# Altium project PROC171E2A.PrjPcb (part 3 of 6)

## Sheet PROC171_AM263P_6_ePWM_eQEP_FSI.SchDoc
size 431 x 279 mm; Date: Not shown in title block; ApprovedBy: Not shown in title block; CheckedBy: Not shown in title block; Author: Not shown in title block; CompanyName: Not shown in title block; Engineer: Not shown in title block; Organization: Not shown in title block; Address1: Not shown in title block; Address2: Not shown in title block; Address3: Not shown in title block; Address4: Not shown in title block; DocumentNumber: 10; Revision: Use project parameter SCH_Rev; SheetNumber: 10; SheetTotal: 26; PageSetup: Record=PageOptions¦CenterHorizontal=True¦CenterVertical=True¦PrintScale=1.00¦XCorrection=1.00¦YCorrection=1.00¦PrintKind=0¦BorderSize=5000000¦LeftOffset=0¦BottomOffset=0¦Orientation=2¦PaperLength=1000¦PaperWidth=1000¦Scale=100¦PaperSource=15¦PrintQuality=600¦MediaType=1¦DitherType=10¦PaperKind=Letter¦PrintScaleMode=1

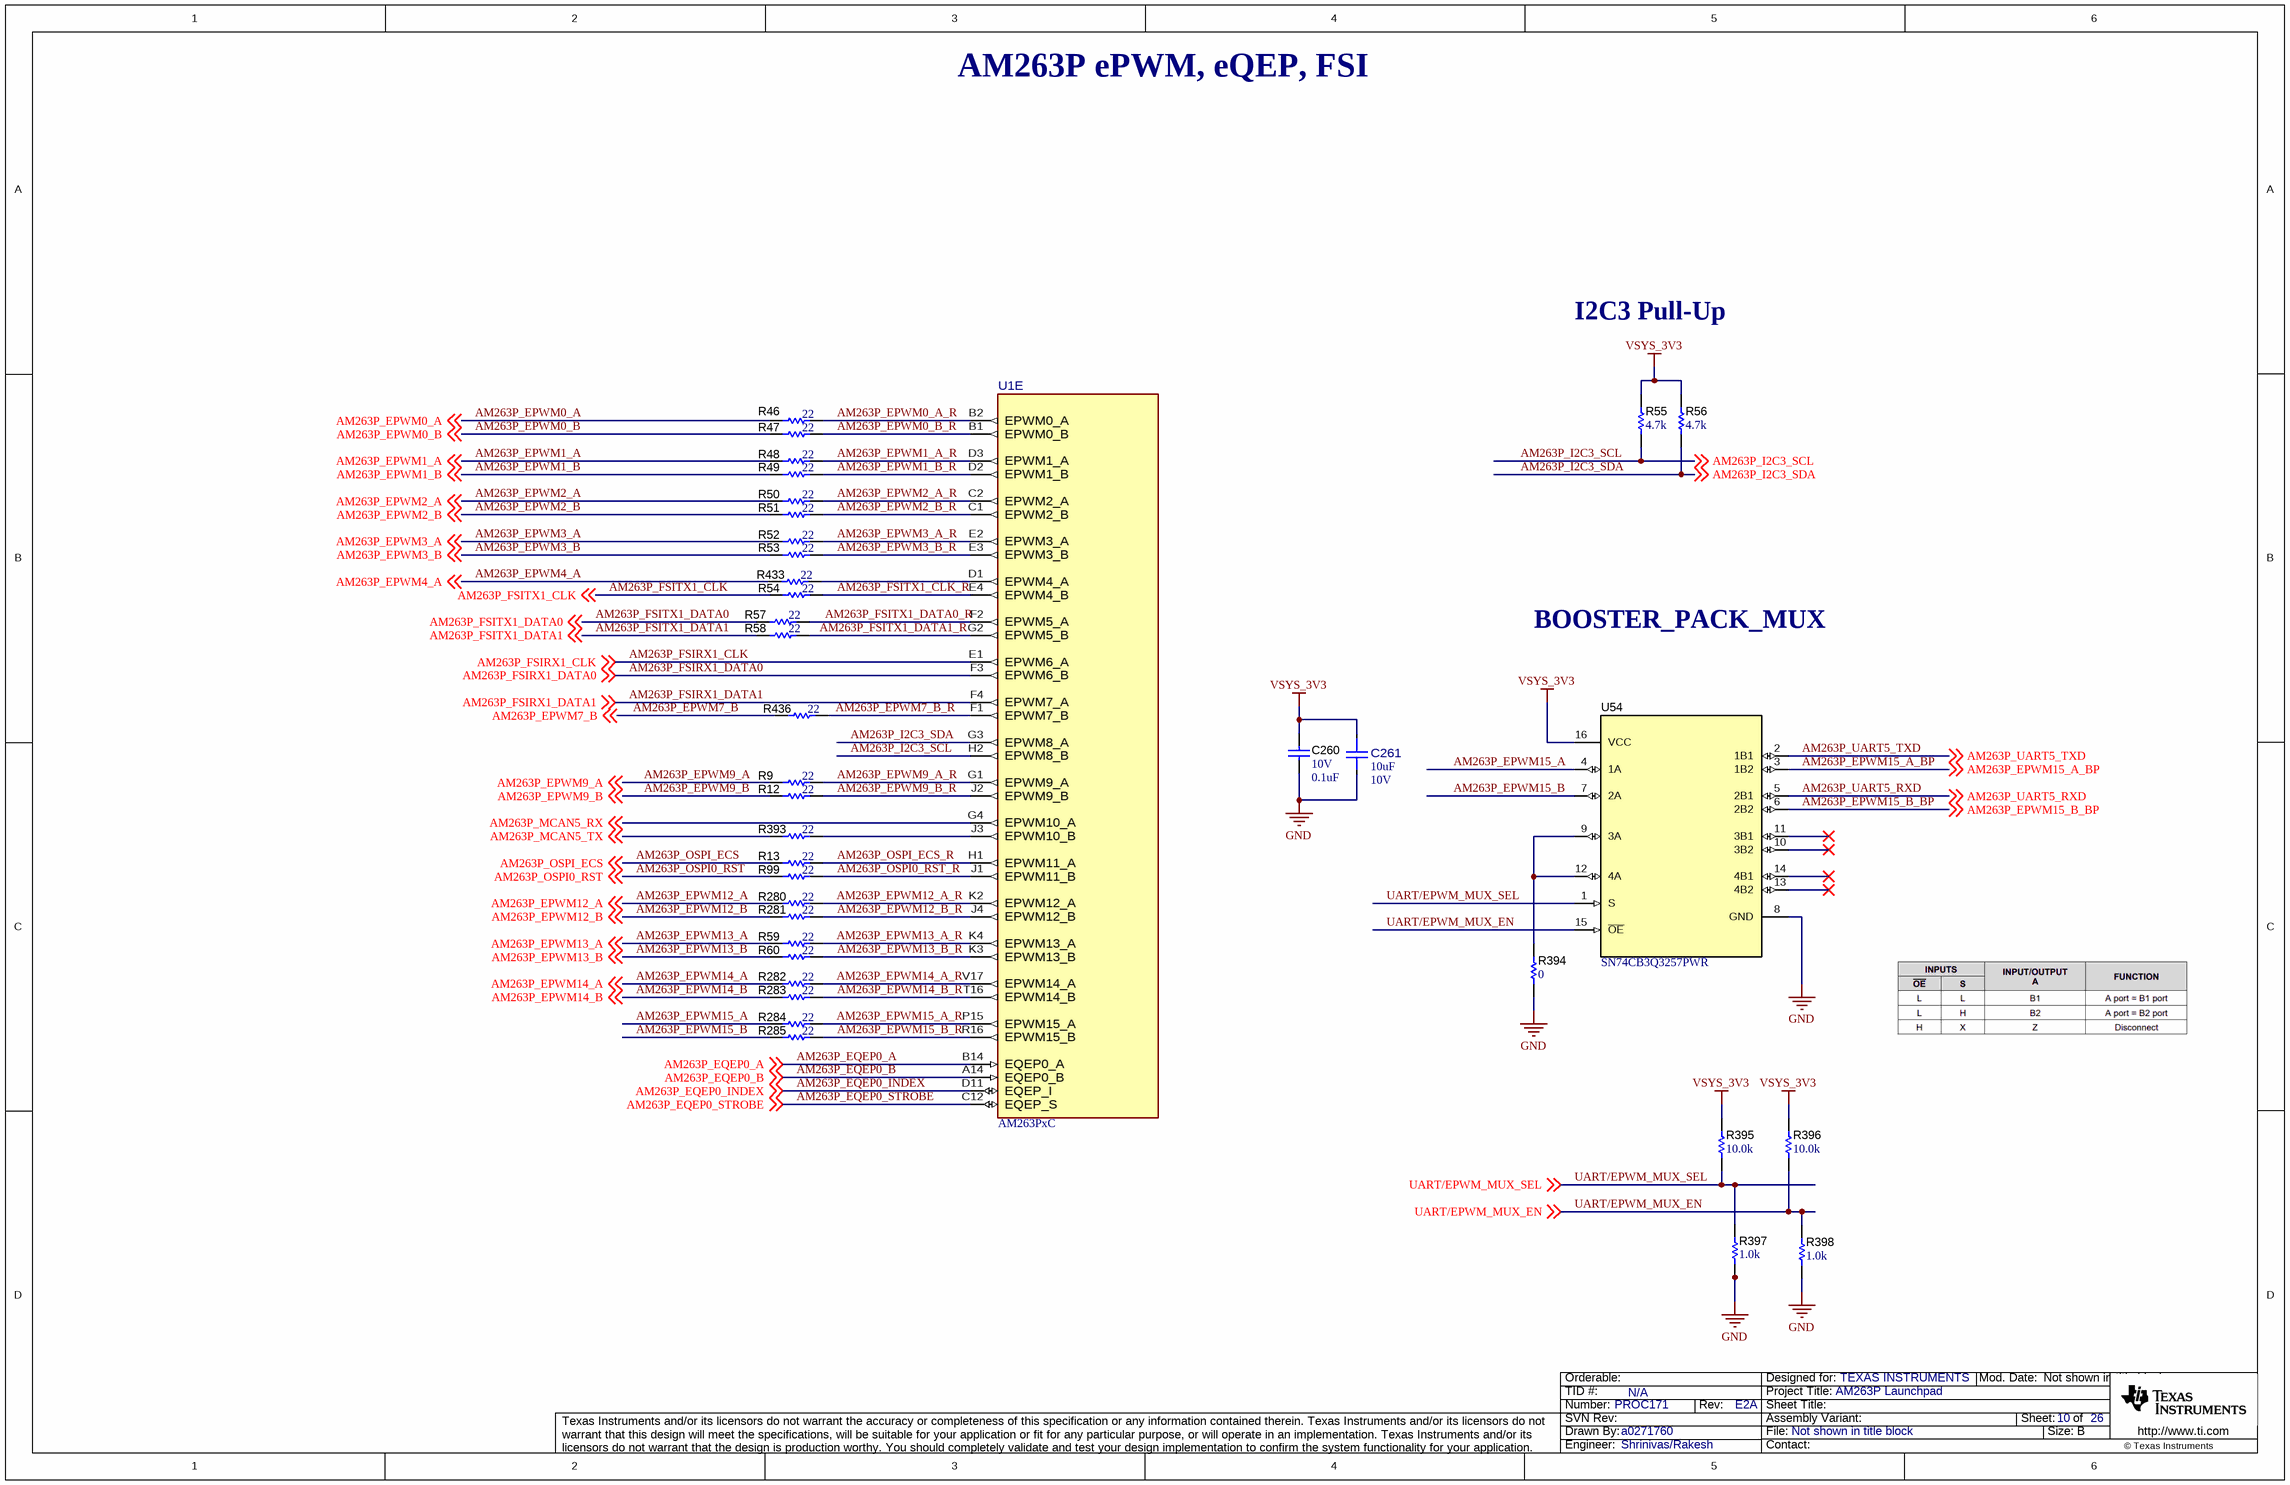
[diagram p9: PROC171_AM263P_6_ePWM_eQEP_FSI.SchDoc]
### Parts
C260  VDC_V: 10V  ValueDisplayed: 0.1uF  [0402]  (hidden comment: 885012105010)
C261  ValueDisplayed: 10uF  VDC_V: 10V  [FP-KGM05CR51A106MH_0402-MFG]  (hidden comment: KGM05CR51A106MH)
R9  ValueDisplayed: 22  [0402]  (hidden comment: CRCW040222R0JNED)
R12  ValueDisplayed: 22  [0402]  (hidden comment: CRCW040222R0JNED)
R13  ValueDisplayed: 22  [0402]  (hidden comment: CRCW040222R0JNED)
R46  ValueDisplayed: 22  [0402]  (hidden comment: CRCW040222R0JNED)
R47  ValueDisplayed: 22  [0402]  (hidden comment: CRCW040222R0JNED)
R48  ValueDisplayed: 22  [0402]  (hidden comment: CRCW040222R0JNED)
R49  ValueDisplayed: 22  [0402]  (hidden comment: CRCW040222R0JNED)
R50  ValueDisplayed: 22  [0402]  (hidden comment: CRCW040222R0JNED)
R51  ValueDisplayed: 22  [0402]  (hidden comment: CRCW040222R0JNED)
R52  ValueDisplayed: 22  [0402]  (hidden comment: CRCW040222R0JNED)
R53  ValueDisplayed: 22  [0402]  (hidden comment: CRCW040222R0JNED)
R54  ValueDisplayed: 22  [0402]  (hidden comment: CRCW040222R0JNED)
R55  ValueDisplayed: 4.7k  [0402]  (hidden comment: CRCW04024K70JNED)
R56  ValueDisplayed: 4.7k  [0402]  (hidden comment: CRCW04024K70JNED)
R57  ValueDisplayed: 22  [0402]  (hidden comment: CRCW040222R0JNED)
R58  ValueDisplayed: 22  [0402]  (hidden comment: CRCW040222R0JNED)
R59  ValueDisplayed: 22  [0402]  (hidden comment: CRCW040222R0JNED)
R60  ValueDisplayed: 22  [0402]  (hidden comment: CRCW040222R0JNED)
R99  ValueDisplayed: 22  [0402]  (hidden comment: CRCW040222R0JNED)
R280  ValueDisplayed: 22  [0402]  (hidden comment: CRCW040222R0JNED)
R281  ValueDisplayed: 22  [0402]  (hidden comment: CRCW040222R0JNED)
R282  ValueDisplayed: 22  [0402]  (hidden comment: CRCW040222R0JNED)
R283  ValueDisplayed: 22  [0402]  (hidden comment: CRCW040222R0JNED)
R284  ValueDisplayed: 22  [0402]  (hidden comment: CRCW040222R0JNED)
R285  ValueDisplayed: 22  [0402]  (hidden comment: CRCW040222R0JNED)
R393  ValueDisplayed: 22  [0402]  (hidden comment: CRCW040222R0JNED)
R394  value 0  [0402L]  (hidden comment: ERJ-2GE0R00X)
R395  ValueDisplayed: 10.0k  [0402]  (hidden comment: ERJ-2RKF1002X)
R396  ValueDisplayed: 10.0k  [0402]  (hidden comment: ERJ-2RKF1002X)
R397  ValueDisplayed: 1.0k  [0402]  (hidden comment: ERJ-2GEJ102X)
R398  ValueDisplayed: 1.0k  [0402]  (hidden comment: ERJ-2GEJ102X)
R433  ValueDisplayed: 22  [0402]  (hidden comment: CRCW040222R0JNED)
R436  ValueDisplayed: 22  [0402]  (hidden comment: CRCW040222R0JNED)
U1  AM263PxC  [ZCZ0324A-MFG]  (part E of 13)
U54  SN74CB3Q3257PWR  [PW0016A_L]

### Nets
GND: C260.2 C261.2 R394.1 R397.1 R398.1 U54.8(GND)
VSYS_3V3: C260.1 C261.1 R55.2 R56.2 R395.2 R396.2 U54.16(VCC)
AM263P_EPWM0_A: R46.1 ; off-sheet AM263P_EPWM0_A
AM263P_EPWM0_A_R: R46.2 U1.B2(EPWM0_A)
AM263P_EPWM0_B: R47.1 ; off-sheet AM263P_EPWM0_B
AM263P_EPWM0_B_R: R47.2 U1.B1(EPWM0_B)
AM263P_EPWM1_A: R48.1 ; off-sheet AM263P_EPWM1_A
AM263P_EPWM1_A_R: R48.2 U1.D3(EPWM1_A)
AM263P_EPWM1_B: R49.1 ; off-sheet AM263P_EPWM1_B
AM263P_EPWM1_B_R: R49.2 U1.D2(EPWM1_B)
AM263P_EPWM2_A: R50.1 ; off-sheet AM263P_EPWM2_A
AM263P_EPWM2_A_R: R50.2 U1.C2(EPWM2_A)
AM263P_EPWM2_B: R51.1 ; off-sheet AM263P_EPWM2_B
AM263P_EPWM2_B_R: R51.2 U1.C1(EPWM2_B)
AM263P_EPWM3_A: R52.1 ; off-sheet AM263P_EPWM3_A
AM263P_EPWM3_A_R: R52.2 U1.E2(EPWM3_A)
AM263P_EPWM3_B: R53.1 ; off-sheet AM263P_EPWM3_B
AM263P_EPWM3_B_R: R53.2 U1.E3(EPWM3_B)
AM263P_EPWM4_A: R433.1 ; off-sheet AM263P_EPWM4_A
AM263P_EPWM7_B: R436.1 ; off-sheet AM263P_EPWM7_B
AM263P_EPWM7_B_R: R436.2 U1.F1(EPWM7_B)
AM263P_EPWM9_A: R9.1 ; off-sheet AM263P_EPWM9_A
AM263P_EPWM9_A_R: R9.2 U1.G1(EPWM9_A)
AM263P_EPWM9_B: R12.1 ; off-sheet AM263P_EPWM9_B
AM263P_EPWM9_B_R: R12.2 U1.J2(EPWM9_B)
AM263P_EPWM12_A: R280.1 ; off-sheet AM263P_EPWM12_A
AM263P_EPWM12_A_R: R280.2 U1.K2(EPWM12_A)
AM263P_EPWM12_B: R281.1 ; off-sheet AM263P_EPWM12_B
AM263P_EPWM12_B_R: R281.2 U1.J4(EPWM12_B)
AM263P_EPWM13_A: R59.1 ; off-sheet AM263P_EPWM13_A
AM263P_EPWM13_A_R: R59.2 U1.K4(EPWM13_A)
AM263P_EPWM13_B: R60.1 ; off-sheet AM263P_EPWM13_B
AM263P_EPWM13_B_R: R60.2 U1.K3(EPWM13_B)
AM263P_EPWM14_A: R282.1 ; off-sheet AM263P_EPWM14_A
AM263P_EPWM14_A_R: R282.2 U1.V17(EPWM14_A)
AM263P_EPWM14_B: R283.1 ; off-sheet AM263P_EPWM14_B
AM263P_EPWM14_B_R: R283.2 U1.T16(EPWM14_B)
AM263P_EPWM15_A: R284.1 U54.4(1A)
AM263P_EPWM15_A_BP: U54.3(1B2) ; off-sheet AM263P_EPWM15_A_BP
AM263P_EPWM15_A_R: R284.2 U1.P15(EPWM15_A)
AM263P_EPWM15_B: R285.1 U54.7(2A)
AM263P_EPWM15_B_BP: U54.6(2B2) ; off-sheet AM263P_EPWM15_B_BP
AM263P_EPWM15_B_R: R285.2 U1.R16(EPWM15_B)
AM263P_EQEP0_A: U1.B14(EQEP0_A) ; off-sheet AM263P_EQEP0_A
AM263P_EQEP0_B: U1.A14(EQEP0_B) ; off-sheet AM263P_EQEP0_B
AM263P_EQEP0_INDEX: U1.D11(EQEP_I) ; off-sheet AM263P_EQEP0_INDEX
AM263P_EQEP0_STROBE: U1.C12(EQEP_S) ; off-sheet AM263P_EQEP0_STROBE
AM263P_FSIRX1_CLK: U1.E1(EPWM6_A) ; off-sheet AM263P_FSIRX1_CLK
AM263P_FSIRX1_DATA0: U1.F3(EPWM6_B) ; off-sheet AM263P_FSIRX1_DATA0
AM263P_FSIRX1_DATA1: U1.F4(EPWM7_A) ; off-sheet AM263P_FSIRX1_DATA1
AM263P_FSITX1_CLK: R54.1 ; off-sheet AM263P_FSITX1_CLK
AM263P_FSITX1_CLK_R: R54.2 U1.E4(EPWM4_B)
AM263P_FSITX1_DATA0: R57.1 ; off-sheet AM263P_FSITX1_DATA0
AM263P_FSITX1_DATA0_R: R57.2 U1.F2(EPWM5_A)
AM263P_FSITX1_DATA1: R58.1 ; off-sheet AM263P_FSITX1_DATA1
AM263P_FSITX1_DATA1_R: R58.2 U1.G2(EPWM5_B)
AM263P_I2C3_SCL: R55.1 U1.H2(EPWM8_B) ; off-sheet AM263P_I2C3_SCL
AM263P_I2C3_SDA: R56.1 U1.G3(EPWM8_A) ; off-sheet AM263P_I2C3_SDA
AM263P_MCAN5_RX: U1.G4(EPWM10_A) ; off-sheet AM263P_MCAN5_RX
AM263P_MCAN5_TX: R393.1 ; off-sheet AM263P_MCAN5_TX
AM263P_OSPI0_RST: R99.1 ; off-sheet AM263P_OSPI0_RST
AM263P_OSPI0_RST_R: R99.2 U1.J1(EPWM11_B)
AM263P_OSPI_ECS: R13.1 ; off-sheet AM263P_OSPI_ECS
AM263P_OSPI_ECS_R: R13.2 U1.H1(EPWM11_A)
AM263P_UART5_RXD: U54.5(2B1) ; off-sheet AM263P_UART5_RXD
AM263P_UART5_TXD: U54.2(1B1) ; off-sheet AM263P_UART5_TXD
UART/EPWM_MUX_EN: R396.1 R398.2 U54.15(~{OE}) ; off-sheet UART/EPWM_MUX_EN
UART/EPWM_MUX_SEL: R395.1 R397.2 U54.1(S) ; off-sheet UART/EPWM_MUX_SEL
NetR393_2: R393.2 U1.J3(EPWM10_B)
NetR394_2: R394.2 U54.9(3A) U54.12(4A)
NetR433_2: R433.2 U1.D1(EPWM4_A)

Not connected (* = marked no-connect by the designer): U54 10(3B2)* 11(3B1)* 13(4B2)* 14(4B1)*

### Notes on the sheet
- AM263P ePWM, eQEP, FSI
- I2C3 Pull-Up
- BOOSTER_PACK_MUX

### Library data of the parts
C260 = CMP-0006221-2: CAP, CERM, 0.1 uF, 10 V, +/- 20%, X5R, 0402; Manufacturer: Wurth Elektronik; TaMin_C: -55°C; Polarized: N; SizeAreaWB_mm2: 3; Value1: Unknown; U/M: EA; Value: 0.1uF; TaMax_C: 85°C; SizeZ_mm: 0.6; SizeX_mm: 1; SizeY_mm: 0.5; Cap_F: 100nF; AEC Category: Q200
C261 = CMP-0043010-1: 10 µF ±20% 10V Ceramic Capacitor X5R 0402 (1005 Metric); Manufacturer: KYOCERA AVX; AEC Qualified: No; Cap_F: 10µF; SizeZ_mm: 0.7mm; TempCo: 15%; Value: 10µF
R9 R12 R13 R46-R54 R57-R60 R99 R280-R285 R393 R433 R436 = CMP-0026880-3: RES, 22, 5%, 0.063 W, AEC-Q200 Grade 0, 0402; Manufacturer: Vishay-Dale; Power_W: 63mW; TempCo: 200 ppm/C; Value_Code: 22R0; Value: 22; EIA_Code: E24; SizeX_mm: 1; SizeY_mm: 0.5; SizeZ_mm: 0.6; Value2: 0.063W; AEC Qualified: Y; VDC_V: 50V; AEC Category: Q200; AEC Grade: 0
R55 R56 = CMP-0026938-5: RES, 4.7 k, 5%, 0.063 W, AEC-Q200 Grade 0, 0402; Manufacturer: Vishay-Dale; Power_W: 63mW; TempCo: 200 ppm/C; Value_Code: 4k70; Value: 4.7k; EIA_Code: E24; SizeX_mm: 1; SizeY_mm: 0.5; SizeZ_mm: 0.6; Value2: 0.063W; AEC Qualified: Y; VDC_V: 50V; AEC Category: Q200; AEC Grade: 0
R394 = CMP-0026992-3: RES, 0, 5%, 0.1 W, AEC-Q200 Grade 0, 0402; Manufacturer: Panasonic; Power_W: 100mW; TempCo: 600 ppm/C; Value_Code: 0000; EIA_Code: E24; SizeX_mm: 1; SizeY_mm: 0.5; SizeZ_mm: 0.6; Value2: 0.1W; AEC Qualified: Y; VDC_V: 50V; AEC Category: Q200; SizeAreaWB_mm2: 3
R395 R396 = CMP-0026658-1: RES, 10.0 k, 1%, 0.1 W, 0402; Manufacturer: Panasonic; Power_W: 100mW; TempCo: 100 ppm/C; Value_Code: 10k0; U/M: EA; Value: 10.0k; EIA_Code: E96; Res_ohm: 10k; SizeX_mm: 1; SizeY_mm: 0.5; SizeZ_mm: 0.6; Value2: 0.1W; VDC_V: 50V; AEC Category: Q200
R397 R398 = CMP-0078193-1: RES, 1.0 k, 5%, 0.1 W, AEC-Q200 Grade 0, 0402; Manufacturer: Panasonic; Value_Code: 1k00; SizeArea_mm2: 0.5; AEC Qualified: Y; AEC Category: Q200; Res_ohm: 1k; Value: 1.0k; SizeZ_mm: 0.6; Green_REACh: Passed; EIA_Code: E24; TempCo: 200 ppm/C; AEC Grade: 0; Power_W: 100mW; VDC_V: 50V; Value2: 0.1W; Green_Lifecycle: Active; U/M: EA; SizeX_mm: 1
U1 = CMP-0001698-2: Sitara™ Microcontroller; Manufacturer: Texas Instruments; SizeZ_mm: 1.4mm; Core Architecture: ARM Cortex-R5F; Data Bus Width: 32bits; Frequency_Fixed: 200MHz; Interface: I2C,SPI,UART,CAN,LIN,Ethernet,Other; Max Supply Voltage: 3.465V; Memory Size: 2MBytes; Memory Type: RAM; Min Supply Voltage: 1.14V; Number Of Cores: 1; Number Of I/Os: 140; Number Of I2C Channels: 4; Number Of Spi Channels: 5; Number Of Uart Channels: 6; Standoff Height: 0.35mm; AEC Category: Q200; CompType: IC
U54 = CMP-0076540-1: 4-Bit One-of-2 FET Multiplexer/Demultiplexer 2.5-V/3.3-V Low-Voltage, High-Bandwidth Bus Switch, PW0016A (TSSOP-16); Manufacturer: Texas Instruments; SizeAreaWB_mm2: 58.8; SizeArea_mm2: 32.0; SizeZ_mm: 1.2; SizeY_mm: 5.0; U/M: EA; CompType: IC; SizeX_mm: 6.4

## Sheet PROC171_AM263P_7_RGMII_MII.SchDoc
size 431 x 279 mm; Date: Not shown in title block; ApprovedBy: Not shown in title block; CheckedBy: Not shown in title block; Author: Not shown in title block; CompanyName: Not shown in title block; Engineer: Not shown in title block; Organization: Not shown in title block; Address1: Not shown in title block; Address2: Not shown in title block; Address3: Not shown in title block; Address4: Not shown in title block; DocumentNumber: 11; Revision: Use project parameter SCH_Rev; SheetNumber: 11; SheetTotal: 26; PageSetup: Record=PageOptions¦CenterHorizontal=True¦CenterVertical=True¦PrintScale=1.00¦XCorrection=1.00¦YCorrection=1.00¦PrintKind=0¦BorderSize=5000000¦LeftOffset=0¦BottomOffset=0¦Orientation=2¦PaperLength=1000¦PaperWidth=1000¦Scale=100¦PaperSource=15¦PrintQuality=600¦MediaType=1¦DitherType=10¦PaperKind=Letter¦PrintScaleMode=1

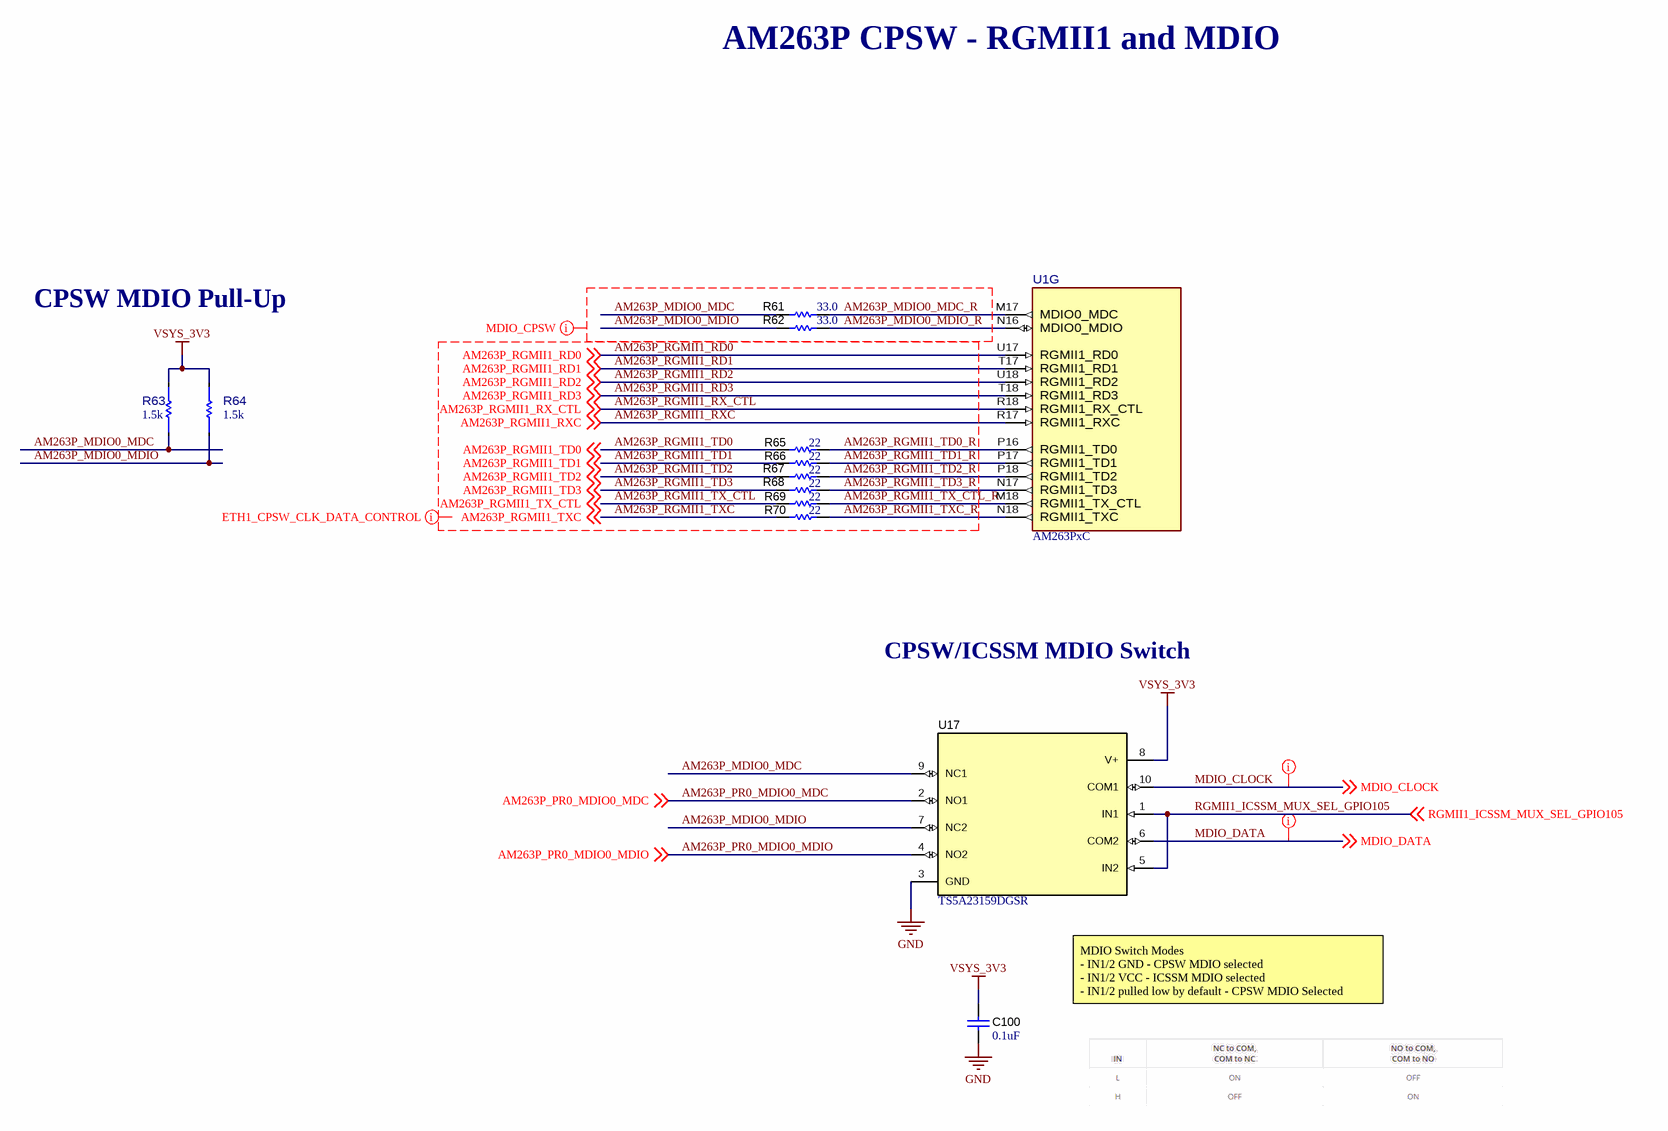
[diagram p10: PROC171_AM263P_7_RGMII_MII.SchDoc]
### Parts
C100  ValueDisplayed: 0.1uF  [0402]  (hidden comment: GRM155R71E104KE14D)
R61  ValueDisplayed: 33.0  [0402L]  (hidden comment: ERJ-2RKF33R0X)
R62  ValueDisplayed: 33.0  [0402L]  (hidden comment: ERJ-2RKF33R0X)
R63  value 1.5k  [FP-ERJ-2GEJ152X_0402-MFG]  (hidden comment: ERJ-2GEJ152X)
R64  value 1.5k  [FP-ERJ-2GEJ152X_0402-MFG]  (hidden comment: ERJ-2GEJ152X)
R65  ValueDisplayed: 22  [0402]  (hidden comment: CRCW040222R0JNED)
R66  ValueDisplayed: 22  [0402]  (hidden comment: CRCW040222R0JNED)
R67  ValueDisplayed: 22  [0402]  (hidden comment: CRCW040222R0JNED)
R68  ValueDisplayed: 22  [0402]  (hidden comment: CRCW040222R0JNED)
R69  ValueDisplayed: 22  [0402]  (hidden comment: CRCW040222R0JNED)
R70  ValueDisplayed: 22  [0402]  (hidden comment: CRCW040222R0JNED)
U1  AM263PxC  [ZCZ0324A-MFG]  (part G of 13)
U17  TS5A23159DGSR  [DGS0010A_N]

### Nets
GND: C100.1 U17.3(GND)
VSYS_3V3: C100.2 R63.2 R64.2 U17.8(V+)
AM263P_MDIO0_MDC: R61.1 R63.1 U17.9(NC1)
AM263P_MDIO0_MDC_R: R61.2 U1.M17(MDIO0_MDC)
AM263P_MDIO0_MDIO: R62.1 R64.1 U17.7(NC2)
AM263P_MDIO0_MDIO_R: R62.2 U1.N16(MDIO0_MDIO)
AM263P_PR0_MDIO0_MDC: U17.2(NO1) ; off-sheet AM263P_PR0_MDIO0_MDC
AM263P_PR0_MDIO0_MDIO: U17.4(NO2) ; off-sheet AM263P_PR0_MDIO0_MDIO
AM263P_RGMII1_RD0: U1.U17(RGMII1_RD0) ; off-sheet AM263P_RGMII1_RD0
AM263P_RGMII1_RD1: U1.T17(RGMII1_RD1) ; off-sheet AM263P_RGMII1_RD1
AM263P_RGMII1_RD2: U1.U18(RGMII1_RD2) ; off-sheet AM263P_RGMII1_RD2
AM263P_RGMII1_RD3: U1.T18(RGMII1_RD3) ; off-sheet AM263P_RGMII1_RD3
AM263P_RGMII1_RX_CTL: U1.R18(RGMII1_RX_CTL) ; off-sheet AM263P_RGMII1_RX_CTL
AM263P_RGMII1_RXC: U1.R17(RGMII1_RXC) ; off-sheet AM263P_RGMII1_RXC
AM263P_RGMII1_TD0: R65.1 ; off-sheet AM263P_RGMII1_TD0
AM263P_RGMII1_TD0_R: R65.2 U1.P16(RGMII1_TD0)
AM263P_RGMII1_TD1: R66.1 ; off-sheet AM263P_RGMII1_TD1
AM263P_RGMII1_TD1_R: R66.2 U1.P17(RGMII1_TD1)
AM263P_RGMII1_TD2: R67.1 ; off-sheet AM263P_RGMII1_TD2
AM263P_RGMII1_TD2_R: R67.2 U1.P18(RGMII1_TD2)
AM263P_RGMII1_TD3: R68.1 ; off-sheet AM263P_RGMII1_TD3
AM263P_RGMII1_TD3_R: R68.2 U1.N17(RGMII1_TD3)
AM263P_RGMII1_TX_CTL: R69.1 ; off-sheet AM263P_RGMII1_TX_CTL
AM263P_RGMII1_TX_CTL_R: R69.2 U1.M18(RGMII1_TX_CTL)
AM263P_RGMII1_TXC: R70.1 ; off-sheet AM263P_RGMII1_TXC
AM263P_RGMII1_TXC_R: R70.2 U1.N18(RGMII1_TXC)
MDIO_CLOCK: U17.10(COM1) ; off-sheet MDIO_CLOCK
MDIO_DATA: U17.6(COM2) ; off-sheet MDIO_DATA
RGMII1_ICSSM_MUX_SEL_GPIO105: U17.1(IN1) U17.5(IN2) ; off-sheet RGMII1_ICSSM_MUX_SEL_GPIO105

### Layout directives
mark named ETH1_CPSW_CLK_DATA_CONTROL: AM263P_RGMII1_RD0, AM263P_RGMII1_RD1, AM263P_RGMII1_RD2, AM263P_RGMII1_RD3, AM263P_RGMII1_RX_CTL, AM263P_RGMII1_RXC, AM263P_RGMII1_TD0, AM263P_RGMII1_TD0_R, AM263P_RGMII1_TD1, AM263P_RGMII1_TD1_R, AM263P_RGMII1_TD2, AM263P_RGMII1_TD2_R, AM263P_RGMII1_TD3, AM263P_RGMII1_TD3_R, AM263P_RGMII1_TX_CTL, AM263P_RGMII1_TX_CTL_R, AM263P_RGMII1_TXC, AM263P_RGMII1_TXC_R
mark named MDIO_CPSW: AM263P_MDIO0_MDC, AM263P_MDIO0_MDC_R, AM263P_MDIO0_MDIO, AM263P_MDIO0_MDIO_R
mark named MDIO: MDIO_CLOCK, MDIO_DATA

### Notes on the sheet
- AM263P CPSW - RGMII1 and MDIO
- CPSW MDIO Pull-Up
- CPSW/ICSSM MDIO Switch
- MDIO Switch Modes
  - IN1/2 GND - CPSW MDIO selected
  - IN1/2 VCC - ICSSM MDIO selected
  - IN1/2 pulled low by default - CPSW MDIO Selected

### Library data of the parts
C100 = CMP-0006659-2: CAP, CERM, 0.1 uF, 25 V, +/- 10%, X7R, 0402; Manufacturer: MuRata; TaMin_C: -55°C; Polarized: N; SizeAreaWB_mm2: 3; U/M: EA; Value: 0.1uF; TaMax_C: 125°C; SizeZ_mm: 0.6; SizeX_mm: 1; SizeY_mm: 0.5; Value2: 25V; Cap_F: 100nF; AEC Category: Q200; Value1: Unknown
R61 R62 = CMP-0026696-1: RES, 33.0, 1%, 0.1 W, 0402; Manufacturer: Panasonic; Power_W: 100mW; TempCo: 100 ppm/C; Value_Code: 33R0; U/M: EA; Value: 33.0; Res_ohm: 33; SizeX_mm: 1; SizeY_mm: 0.5; SizeZ_mm: 0.6; Value2: 0.1W; VDC_V: 50V; AEC Category: Q200
R63 R64 = CMP-0042990-1: Res Thick Film 0402 1.5K Ohm 5% 1/10W ±200ppm/°C Molded SMD Punched Carrier T/R; Manufacturer: Panasonic; AEC Grade: Grade 0; AEC Qualified: Yes; Power_W: 100mW; SizeZ_mm: 0.4mm; VDC_V: 50V; Category 5A00970A6D5C81C7: Uncategorized; Category 5C6A91606D4187Ad: Resistors; Category 7542B8484461Ae85: Passive Components; Category Cd01000Bfc2916C6: Single Components
R65-R70 = CMP-0026880-3: as R9 on sheet PROC171_AM263P_6_ePWM_eQEP_FSI
U1 = CMP-0001698-2: as U1 on sheet PROC171_AM263P_6_ePWM_eQEP_FSI
U17 = CMP-0067419-2: 2-Channel, 2:1 Analog Switch with Low On-State Resistance (1ohm) and Powered Off Protection, DGS0010A (VSSOP-10); Alternate PartNumber: TS5A23159DGST; Alternate Manufacturer: Texas Instruments; Green_Lifecycle: Active; SizeAreaWB_mm2: 23.6; Green_REACh: Passed; SizeZ_mm: 1.1; SizeX_mm: 4.9; SizeY_mm: 3.0; SizeArea_mm2: 14.7; CompType: IC; AEC Category: Q200; AEC Qualified: N; Rating: Catalog

## Sheet PROC171_AM263P_8_PRU.SchDoc
size 431 x 279 mm; Date: Not shown in title block; ApprovedBy: Not shown in title block; CheckedBy: Not shown in title block; Author: Not shown in title block; CompanyName: Not shown in title block; Engineer: Not shown in title block; Organization: Not shown in title block; Address1: Not shown in title block; Address2: Not shown in title block; Address3: Not shown in title block; Address4: Not shown in title block; DocumentNumber: 12; Revision: Use project parameter SCH_Rev; SheetNumber: 12; SheetTotal: 26; PageSetup: Record=PageOptions¦CenterHorizontal=True¦CenterVertical=True¦PrintScale=1.00¦XCorrection=1.00¦YCorrection=1.00¦PrintKind=0¦BorderSize=5000000¦LeftOffset=0¦BottomOffset=0¦Orientation=2¦PaperLength=1000¦PaperWidth=1000¦Scale=100¦PaperSource=15¦PrintQuality=600¦MediaType=1¦DitherType=10¦PaperKind=Letter¦PrintScaleMode=1

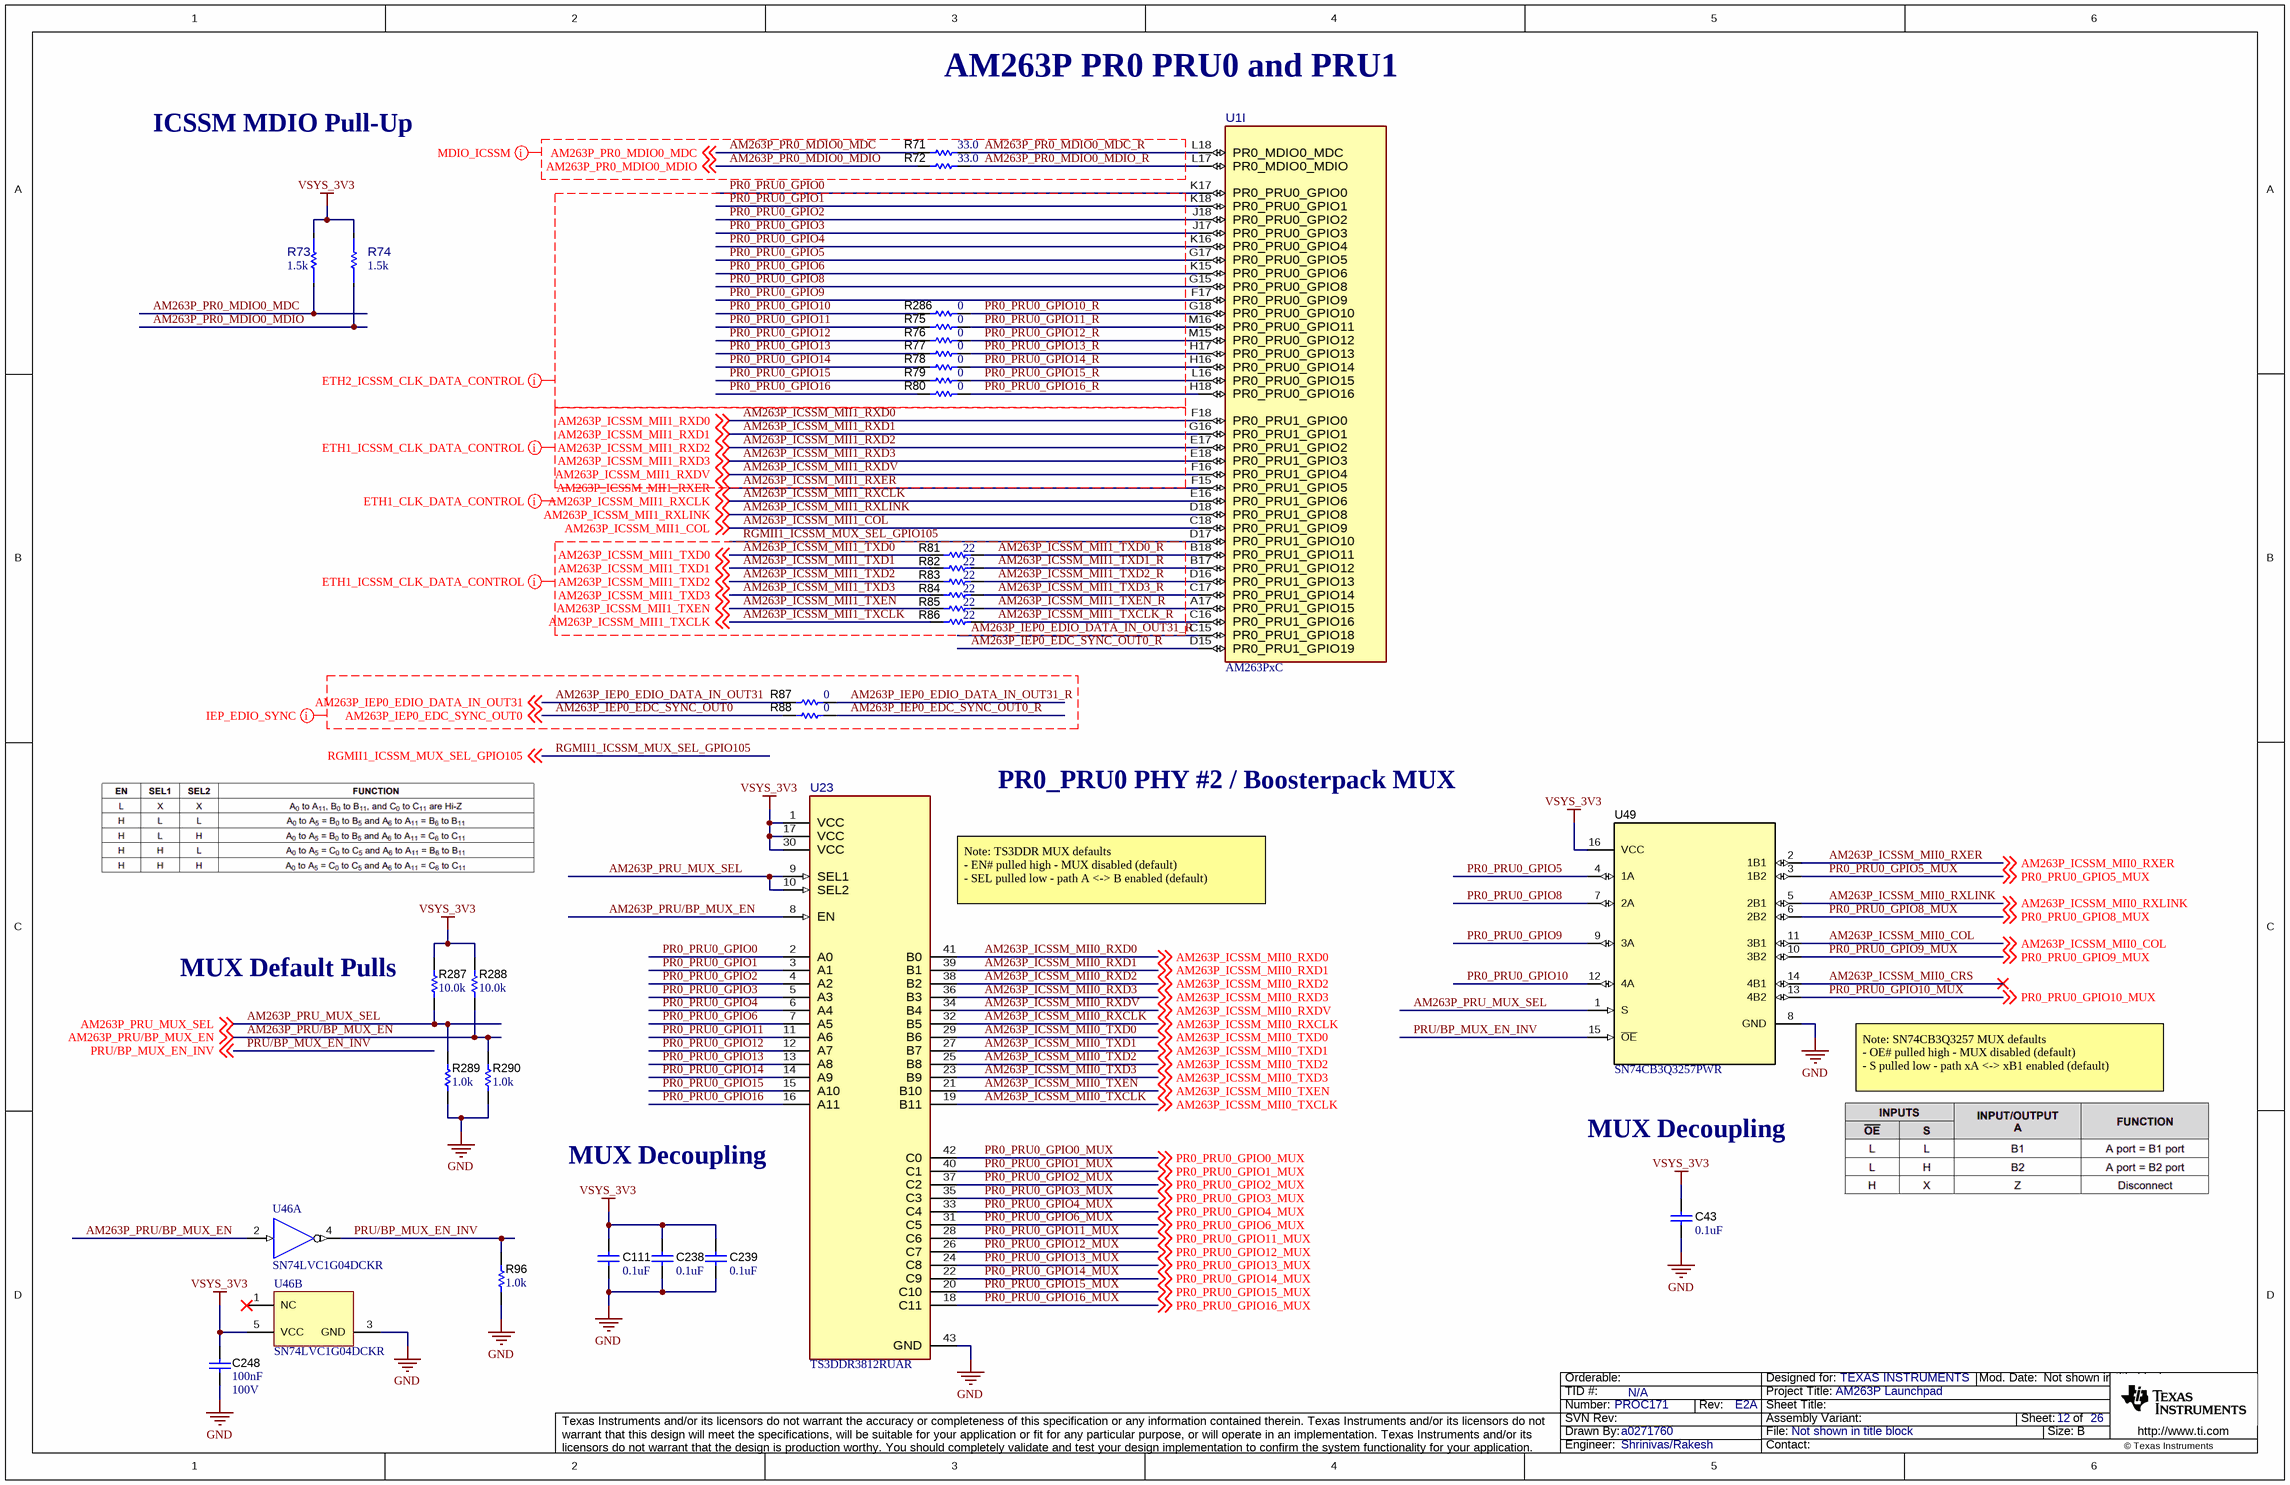
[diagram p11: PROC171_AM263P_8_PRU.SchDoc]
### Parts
C43  ValueDisplayed: 0.1uF  [0402]  (hidden comment: GRM155R71E104KE14D)
C111  ValueDisplayed: 0.1uF  [0402]  (hidden comment: GRM155R71E104KE14D)
C238  ValueDisplayed: 0.1uF  [0402]  (hidden comment: GRM155R71E104KE14D)
C239  ValueDisplayed: 0.1uF  [0402]  (hidden comment: GRM155R71E104KE14D)
C248  Cap_F: 100nF  VDC_V: 100V  [0603]  (hidden comment: GRM188R72A104KA35D)
R71  ValueDisplayed: 33.0  [0402L]  (hidden comment: ERJ-2RKF33R0X)
R72  ValueDisplayed: 33.0  [0402L]  (hidden comment: ERJ-2RKF33R0X)
R73  value 1.5k  [FP-ERJ-2GEJ152X_0402-MFG]  (hidden comment: ERJ-2GEJ152X)
R74  value 1.5k  [FP-ERJ-2GEJ152X_0402-MFG]  (hidden comment: ERJ-2GEJ152X)
R75  value 0  [0402L]  (hidden comment: ERJ-2GE0R00X)
R76  value 0  [0402L]  (hidden comment: ERJ-2GE0R00X)
R77  value 0  [0402L]  (hidden comment: ERJ-2GE0R00X)
R78  value 0  [0402L]  (hidden comment: ERJ-2GE0R00X)
R79  value 0  [0402L]  (hidden comment: ERJ-2GE0R00X)
R80  value 0  [0402L]  (hidden comment: ERJ-2GE0R00X)
R81  ValueDisplayed: 22  [0402]  (hidden comment: CRCW040222R0JNED)
R82  ValueDisplayed: 22  [0402]  (hidden comment: CRCW040222R0JNED)
R83  ValueDisplayed: 22  [0402]  (hidden comment: CRCW040222R0JNED)
R84  ValueDisplayed: 22  [0402]  (hidden comment: CRCW040222R0JNED)
R85  ValueDisplayed: 22  [0402]  (hidden comment: CRCW040222R0JNED)
R86  ValueDisplayed: 22  [0402]  (hidden comment: CRCW040222R0JNED)
R87  value 0  [0402L]  (hidden comment: ERJ-2GE0R00X)
R88  value 0  [0402L]  (hidden comment: ERJ-2GE0R00X)
R96  ValueDisplayed: 1.0k  [0402]  (hidden comment: ERJ-2GEJ102X)
R286  value 0  [0402L]  (hidden comment: ERJ-2GE0R00X)
R287  ValueDisplayed: 10.0k  [0402]  (hidden comment: ERJ-2RKF1002X)
R288  ValueDisplayed: 10.0k  [0402]  (hidden comment: ERJ-2RKF1002X)
R289  ValueDisplayed: 1.0k  [0402]  (hidden comment: ERJ-2GEJ102X)
R290  ValueDisplayed: 1.0k  [0402]  (hidden comment: ERJ-2GEJ102X)
U1  AM263PxC  [ZCZ0324A-MFG]  (part I of 13)
U23  TS3DDR3812RUAR  [RUA0042A-MFG]
U46  SN74LVC1G04DCKR  [DCK0005A_N]  (parts A,B of 2)
U49  SN74CB3Q3257PWR  [PW0016A_L]

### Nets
GND: C43.1 C111.1 C238.1 C239.1 C248.2 R96.1 R289.1 R290.1 U23.43(GND) U46.3(GND) U49.8(GND)
VSYS_3V3: C43.2 C111.2 C238.2 C239.2 C248.1 R73.2 R74.2 R287.1 R288.1 U23.1(VCC) U23.17(VCC) U23.30(VCC) U46.5(VCC) U49.16(VCC)
AM263P_ICSSM_MII0_COL: U49.11(3B1) ; off-sheet AM263P_ICSSM_MII0_COL
AM263P_ICSSM_MII0_CRS: U49.14(4B1)
AM263P_ICSSM_MII0_RXCLK: U23.32(B5) ; off-sheet AM263P_ICSSM_MII0_RXCLK
AM263P_ICSSM_MII0_RXD0: U23.41(B0) ; off-sheet AM263P_ICSSM_MII0_RXD0
AM263P_ICSSM_MII0_RXD1: U23.39(B1) ; off-sheet AM263P_ICSSM_MII0_RXD1
AM263P_ICSSM_MII0_RXD2: U23.38(B2) ; off-sheet AM263P_ICSSM_MII0_RXD2
AM263P_ICSSM_MII0_RXD3: U23.36(B3) ; off-sheet AM263P_ICSSM_MII0_RXD3
AM263P_ICSSM_MII0_RXDV: U23.34(B4) ; off-sheet AM263P_ICSSM_MII0_RXDV
AM263P_ICSSM_MII0_RXER: U49.2(1B1) ; off-sheet AM263P_ICSSM_MII0_RXER
AM263P_ICSSM_MII0_RXLINK: U49.5(2B1) ; off-sheet AM263P_ICSSM_MII0_RXLINK
AM263P_ICSSM_MII0_TXCLK: U23.19(B11) ; off-sheet AM263P_ICSSM_MII0_TXCLK
AM263P_ICSSM_MII0_TXD0: U23.29(B6) ; off-sheet AM263P_ICSSM_MII0_TXD0
AM263P_ICSSM_MII0_TXD1: U23.27(B7) ; off-sheet AM263P_ICSSM_MII0_TXD1
AM263P_ICSSM_MII0_TXD2: U23.25(B8) ; off-sheet AM263P_ICSSM_MII0_TXD2
AM263P_ICSSM_MII0_TXD3: U23.23(B9) ; off-sheet AM263P_ICSSM_MII0_TXD3
AM263P_ICSSM_MII0_TXEN: U23.21(B10) ; off-sheet AM263P_ICSSM_MII0_TXEN
AM263P_ICSSM_MII1_COL: U1.C18(PR0_PRU1_GPIO9) ; off-sheet AM263P_ICSSM_MII1_COL
AM263P_ICSSM_MII1_RXCLK: U1.E16(PR0_PRU1_GPIO6) ; off-sheet AM263P_ICSSM_MII1_RXCLK
AM263P_ICSSM_MII1_RXD0: U1.F18(PR0_PRU1_GPIO0) ; off-sheet AM263P_ICSSM_MII1_RXD0
AM263P_ICSSM_MII1_RXD1: U1.G16(PR0_PRU1_GPIO1) ; off-sheet AM263P_ICSSM_MII1_RXD1
AM263P_ICSSM_MII1_RXD2: U1.E17(PR0_PRU1_GPIO2) ; off-sheet AM263P_ICSSM_MII1_RXD2
AM263P_ICSSM_MII1_RXD3: U1.E18(PR0_PRU1_GPIO3) ; off-sheet AM263P_ICSSM_MII1_RXD3
AM263P_ICSSM_MII1_RXDV: U1.F16(PR0_PRU1_GPIO4) ; off-sheet AM263P_ICSSM_MII1_RXDV
AM263P_ICSSM_MII1_RXER: U1.F15(PR0_PRU1_GPIO5) ; off-sheet AM263P_ICSSM_MII1_RXER
AM263P_ICSSM_MII1_RXLINK: U1.D18(PR0_PRU1_GPIO8) ; off-sheet AM263P_ICSSM_MII1_RXLINK
AM263P_ICSSM_MII1_TXCLK: R86.1 ; off-sheet AM263P_ICSSM_MII1_TXCLK
AM263P_ICSSM_MII1_TXCLK_R: R86.2 U1.C16(PR0_PRU1_GPIO16)
AM263P_ICSSM_MII1_TXD0: R81.1 ; off-sheet AM263P_ICSSM_MII1_TXD0
AM263P_ICSSM_MII1_TXD0_R: R81.2 U1.B18(PR0_PRU1_GPIO11)
AM263P_ICSSM_MII1_TXD1: R82.1 ; off-sheet AM263P_ICSSM_MII1_TXD1
AM263P_ICSSM_MII1_TXD1_R: R82.2 U1.B17(PR0_PRU1_GPIO12)
AM263P_ICSSM_MII1_TXD2: R83.1 ; off-sheet AM263P_ICSSM_MII1_TXD2
AM263P_ICSSM_MII1_TXD2_R: R83.2 U1.D16(PR0_PRU1_GPIO13)
AM263P_ICSSM_MII1_TXD3: R84.1 ; off-sheet AM263P_ICSSM_MII1_TXD3
AM263P_ICSSM_MII1_TXD3_R: R84.2 U1.C17(PR0_PRU1_GPIO14)
AM263P_ICSSM_MII1_TXEN: R85.1 ; off-sheet AM263P_ICSSM_MII1_TXEN
AM263P_ICSSM_MII1_TXEN_R: R85.2 U1.A17(PR0_PRU1_GPIO15)
AM263P_IEP0_EDC_SYNC_OUT0: R88.1 ; off-sheet AM263P_IEP0_EDC_SYNC_OUT0
AM263P_IEP0_EDC_SYNC_OUT0_R: R88.2 U1.D15(PR0_PRU1_GPIO19)
AM263P_IEP0_EDIO_DATA_IN_OUT31: R87.1 ; off-sheet AM263P_IEP0_EDIO_DATA_IN_OUT31
AM263P_IEP0_EDIO_DATA_IN_OUT31_R: R87.2 U1.C15(PR0_PRU1_GPIO18)
AM263P_PR0_MDIO0_MDC: R71.1 R73.1 ; off-sheet AM263P_PR0_MDIO0_MDC
AM263P_PR0_MDIO0_MDC_R: R71.2 U1.L18(PR0_MDIO0_MDC)
AM263P_PR0_MDIO0_MDIO: R72.1 R74.1 ; off-sheet AM263P_PR0_MDIO0_MDIO
AM263P_PR0_MDIO0_MDIO_R: R72.2 U1.L17(PR0_MDIO0_MDIO)
AM263P_PRU/BP_MUX_EN: R288.2 R290.2 U23.8(EN) U46.2(A) ; off-sheet AM263P_PRU/BP_MUX_EN
AM263P_PRU_MUX_SEL: R287.2 R289.2 U23.9(SEL1) U23.10(SEL2) U49.1(S) ; off-sheet AM263P_PRU_MUX_SEL
PR0_PRU0_GPIO0: U1.K17(PR0_PRU0_GPIO0) U23.2(A0)
PR0_PRU0_GPIO0_MUX: U23.42(C0) ; off-sheet PR0_PRU0_GPIO0_MUX
PR0_PRU0_GPIO1: U1.K18(PR0_PRU0_GPIO1) U23.3(A1)
PR0_PRU0_GPIO1_MUX: U23.40(C1) ; off-sheet PR0_PRU0_GPIO1_MUX
PR0_PRU0_GPIO2: U1.J18(PR0_PRU0_GPIO2) U23.4(A2)
PR0_PRU0_GPIO2_MUX: U23.37(C2) ; off-sheet PR0_PRU0_GPIO2_MUX
PR0_PRU0_GPIO3: U1.J17(PR0_PRU0_GPIO3) U23.5(A3)
PR0_PRU0_GPIO3_MUX: U23.35(C3) ; off-sheet PR0_PRU0_GPIO3_MUX
PR0_PRU0_GPIO4: U1.K16(PR0_PRU0_GPIO4) U23.6(A4)
PR0_PRU0_GPIO4_MUX: U23.33(C4) ; off-sheet PR0_PRU0_GPIO4_MUX
PR0_PRU0_GPIO5: U1.G17(PR0_PRU0_GPIO5) U49.4(1A)
PR0_PRU0_GPIO5_MUX: U49.3(1B2) ; off-sheet PR0_PRU0_GPIO5_MUX
PR0_PRU0_GPIO6: U1.K15(PR0_PRU0_GPIO6) U23.7(A5)
PR0_PRU0_GPIO6_MUX: U23.31(C5) ; off-sheet PR0_PRU0_GPIO6_MUX
PR0_PRU0_GPIO8: U1.G15(PR0_PRU0_GPIO8) U49.7(2A)
PR0_PRU0_GPIO8_MUX: U49.6(2B2) ; off-sheet PR0_PRU0_GPIO8_MUX
PR0_PRU0_GPIO9: U1.F17(PR0_PRU0_GPIO9) U49.9(3A)
PR0_PRU0_GPIO9_MUX: U49.10(3B2) ; off-sheet PR0_PRU0_GPIO9_MUX
PR0_PRU0_GPIO10: R286.1 U49.12(4A)
PR0_PRU0_GPIO10_MUX: U49.13(4B2) ; off-sheet PR0_PRU0_GPIO10_MUX
PR0_PRU0_GPIO10_R: R286.2 U1.G18(PR0_PRU0_GPIO10)
PR0_PRU0_GPIO11: R75.1 U23.11(A6)
PR0_PRU0_GPIO11_MUX: U23.28(C6) ; off-sheet PR0_PRU0_GPIO11_MUX
PR0_PRU0_GPIO11_R: R75.2 U1.M16(PR0_PRU0_GPIO11)
PR0_PRU0_GPIO12: R76.1 U23.12(A7)
PR0_PRU0_GPIO12_MUX: U23.26(C7) ; off-sheet PR0_PRU0_GPIO12_MUX
PR0_PRU0_GPIO12_R: R76.2 U1.M15(PR0_PRU0_GPIO12)
PR0_PRU0_GPIO13: R77.1 U23.13(A8)
PR0_PRU0_GPIO13_MUX: U23.24(C8) ; off-sheet PR0_PRU0_GPIO13_MUX
PR0_PRU0_GPIO13_R: R77.2 U1.H17(PR0_PRU0_GPIO13)
PR0_PRU0_GPIO14: R78.1 U23.14(A9)
PR0_PRU0_GPIO14_MUX: U23.22(C9) ; off-sheet PR0_PRU0_GPIO14_MUX
PR0_PRU0_GPIO14_R: R78.2 U1.H16(PR0_PRU0_GPIO14)
PR0_PRU0_GPIO15: R79.1 U23.15(A10)
PR0_PRU0_GPIO15_MUX: U23.20(C10) ; off-sheet PR0_PRU0_GPIO15_MUX
PR0_PRU0_GPIO15_R: R79.2 U1.L16(PR0_PRU0_GPIO15)
PR0_PRU0_GPIO16: R80.1 U23.16(A11)
PR0_PRU0_GPIO16_MUX: U23.18(C11) ; off-sheet PR0_PRU0_GPIO16_MUX
PR0_PRU0_GPIO16_R: R80.2 U1.H18(PR0_PRU0_GPIO16)
PRU/BP_MUX_EN_INV: R96.2 U46.4(Y) U49.15(~{OE}) ; off-sheet PRU/BP_MUX_EN_INV
RGMII1_ICSSM_MUX_SEL_GPIO105: U1.D17(PR0_PRU1_GPIO10) ; off-sheet RGMII1_ICSSM_MUX_SEL_GPIO105

Not connected (* = marked no-connect by the designer): U46 1(NC)*

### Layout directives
mark named IEP_EDIO_SYNC: AM263P_IEP0_EDC_SYNC_OUT0, AM263P_IEP0_EDC_SYNC_OUT0_R, AM263P_IEP0_EDIO_DATA_IN_OUT31, AM263P_IEP0_EDIO_DATA_IN_OUT31_R
mark named ETH2_ICSSM_CLK_DATA_CONTROL: PR0_PRU0_GPIO0, PR0_PRU0_GPIO1, PR0_PRU0_GPIO2, PR0_PRU0_GPIO3, PR0_PRU0_GPIO4, PR0_PRU0_GPIO5, PR0_PRU0_GPIO6, PR0_PRU0_GPIO8, PR0_PRU0_GPIO9, PR0_PRU0_GPIO10, PR0_PRU0_GPIO10_R, PR0_PRU0_GPIO11, PR0_PRU0_GPIO11_R, PR0_PRU0_GPIO12, PR0_PRU0_GPIO12_R, PR0_PRU0_GPIO13, PR0_PRU0_GPIO13_R, PR0_PRU0_GPIO14, PR0_PRU0_GPIO14_R, PR0_PRU0_GPIO15, PR0_PRU0_GPIO15_R, PR0_PRU0_GPIO16, PR0_PRU0_GPIO16_R
mark named ETH1_ICSSM_CLK_DATA_CONTROL: AM263P_ICSSM_MII1_RXD0, AM263P_ICSSM_MII1_RXD1, AM263P_ICSSM_MII1_RXD2, AM263P_ICSSM_MII1_RXD3, AM263P_ICSSM_MII1_RXDV, AM263P_ICSSM_MII1_RXER, AM263P_ICSSM_MII1_TXCLK, AM263P_ICSSM_MII1_TXCLK_R, AM263P_ICSSM_MII1_TXD0, AM263P_ICSSM_MII1_TXD0_R, AM263P_ICSSM_MII1_TXD1, AM263P_ICSSM_MII1_TXD1_R, AM263P_ICSSM_MII1_TXD2, AM263P_ICSSM_MII1_TXD2_R, AM263P_ICSSM_MII1_TXD3, AM263P_ICSSM_MII1_TXD3_R, AM263P_ICSSM_MII1_TXEN, AM263P_ICSSM_MII1_TXEN_R, AM263P_IEP0_EDIO_DATA_IN_OUT31_R, RGMII1_ICSSM_MUX_SEL_GPIO105
mark named MDIO_ICSSM: AM263P_PR0_MDIO0_MDC, AM263P_PR0_MDIO0_MDC_R, AM263P_PR0_MDIO0_MDIO, AM263P_PR0_MDIO0_MDIO_R
mark named ETH1_CLK_DATA_CONTROL: (no net found under the mark)

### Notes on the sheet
- AM263P PR0 PRU0 and PRU1
- ICSSM MDIO Pull-Up
- PR0_PRU0 PHY #2 / Boosterpack MUX
- (near U23) Note: TS3DDR MUX defaults
  - EN# pulled high - MUX disabled (default)
  - SEL pulled low - path A <-> B enabled (default)
- (near R287) MUX Default Pulls
- Note: SN74CB3Q3257 MUX defaults
  - OE# pulled high - MUX disabled (default)
  - S pulled low - path xA <-> xB1 enabled (default)
- MUX Decoupling

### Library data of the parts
C43 C111 C238 C239 = CMP-0006659-2: as C100 on sheet PROC171_AM263P_7_RGMII_MII
C248 = CMP-0007469-4: CAP, CERM, 0.1 uF, 100 V, +/- 10%, X7R, 0603; Manufacturer: MuRata; TaMin_C: -55°C; Polarized: N; SizeAreaWB_mm2: 4.68; Value1: Unknown; U/M: EA; Value: 0.1uF; TaMax_C: 125°C; SizeZ_mm: 1; SizeX_mm: 1.6; SizeY_mm: 0.8; SizeArea_mm2: 1.28; AEC Category: Q200
R71 R72 = CMP-0026696-1: as R61 on sheet PROC171_AM263P_7_RGMII_MII
R73 R74 = CMP-0042990-1: as R63 on sheet PROC171_AM263P_7_RGMII_MII
R75-R80 R87 R88 R286 = CMP-0026992-3: as R394 on sheet PROC171_AM263P_6_ePWM_eQEP_FSI
R81-R86 = CMP-0026880-3: as R9 on sheet PROC171_AM263P_6_ePWM_eQEP_FSI
R96 R289 R290 = CMP-0078193-1: as R397 on sheet PROC171_AM263P_6_ePWM_eQEP_FSI
R287 R288 = CMP-0026658-1: as R395 on sheet PROC171_AM263P_6_ePWM_eQEP_FSI
U1 = CMP-0001698-2: as U1 on sheet PROC171_AM263P_6_ePWM_eQEP_FSI
U23 = CMP-0093539-2: IC MUX/DEMUX DDR3 1:2 42WQFN; Manufacturer: Texas Instruments; TaMax_C: +85°C; TaMin_C: -40°C; On State Resistance: 8Ω; SizeZ_mm: 0.8mm; Min Supply Voltage: 3V; Standoff Height: 0mm; Max Supply Voltage: 3.6V; AEC Qualified: No; PositionCount: 12; -3Db Bandwith: 1.675GHz; Nominal Supply Current: 300uA; AEC Category: Q200
U46 = CMP-0051684-3: Single Inverter, DCK0005A, LARGE T&R; Manufacturer: Texas Instruments; Input Type: CMOS/TTL; Output Drive (IOL/IOH)(Max)(mA): 32/-32; Sub-Family: Inverting Buffer/Driver; VCC(Min)(V): 1.65; Bits(#): 1; Schmitt Trigger: No; Technology Family: LVC; Rating: Catalog; ICC @ Nom Voltage(Max)(mA): 0.01; tpd @ Nom Voltage(Max)(ns): 7.5,5.2,4.2,3.7; Voltage(Nom)(V): 1.8,2.5,3.3,5; F @ Nom Voltage(Max)(Mhz): 150; Output Type: CMOS; VCC(Max)(V): 5.5; Logic: Inverting; AEC Category: Q200; AEC Qualified: N; CompType: IC; SizeAreaWB_mm2: 9.3; SizeArea_mm2: 4.2; SizeX_mm: 2.1; SizeY_mm: 2.0; SizeZ_mm: 1.1
U49 = CMP-0076540-1: as U54 on sheet PROC171_AM263P_6_ePWM_eQEP_FSI

## Sheet PROC171_AM263P_9_SDFM.SchDoc
size 431 x 279 mm; Date: Not shown in title block; ApprovedBy: Not shown in title block; CheckedBy: Not shown in title block; Author: Not shown in title block; CompanyName: Not shown in title block; Engineer: Not shown in title block; Organization: Not shown in title block; Address1: Not shown in title block; Address2: Not shown in title block; Address3: Not shown in title block; Address4: Not shown in title block; DocumentNumber: 13; Revision: Use project parameter SCH_Rev; SheetNumber: 13; SheetTotal: 26; PageSetup: Record=PageOptions¦CenterHorizontal=True¦CenterVertical=True¦PrintScale=1.00¦XCorrection=1.00¦YCorrection=1.00¦PrintKind=0¦BorderSize=5000000¦LeftOffset=0¦BottomOffset=0¦Orientation=2¦PaperLength=1000¦PaperWidth=1000¦Scale=100¦PaperSource=15¦PrintQuality=600¦MediaType=1¦DitherType=10¦PaperKind=Letter¦PrintScaleMode=1

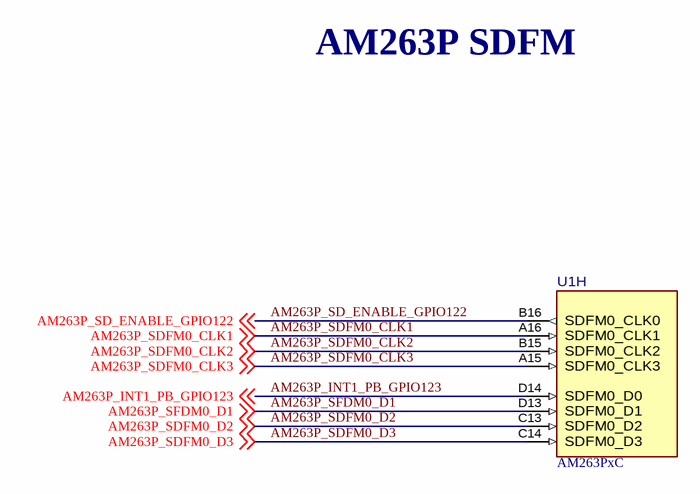
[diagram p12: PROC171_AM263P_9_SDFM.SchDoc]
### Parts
U1  AM263PxC  [ZCZ0324A-MFG]  (part H of 13)

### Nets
AM263P_INT1_PB_GPIO123: U1.D14(SDFM0_D0) ; off-sheet AM263P_INT1_PB_GPIO123
AM263P_SD_ENABLE_GPIO122: U1.B16(SDFM0_CLK0) ; off-sheet AM263P_SD_ENABLE_GPIO122
AM263P_SDFM0_CLK1: U1.A16(SDFM0_CLK1) ; off-sheet AM263P_SDFM0_CLK1
AM263P_SDFM0_CLK2: U1.B15(SDFM0_CLK2) ; off-sheet AM263P_SDFM0_CLK2
AM263P_SDFM0_CLK3: U1.A15(SDFM0_CLK3) ; off-sheet AM263P_SDFM0_CLK3
AM263P_SDFM0_D2: U1.C13(SDFM0_D2) ; off-sheet AM263P_SDFM0_D2
AM263P_SDFM0_D3: U1.C14(SDFM0_D3) ; off-sheet AM263P_SDFM0_D3
AM263P_SFDM0_D1: U1.D13(SDFM0_D1) ; off-sheet AM263P_SFDM0_D1

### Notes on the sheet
- AM263P SDFM

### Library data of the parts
U1 = CMP-0001698-2: as U1 on sheet PROC171_AM263P_6_ePWM_eQEP_FSI

## Sheet PROC171_Push_Buttons.SchDoc
size 431 x 279 mm; Date: Not shown in title block; ApprovedBy: Not shown in title block; CheckedBy: Not shown in title block; Author: Not shown in title block; CompanyName: Not shown in title block; Engineer: Not shown in title block; Organization: Not shown in title block; Address1: Not shown in title block; Address2: Not shown in title block; Address3: Not shown in title block; Address4: Not shown in title block; DocumentNumber: 15; Revision: Use project parameter SCH_Rev; SheetNumber: 15; SheetTotal: 26; PageSetup: Record=PageOptions¦CenterHorizontal=True¦CenterVertical=True¦PrintScale=1.00¦XCorrection=1.00¦YCorrection=1.00¦PrintKind=0¦BorderSize=5000000¦LeftOffset=0¦BottomOffset=0¦Orientation=2¦PaperLength=1000¦PaperWidth=1000¦Scale=100¦PaperSource=15¦PrintQuality=600¦MediaType=1¦DitherType=10¦PaperKind=Letter¦PrintScaleMode=1

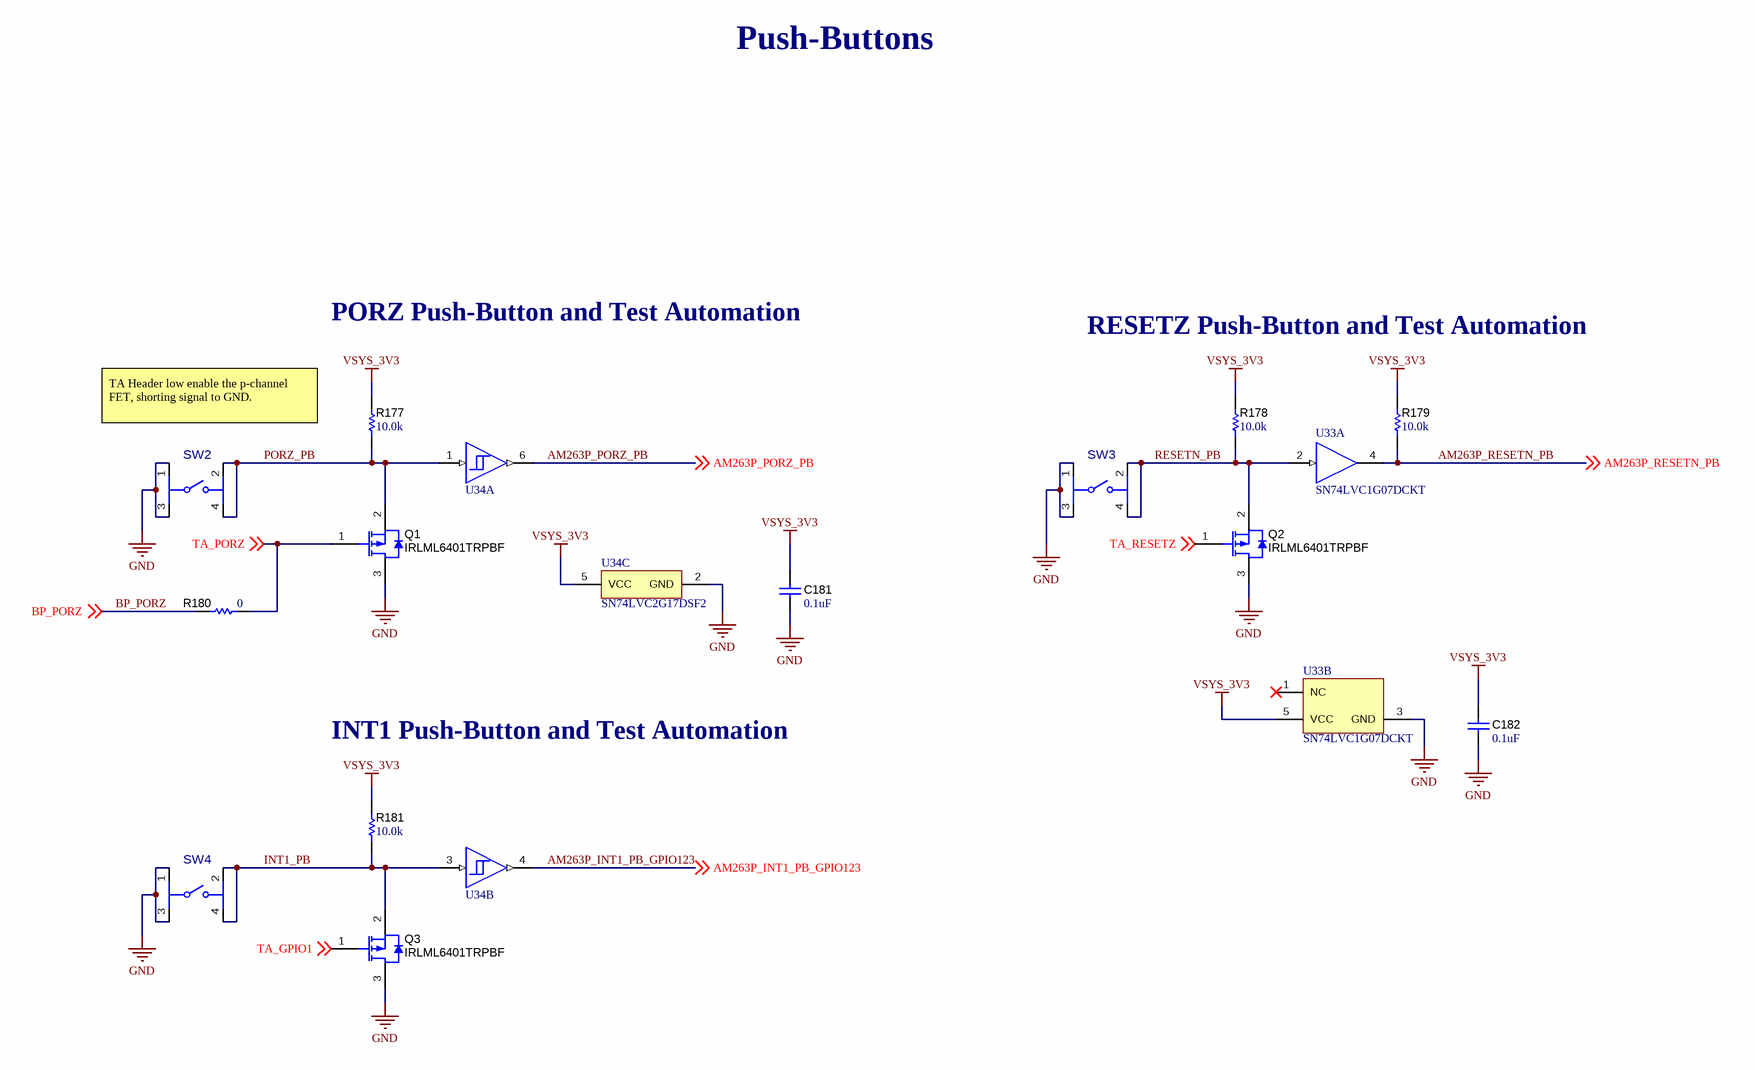
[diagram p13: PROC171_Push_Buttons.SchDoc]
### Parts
C181  ValueDisplayed: 0.1uF  [0402]  (hidden comment: GRM155R71E104KE14D)
C182  ValueDisplayed: 0.1uF  [0402]  (hidden comment: GRM155R71E104KE14D)
Q1  IRLML6401TRPBF  [SOT-23]
Q2  IRLML6401TRPBF  [SOT-23]
Q3  IRLML6401TRPBF  [SOT-23]
R177  ValueDisplayed: 10.0k  [0402]  (hidden comment: ERJ-2RKF1002X)
R178  ValueDisplayed: 10.0k  [0402]  (hidden comment: ERJ-2RKF1002X)
R179  ValueDisplayed: 10.0k  [0402]  (hidden comment: ERJ-2RKF1002X)
R180  ValueDisplayed: 0  [0402L]  (hidden comment: ERJ-2GE0R00X)
R181  ValueDisplayed: 10.0k  [0402]  (hidden comment: ERJ-2RKF1002X)
SW2  434351045816  [FP-434351045816_SMT_SW_4MM7_4MM5-MFG]  (value not drawn)
SW3  434351045816  [FP-434351045816_SMT_SW_4MM7_4MM5-MFG]  (value not drawn)
SW4  434351045816  [FP-434351045816_SMT_SW_4MM7_4MM5-MFG]  (value not drawn)
U33  SN74LVC1G07DCKT  [DCK0005A_N]  (parts A,B of 2)
U34  SN74LVC2G17DSF2  [DSF0006A]  (value not drawn)  (parts A,B,C of 3)

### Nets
GND: C181.1 C182.1 Q1.3(D) Q2.3(D) Q3.3(D) SW2.1 SW2.3 SW3.1 SW3.3 SW4.1 SW4.3 U33.3(GND) U34.2(GND)
VSYS_3V3: C181.2 C182.2 R177.2 R178.2 R179.2 R181.2 U33.5(VCC) U34.5(VCC)
AM263P_INT1_PB_GPIO123: U34.4(2Y) ; off-sheet AM263P_INT1_PB_GPIO123
AM263P_PORZ_PB: U34.6(1Y) ; off-sheet AM263P_PORZ_PB
AM263P_RESETN_PB: R179.1 U33.4(Y) ; off-sheet AM263P_RESETN_PB
BP_PORZ: R180.2 ; off-sheet BP_PORZ
INT1_PB: Q3.2(S) R181.1 SW4.2 SW4.4 U34.3(2A)
PORZ_PB: Q1.2(S) R177.1 SW2.2 SW2.4 U34.1(1A)
RESETN_PB: Q2.2(S) R178.1 SW3.2 SW3.4 U33.2(A)
TA_GPIO1: Q3.1(G) ; off-sheet TA_GPIO1
TA_PORZ: Q1.1(G) R180.1 ; off-sheet TA_PORZ
TA_RESETZ: Q2.1(G) ; off-sheet TA_RESETZ

Not connected (* = marked no-connect by the designer): U33 1(NC)*

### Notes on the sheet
- Push-Buttons
- PORZ Push-Button and Test Automation
- RESETZ Push-Button and Test Automation
- TA Header low enable the p-channel FET, shorting signal to GND.
- INT1 Push-Button and Test Automation

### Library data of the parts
C181 C182 = CMP-0006659-2: as C100 on sheet PROC171_AM263P_7_RGMII_MII
Q1-Q3 = CMP-0078819-2: MOSFET, P-CH, -12 V, -4.3 A, SOT-23; Alternate Manufacturer: None; Manufacturer: Infineon Technologies; SizeY_mm: 3; ChMode: Enhancement; SizeX_mm: 2.5; QgTyp_nC: 10; ChType: P; AEC Qualified: N; Value2: 10 nC; SizeZ_mm: 1.1; Green_Lifecycle: Active; Vgs_V: -8V; SizeArea_mm2: 7.5; Value: -12V; IdsMax_A: -4.3A; SizeAreaWB_mm2: 14; AEC Category: Q101; Value1: 0.05 ohm; Rdson45_ohm: 50m; Green_REACh: Passed
R177-R179 R181 = CMP-0026658-1: as R395 on sheet PROC171_AM263P_6_ePWM_eQEP_FSI
R180 = CMP-0026992-3: RES, 0, 5%, 0.1 W, AEC-Q200 Grade 0, 0402; Manufacturer: Panasonic; Power_W: 100mW; TempCo: 600 ppm/C; Value_Code: 0000; Value: 0; EIA_Code: E24; SizeX_mm: 1; SizeY_mm: 0.5; SizeZ_mm: 0.6; Value2: 0.1W; AEC Qualified: Y; VDC_V: 50V; AEC Category: Q200; SizeAreaWB_mm2: 3
SW2-SW4 = CMP-0093456-1: Tactile Switch SPST-NO Side Actuated Surface Mount, Right Angle; Manufacturer: Wurth Electronics; Operating Force: 160gf; SizeZ_mm: 1.75mm; AEC Qualified: No; Electromechanical Life: 200000Cycles; VDC_V: 12V; Contact Current Rating: 50mA; Coil Resistance_ohm: 100mΩ
U33 = CMP-0051392-2: Single Buffer/Driver With Open-Drain Output, DCK0005A, SMALL T&R; Manufacturer: Texas Instruments; Input Type: CMOS/TTL; F @ Nom Voltage(Max)(Mhz): 150; Technology Family: LVC; VCC(Min)(V): 1.65; 3-State Output: No; Rating: Catalog; Logic: True; ICC @ Nom Voltage(Max)(mA): 0.01; Bits(#): 1; VCC(Max)(V): 5.5; Sub-Family: Non-Inverting Buffer/Driver; Output Drive (IOL/IOH)(Max)(mA): 32/-32; tpd @ Nom Voltage(Max)(ns): 8.6,6,4.7,4; Output Type: CMOS; Voltage(Nom)(V): 1.8,2.5,3.3,5; AEC Category: Q200; AEC Qualified: N; CompType: IC; SizeAreaWB_mm2: 9.3; SizeArea_mm2: 4.2; SizeX_mm: 2.1; SizeY_mm: 2.0; SizeZ_mm: 1.1
U34 = CMP-0051904-4: Dual Schmitt-Trigger Buffer, DSF0006A, LARGE T&R; Manufacturer: Texas Instruments; Output Type: CMOS; Bits(#): 2; Input Type: CMOS/TTL; Technology Family: LVC; Schmitt Trigger: Yes; 3-State Output: No; VCC(Max)(V): 5.5; Sub-Family: Non-Inverting Buffer/Driver; Rating: Catalog; Output Drive (IOL/IOH)(Max)(mA): 32/-32; ICC @ Nom Voltage(Max)(mA): 0.01; VCC(Min)(V): 1.65; F @ Nom Voltage(Max)(Mhz): 150; Logic: True; Voltage(Nom)(V): 1.8,2.5,3.3,5; tpd @ Nom Voltage(Max)(ns): 9.3,5.7,5.4,4.3

## Sheet PROC171_Test_Automation.SchDoc
size 431 x 279 mm; Date: Not shown in title block; ApprovedBy: Not shown in title block; CheckedBy: Not shown in title block; Author: Not shown in title block; CompanyName: Not shown in title block; Engineer: Not shown in title block; Organization: Not shown in title block; Address1: Not shown in title block; Address2: Not shown in title block; Address3: Not shown in title block; Address4: Not shown in title block; DocumentNumber: 14; Revision: Use project parameter SCH_Rev; SheetNumber: 14; SheetTotal: 26; PageSetup: Record=PageOptions¦CenterHorizontal=True¦CenterVertical=True¦PrintScale=1.00¦XCorrection=1.00¦YCorrection=1.00¦PrintKind=0¦BorderSize=5000000¦LeftOffset=0¦BottomOffset=0¦Orientation=2¦PaperLength=1000¦PaperWidth=1000¦Scale=100¦PaperSource=15¦PrintQuality=600¦MediaType=1¦DitherType=10¦PaperKind=Letter¦PrintScaleMode=1

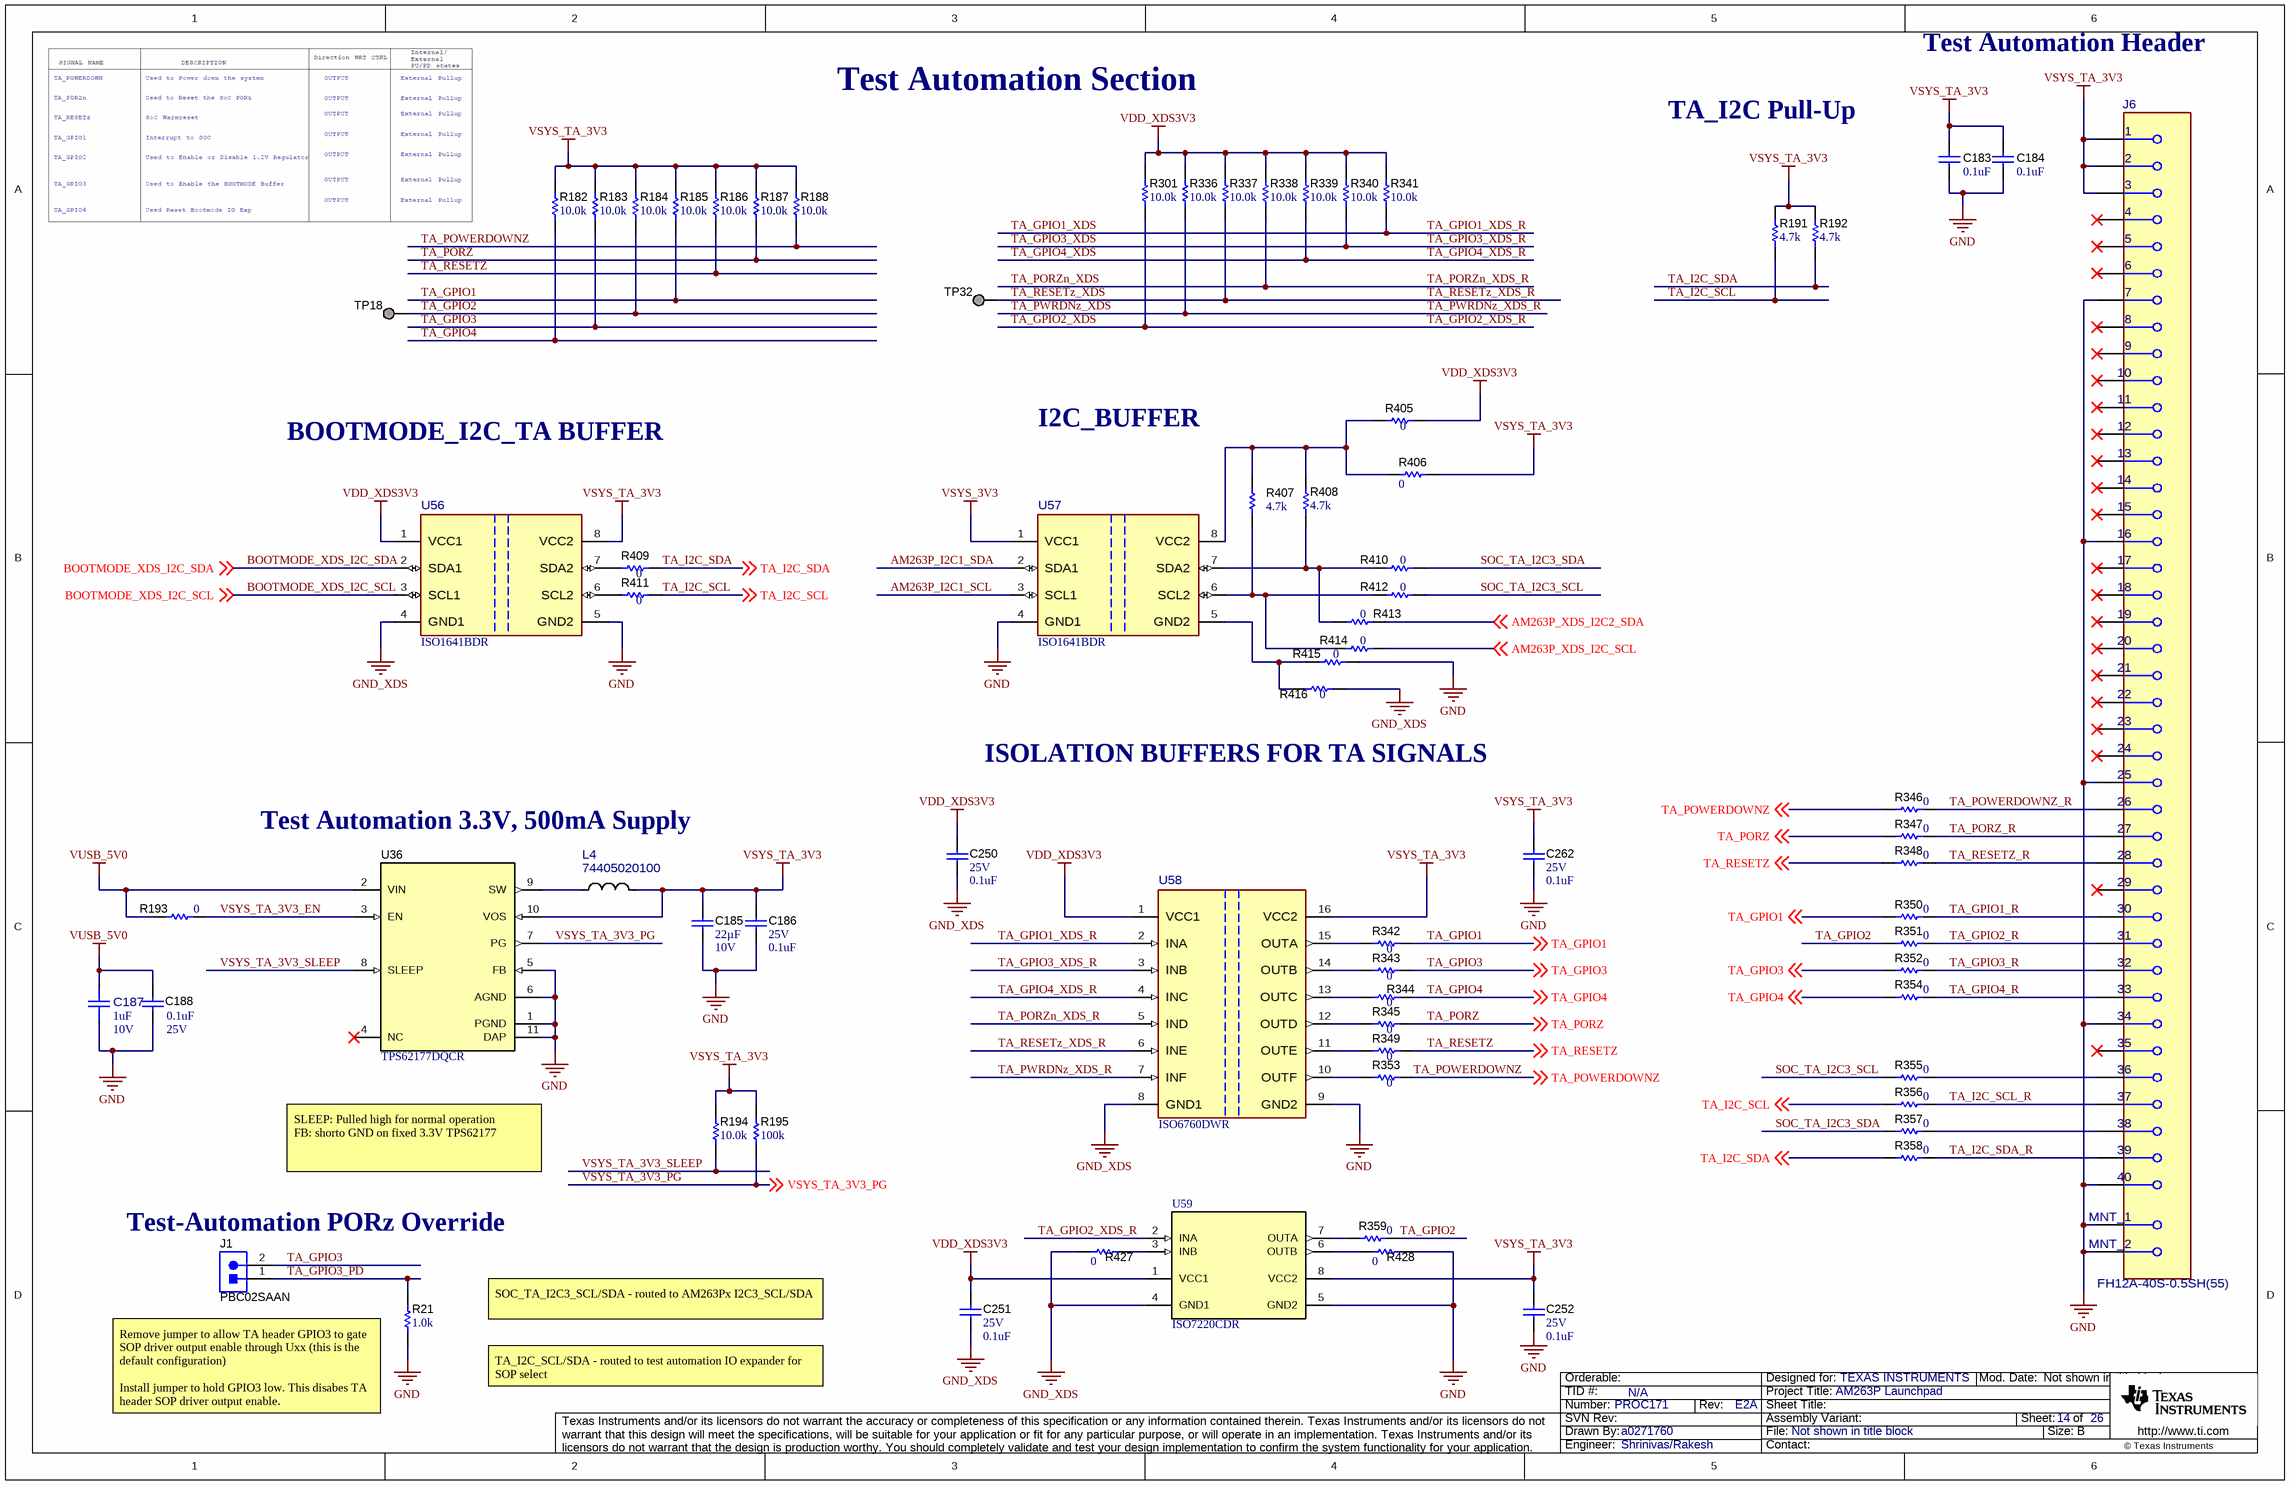
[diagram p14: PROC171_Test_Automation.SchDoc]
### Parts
C183  ValueDisplayed: 0.1uF  [0402]  (hidden comment: GRM155R71E104KE14D)
C184  ValueDisplayed: 0.1uF  [0402]  (hidden comment: GRM155R71E104KE14D)
C185  Cap_F: 22µF  VDC_V: 10V  [0805_HV]  (hidden comment: GRM21BZ71A226ME15L)
C186  VDC_V: 25V  ValueDisplayed: 0.1uF  [0402]  (hidden comment: GRM155R71E104KE14D)
C187  ValueDisplayed: 1uF  VDC_V: 10V  [FP-GRM155C71A105KE11D_0402-MFG]  (hidden comment: GRM155C71A105KE11D)
C188  VDC_V: 25V  ValueDisplayed: 0.1uF  [0402]  (hidden comment: GRM155R71E104KE14D)
C250  VDC_V: 25V  ValueDisplayed: 0.1uF  [0402]  (hidden comment: GRM155R71E104KE14D)
C251  VDC_V: 25V  ValueDisplayed: 0.1uF  [0402]  (hidden comment: GRM155R71E104KE14D)
C252  VDC_V: 25V  ValueDisplayed: 0.1uF  [0402]  (hidden comment: GRM155R71E104KE14D)
C262  VDC_V: 25V  ValueDisplayed: 0.1uF  [0402]  (hidden comment: GRM155R71E104KE14D)
J1  PBC02SAAN  [Sullins_PBC02SAAN]
J6  FH12A-40S-0.5SH(55)  [FP-FH12A-40S-0.5SH(55)_FFC40-MFG]
L4  74405020100  [FP-74405020100_SMT_IND_2MM0_1MM6-MFG]
R21  ValueDisplayed: 1.0k  [0402]  (hidden comment: ERJ-2GEJ102X)
R182  ValueDisplayed: 10.0k  [0402]  (hidden comment: ERJ-2RKF1002X)
R183  ValueDisplayed: 10.0k  [0402]  (hidden comment: ERJ-2RKF1002X)
R184  ValueDisplayed: 10.0k  [0402]  (hidden comment: ERJ-2RKF1002X)
R185  ValueDisplayed: 10.0k  [0402]  (hidden comment: ERJ-2RKF1002X)
R186  ValueDisplayed: 10.0k  [0402]  (hidden comment: ERJ-2RKF1002X)
R187  ValueDisplayed: 10.0k  [0402]  (hidden comment: ERJ-2RKF1002X)
R188  ValueDisplayed: 10.0k  [0402]  (hidden comment: ERJ-2RKF1002X)
R191  ValueDisplayed: 4.7k  [0402]  (hidden comment: CRCW04024K70JNED)
R192  ValueDisplayed: 4.7k  [0402]  (hidden comment: CRCW04024K70JNED)
R193  ValueDisplayed: 0  [0402L]  (hidden comment: ERJ-2GE0R00X)
R194  ValueDisplayed: 10.0k  [0402]  (hidden comment: ERJ-2RKF1002X)
R195  ValueDisplayed: 100k  [0402]  (hidden comment: ERJ-2RKF1003X)
R301  ValueDisplayed: 10.0k  [0402]  (hidden comment: ERJ-2RKF1002X)
R336  ValueDisplayed: 10.0k  [0402]  (hidden comment: ERJ-2RKF1002X)
R337  ValueDisplayed: 10.0k  [0402]  (hidden comment: ERJ-2RKF1002X)
R338  ValueDisplayed: 10.0k  [0402]  (hidden comment: ERJ-2RKF1002X)
R339  ValueDisplayed: 10.0k  [0402]  (hidden comment: ERJ-2RKF1002X)
R340  ValueDisplayed: 10.0k  [0402]  (hidden comment: ERJ-2RKF1002X)
R341  ValueDisplayed: 10.0k  [0402]  (hidden comment: ERJ-2RKF1002X)
R342  ValueDisplayed: 0  [0402]  (hidden comment: ERJ-2GE0R00X)
R343  ValueDisplayed: 0  [0402]  (hidden comment: ERJ-2GE0R00X)
R344  ValueDisplayed: 0  [0402]  (hidden comment: ERJ-2GE0R00X)
R345  ValueDisplayed: 0  [0402]  (hidden comment: ERJ-2GE0R00X)
R346  ValueDisplayed: 0  [0402]  (hidden comment: ERJ-2GE0R00X)
R347  ValueDisplayed: 0  [0402]  (hidden comment: ERJ-2GE0R00X)
R348  ValueDisplayed: 0  [0402]  (hidden comment: ERJ-2GE0R00X)
R349  ValueDisplayed: 0  [0402]  (hidden comment: ERJ-2GE0R00X)
R350  ValueDisplayed: 0  [0402]  (hidden comment: ERJ-2GE0R00X)
R351  ValueDisplayed: 0  [0402]  (hidden comment: ERJ-2GE0R00X)
R352  ValueDisplayed: 0  [0402]  (hidden comment: ERJ-2GE0R00X)
R353  ValueDisplayed: 0  [0402]  (hidden comment: ERJ-2GE0R00X)
R354  ValueDisplayed: 0  [0402]  (hidden comment: ERJ-2GE0R00X)
R355  ValueDisplayed: 0  [0402]  (hidden comment: ERJ-2GE0R00X)
R356  ValueDisplayed: 0  [0402]  (hidden comment: ERJ-2GE0R00X)
R357  ValueDisplayed: 0  [0402]  (hidden comment: ERJ-2GE0R00X)
R358  ValueDisplayed: 0  [0402]  (hidden comment: ERJ-2GE0R00X)
R359  ValueDisplayed: 0  [0402]  (hidden comment: ERJ-2GE0R00X)
R405  ValueDisplayed: 0  [0402]  (hidden comment: ERJ-2GE0R00X)
R406  ValueDisplayed: 0  [1210]  (hidden comment: CRCW12100000Z0EAHP)
R407  ValueDisplayed: 4.7k  [0402]  (hidden comment: CRCW04024K70JNED)
R408  ValueDisplayed: 4.7k  [0402]  (hidden comment: CRCW04024K70JNED)
R409  ValueDisplayed: 0  [0402]  (hidden comment: ERJ-2GE0R00X)
R410  ValueDisplayed: 0  [1210]  (hidden comment: CRCW12100000Z0EAHP)
R411  ValueDisplayed: 0  [0402]  (hidden comment: ERJ-2GE0R00X)
R412  ValueDisplayed: 0  [1210]  (hidden comment: CRCW12100000Z0EAHP)
R413  ValueDisplayed: 0  [0402]  (hidden comment: ERJ-2GE0R00X)
R414  ValueDisplayed: 0  [0402]  (hidden comment: ERJ-2GE0R00X)
R415  ValueDisplayed: 0  [1210]  (hidden comment: CRCW12100000Z0EAHP)
R416  ValueDisplayed: 0  [0402]  (hidden comment: ERJ-2GE0R00X)
R427  ValueDisplayed: 0  [0402]  (hidden comment: ERJ-2GE0R00X)
R428  ValueDisplayed: 0  [0402]  (hidden comment: ERJ-2GE0R00X)
TP18  TESTPOINT  [TP_25MIL-SMT]  (value not drawn)  (no BOM)
TP32  TESTPOINT  [TP_25MIL-SMT]  (value not drawn)  (no BOM)
U36  TPS62177DQCR  [DQC0010A]
U56  ISO1641BDR  [D0008A-MFG]
U57  ISO1641BDR  [D0008A-MFG]
U58  ISO6760DWR  [DW0016A-MFG]
U59  ISO7220CDR  [D0008B_N]

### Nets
GND: C183.1 C184.1 C185.2 C186.2 C187.1 C188.2 C252.2 C262.2 J6.7 J6.16 J6.25 J6.34 J6.40 J6.41(MNT_1) J6.42(MNT_2) R21.1 R415.2 R428.1 U36.1(PGND) U36.5(FB) U36.6(AGND) U36.11(DAP) U56.5(GND2) U57.4(GND1) U58.9(GND2) U59.5(GND2)
GND_XDS: C250.2 C251.2 R416.2 R427.2 U56.4(GND1) U58.8(GND1) U59.4(GND1)
VDD_XDS3V3: C250.1 C251.1 R301.1 R336.1 R337.1 R338.1 R339.1 R340.1 R341.1 R405.2 U56.1(VCC1) U58.1(VCC1) U59.1(VCC1)
VSYS_3V3: U57.1(VCC1)
VSYS_TA_3V3: C183.2 C184.2 C185.1 C186.1 C252.1 C262.1 J6.1 J6.2 J6.3 L4.2 R182.1 R183.1 R184.1 R185.1 R186.1 R187.1 R188.1 R191.2 R192.2 R194.2 R195.2 R406.2 U36.10(VOS) U56.8(VCC2) U58.16(VCC2) U59.8(VCC2)
VUSB_5V0: C187.2 C188.1 R193.2 U36.2(VIN)
AM263P_I2C1_SCL: U57.3(SCL1)
AM263P_I2C1_SDA: U57.2(SDA1)
AM263P_XDS_I2C2_SDA: R413.2 ; off-sheet AM263P_XDS_I2C2_SDA
AM263P_XDS_I2C_SCL: R414.2 ; off-sheet AM263P_XDS_I2C_SCL
BOOTMODE_XDS_I2C_SCL: U56.3(SCL1) ; off-sheet BOOTMODE_XDS_I2C_SCL
BOOTMODE_XDS_I2C_SDA: U56.2(SDA1) ; off-sheet BOOTMODE_XDS_I2C_SDA
SOC_TA_I2C3_SCL: R355.1 R412.2
SOC_TA_I2C3_SDA: R357.1 R410.2
TA_GPIO1: R185.2 R342.2 R350.1 ; off-sheet TA_GPIO1
TA_GPIO1_R: J6.30 R350.2
TA_GPIO1_XDS: R341.2 U58.2(INA)  [also labelled TA_GPIO1_XDS_R]
TA_GPIO2: R184.2 R351.1 R359.2 TP18.1
TA_GPIO2_R: J6.31 R351.2
TA_GPIO2_XDS: R301.2 U59.2(INA)  [also labelled TA_GPIO2_XDS_R]
TA_GPIO3: J1.2 R183.2 R343.2 R352.1 ; off-sheet TA_GPIO3
TA_GPIO3_PD: J1.1 R21.2
TA_GPIO3_R: J6.32 R352.2
TA_GPIO3_XDS: R340.2 U58.3(INB)  [also labelled TA_GPIO3_XDS_R]
TA_GPIO4: R182.2 R344.2 R354.1 ; off-sheet TA_GPIO4
TA_GPIO4_R: J6.33 R354.2
TA_GPIO4_XDS: R339.2 U58.4(INC)  [also labelled TA_GPIO4_XDS_R]
TA_I2C_SCL: R191.1 R356.1 R411.2 ; off-sheet TA_I2C_SCL
TA_I2C_SCL_R: J6.37 R356.2
TA_I2C_SDA: R192.1 R358.1 R409.2 ; off-sheet TA_I2C_SDA
TA_I2C_SDA_R: J6.39 R358.2
TA_PORZ: R187.2 R345.2 R347.1 ; off-sheet TA_PORZ
TA_PORZ_R: J6.27 R347.2
TA_PORZn_XDS: R338.2 U58.5(IND)  [also labelled TA_PORZn_XDS_R]
TA_POWERDOWNZ: R188.2 R346.1 R353.2 ; off-sheet TA_POWERDOWNZ
TA_POWERDOWNZ_R: J6.26 R346.2
TA_PWRDNz_XDS: R336.2 U58.7(INF)  [also labelled TA_PWRDNz_XDS_R]
TA_RESETZ: R186.2 R348.1 R349.2 ; off-sheet TA_RESETZ
TA_RESETZ_R: J6.28 R348.2
TA_RESETz_XDS: R337.2 TP32.1 U58.6(INE)  [also labelled TA_RESETz_XDS_R]
VSYS_TA_3V3_EN: R193.1 U36.3(EN)
VSYS_TA_3V3_PG: R195.1 U36.7(PG) ; off-sheet VSYS_TA_3V3_PG
VSYS_TA_3V3_SLEEP: R194.1 U36.8(SLEEP)
NetJ6_36: J6.36 R355.2
NetJ6_38: J6.38 R357.2
NetL4_1: L4.1 U36.9(SW)
NetR342_1: R342.1 U58.15(OUTA)
NetR343_1: R343.1 U58.14(OUTB)
NetR344_1: R344.1 U58.13(OUTC)
NetR345_1: R345.1 U58.12(OUTD)
NetR349_1: R349.1 U58.11(OUTE)
NetR353_1: R353.1 U58.10(OUTF)
NetR359_1: R359.1 U59.7(OUTA)
NetR405_1: R405.1 R406.1 R407.2 R408.2 U57.8(VCC2)
NetR407_1: R407.1 R412.1 R414.1 U57.6(SCL2)
NetR408_1: R408.1 R410.1 R413.1 U57.7(SDA2)
NetR409_1: R409.1 U56.7(SDA2)
NetR411_1: R411.1 U56.6(SCL2)
NetR415_1: R415.1 R416.1 U57.5(GND2)
NetR427_1: R427.1 U59.3(INB)
NetR428_2: R428.2 U59.6(OUTB)

Not connected (* = marked no-connect by the designer): J6 4* 5* 6* 8* 9* 10* 11* 12* 13* 14* 15* 17* 18* 19* 20* 21* 22* 23* 24* 29* 35*; U36 4(NC)*

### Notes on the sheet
- Test Automation Section
- Test Automation Header
- TA_I2C Pull-Up
- I2C_BUFFER
- BOOTMODE_I2C_TA BUFFER
- ISOLATION BUFFERS FOR TA SIGNALS
- Test Automation 3.3V, 500mA Supply
- SLEEP: Pulled high for normal operation
  FB: shorto GND on fixed 3.3V TPS62177
- (near J1) Test-Automation PORz Override
- SOC_TA_I2C3_SCL/SDA - routed to AM263Px I2C3_SCL/SDA
- Remove jumper to allow TA header GPIO3 to gate SOP driver output enable through Uxx (this is the default configuration)
  Install jumper to hold GPIO3 low. This disabes TA header SOP driver output enable.
- TA_I2C_SCL/SDA - routed to test automation IO expander for SOP select

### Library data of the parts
C183 C184 = CMP-0006659-2: as C100 on sheet PROC171_AM263P_7_RGMII_MII
C185 = CMP-0008377-2: CAP, CERM, 22 uF, 10 V, +/- 20%, X7R, 0805; Manufacturer: MuRata; SizeY_mm: 1.25; Cap_Case: 0805; SizeArea_mm2: 2.5; AEC Qualified: N; AEC Category: Q200; ValueDisplayed: 22uF; TaMin_C: -55°C; SizeAreaWB_mm2: 6.75; Value1: Unknown; U/M: EA; Value: 22uF; TaMax_C: 125°C; SizeZ_mm: 1.45; SizeX_mm: 2
C186 C188 C250-C252 C262 = CMP-0006659-2: CAP, CERM, 0.1 uF, 25 V, +/- 10%, X7R, 0402; Manufacturer: MuRata; TaMin_C: -55°C; Polarized: N; SizeAreaWB_mm2: 3; Value1: Unknown; U/M: EA; Value: 0.1uF; TaMax_C: 125°C; SizeZ_mm: 0.6; SizeX_mm: 1; SizeY_mm: 0.5; Cap_F: 100nF; AEC Category: Q200
C187 = CMP-0035346-1: 1µF ±10% 10V Ceramic Capacitor X7S 0402 (1005 Metric); Manufacturer: Murata; AEC Qualified: No; SizeZ_mm: 0.6mm; TempCo: 22%
J1 = CMP-0054566-1: Header, 100mil, 2x1, Gold, TH; Manufacturer: Sullins Connector Solutions; CNHeader: TRUE; Current_A: 3A; Green_Lifecycle: Active; Shrouded: N; Gender: Male; Green_REACh: Passed; Voltage_V: 1.8kV; Row_Count: 1; Pitch_mm: 2.54; CT: FALSE; Cert_UL: Y
J6 = CMP-0093156-1: Manufacturer: Hirose; Is Female: yes; ContactFinish: Gold,Nickel; Current_A: 500mA; DUT-Pitch_mm: 0.5mm; Voltage_V: 50V; SizeZ_mm: 3.6mm; Conn Gender: Female; Conn Orientation: Horizontal; AEC Qualified: No
L4 = CMP-0078538-1: 10µH Semi-Shielded Wirewound Inductor 580mA 816 mOhm Max Nonstandard; Manufacturer: Wurth Electronics; Symbol Name: SYM-74405020100; Material: Ferrite; SizeZ_mm: 1mm; Isat: 0.95A; AEC Qualified: No; Irms: 0.58A
R21 = CMP-0078193-1: as R397 on sheet PROC171_AM263P_6_ePWM_eQEP_FSI
R182-R188 R194 R301 R336-R341 = CMP-0026658-1: as R395 on sheet PROC171_AM263P_6_ePWM_eQEP_FSI
R191 R192 R407 R408 = CMP-0026938-5: as R55 on sheet PROC171_AM263P_6_ePWM_eQEP_FSI
R193 R342-R359 R405 R409 R411 R413 R414 R416 R427 R428 = CMP-0026992-3: as R180 on sheet PROC171_Push_Buttons
R195 = CMP-0026659-2: RES, 100 k, 1%, 0.1 W, 0402; Manufacturer: Panasonic; U/M: EA; Value2: 0.1W; EIA_Code: E96; Value: 100k; SizeArea_mm2: 0.5; TempCo: 100 ppm/C; SizeZ_mm: 0.6; AEC Category: Q200; VDC_V: 50V; Power_W: 100mW; AEC Grade: 0; SizeX_mm: 1; AEC Qualified: Yes
R406 R410 R412 R415 = CMP-0015017-3: RES, 0, 1%, 0.75 W, AEC-Q200 Grade 0, 1210; Manufacturer: Vishay-Dale; Power_W: 750mW; TempCo: ppm/C; SizeAreaWB_mm2: 14.7; Value: 0; SizeX_mm: 3.2; SizeY_mm: 2.5; SizeZ_mm: 1.35; Value2: 0.75W; SizeArea_mm2: 8; AEC Qualified: Y; AEC Category: Q200
TP18 TP32 = CMP-0078143-3: TEST POINT.  No entry in BOM.
U36 = CMP-0067107-3: 28V, 0.5A Step-Down Converter with SNOOZE Mode, DQC0010A (WSON-10); Alternate PartNumber: TPS62177DQCT; Manufacturer: Texas Instruments; SizeZ_mm: 0.8; SizeX_mm: 2.0; SizeY_mm: 3.0; SizeArea_mm2: 6.0; CompType: IC; SizeAreaWB_mm2: 12.0
U56 U57 = CMP-0031336-1: Hot-swappable, robust-EMC bidirectional I2C isolator with unidirectional clock 8-SOIC -40 to 125; Manufacturer: Texas Instruments; SizeZ_mm: 1.75mm; AEC Qualified: No; Max Supply Voltage: 5.5V; Min Supply Voltage: 2.25V; Standoff Height: 0.11mm; TaMax_C: +125°C; TaMin_C: -40°C; TJmax_C: +150°C
U58 = CMP-0096103-1: General purpose, 50-Mbps, six-channel (6/0) digital isolator 16-SOIC -40 to 125; Manufacturer: Texas Instruments; AEC Qualified: No; Standoff Height: 0.1mm; Min Supply Voltage: 1.71V; TaMin_C: -40°C; TaMax_C: +125°C; TJmax_C: +150°C; Interface: LVCMOS; SizeZ_mm: 2.65mm; Max Supply Voltage: 5.5V
U59 = CMP-0029369-1: 25 Mbps Dual Channels, 2 / 0, Digital Isolator, 3.3 V / 5 V, -40 to +125 degC, 8-pin SOIC (D), Green (RoHS & no Sb/Br); Manufacturer: Texas Instruments; Supply Voltage(s)(V): 3.3, 5; Prop Delay(Max)(ns): 42; Insulation Rating(VRMS): 2500; Datarate(Mbps): 25; TTL/CMOS Input Threshold: TTL; Rating: Catalog; Input Noise Filter: Yes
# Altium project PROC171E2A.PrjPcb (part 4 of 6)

## Sheet PROC171_Ehernet_PHY_1.SchDoc
size 431 x 279 mm; Date: Not shown in title block; ApprovedBy: Not shown in title block; CheckedBy: Not shown in title block; Author: Not shown in title block; CompanyName: Not shown in title block; Engineer: Not shown in title block; Organization: Not shown in title block; Address1: Not shown in title block; Address2: Not shown in title block; Address3: Not shown in title block; Address4: Not shown in title block; DocumentNumber: 16; Revision: Use project parameter SCH_Rev; SheetNumber: 16; SheetTotal: 26; PageSetup: Record=PageOptions¦CenterHorizontal=True¦CenterVertical=True¦PrintScale=1.00¦XCorrection=1.00¦YCorrection=1.00¦PrintKind=0¦BorderSize=5000000¦LeftOffset=0¦BottomOffset=0¦Orientation=2¦PaperLength=1000¦PaperWidth=1000¦Scale=100¦PaperSource=15¦PrintQuality=600¦MediaType=1¦DitherType=10¦PaperKind=Letter¦PrintScaleMode=1

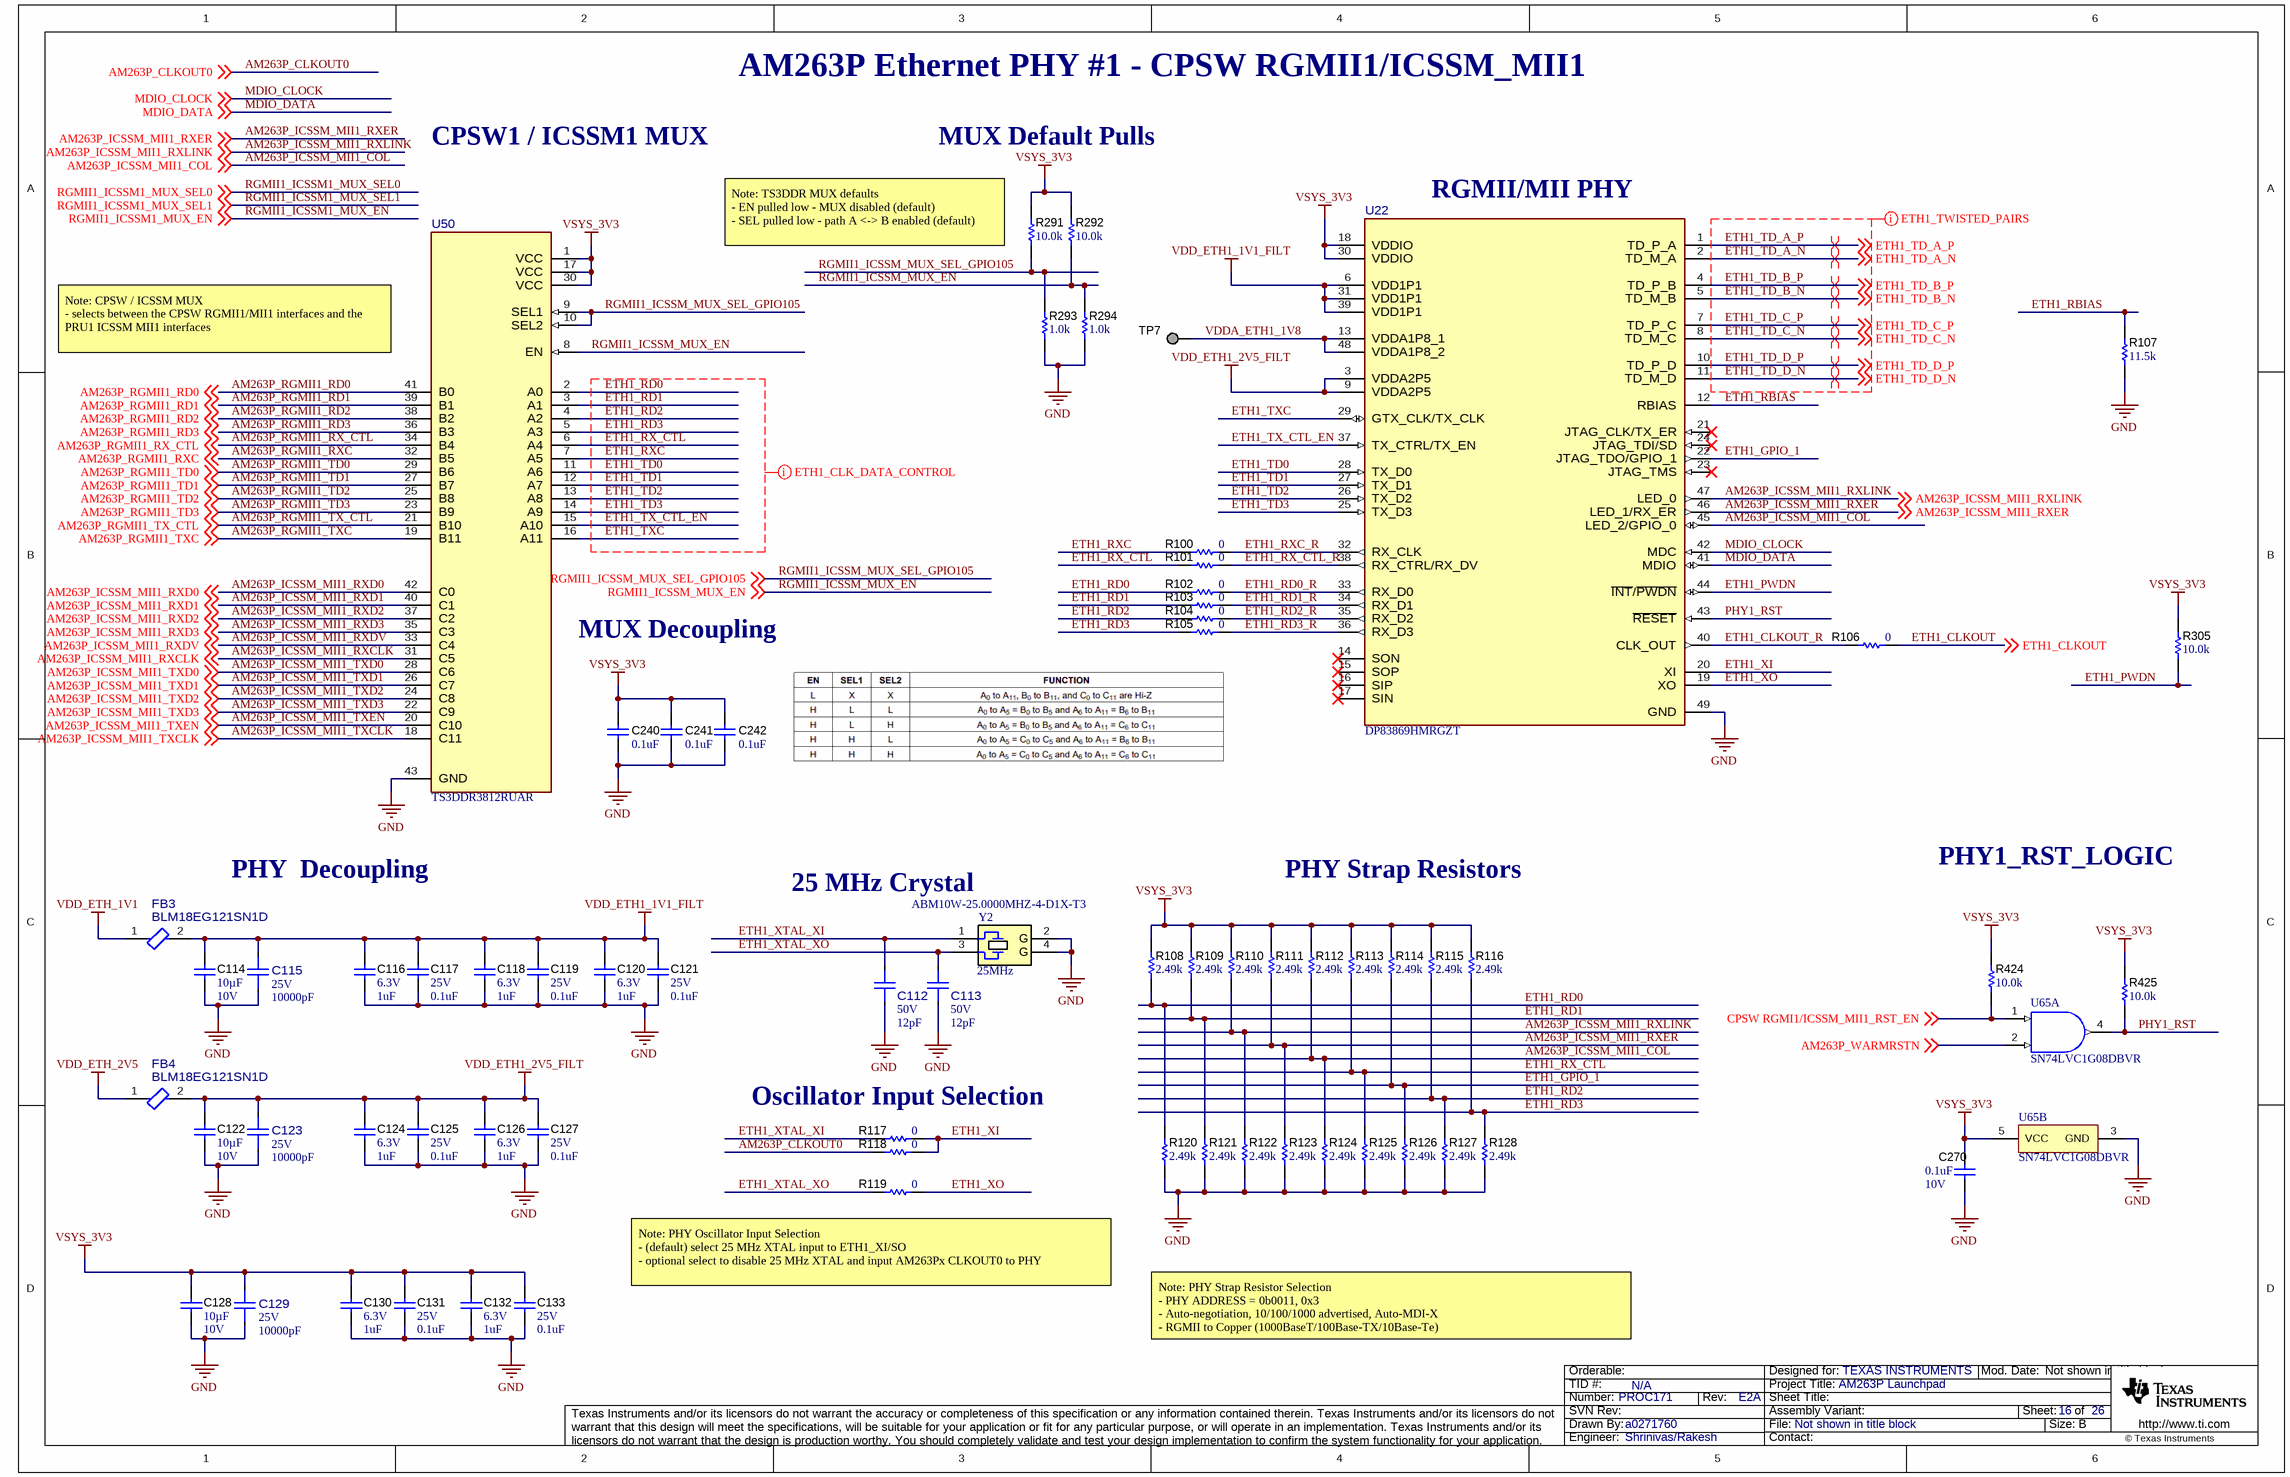
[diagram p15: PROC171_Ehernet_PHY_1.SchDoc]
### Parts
C112  VDC_V: 50V  ValueDisplayed: 12pF  [FP-GJM1555C1H120JB01D_0402-MFG]  (hidden comment: GJM1555C1H120JB01D)
C113  VDC_V: 50V  ValueDisplayed: 12pF  [FP-GJM1555C1H120JB01D_0402-MFG]  (hidden comment: GJM1555C1H120JB01D)
C114  Cap_F: 10µF  VDC_V: 10V  [0603]  (hidden comment: GRM188Z71A106MA73D)
C115  VDC_V: 25V  ValueDisplayed: 10000pF  [FP-GRM1555C1E103JE01D_0402-MFG]  (hidden comment: GRM1555C1E103JE01D)
C116  VDC_V: 6.3V  ValueDisplayed: 1uF  [0402]  (hidden comment: GRM155R70J105MA12D)
C117  VDC_V: 25V  ValueDisplayed: 0.1uF  [0402]  (hidden comment: GRM155R71E104KE14D)
C118  VDC_V: 6.3V  ValueDisplayed: 1uF  [0402]  (hidden comment: GRM155R70J105MA12D)
C119  VDC_V: 25V  ValueDisplayed: 0.1uF  [0402]  (hidden comment: GRM155R71E104KE14D)
C120  VDC_V: 6.3V  ValueDisplayed: 1uF  [0402]  (hidden comment: GRM155R70J105MA12D)
C121  VDC_V: 25V  ValueDisplayed: 0.1uF  [0402]  (hidden comment: GRM155R71E104KE14D)
C122  Cap_F: 10µF  VDC_V: 10V  [0603]  (hidden comment: GRM188Z71A106MA73D)
C123  VDC_V: 25V  ValueDisplayed: 10000pF  [FP-GRM1555C1E103JE01D_0402-MFG]  (hidden comment: GRM1555C1E103JE01D)
C124  VDC_V: 6.3V  ValueDisplayed: 1uF  [0402]  (hidden comment: GRM155R70J105MA12D)
C125  VDC_V: 25V  ValueDisplayed: 0.1uF  [0402]  (hidden comment: GRM155R71E104KE14D)
C126  VDC_V: 6.3V  ValueDisplayed: 1uF  [0402]  (hidden comment: GRM155R70J105MA12D)
C127  VDC_V: 25V  ValueDisplayed: 0.1uF  [0402]  (hidden comment: GRM155R71E104KE14D)
C128  Cap_F: 10µF  VDC_V: 10V  [0603]  (hidden comment: GRM188Z71A106MA73D)
C129  VDC_V: 25V  ValueDisplayed: 10000pF  [FP-GRM1555C1E103JE01D_0402-MFG]  (hidden comment: GRM1555C1E103JE01D)
C130  VDC_V: 6.3V  ValueDisplayed: 1uF  [0402]  (hidden comment: GRM155R70J105MA12D)
C131  VDC_V: 25V  ValueDisplayed: 0.1uF  [0402]  (hidden comment: GRM155R71E104KE14D)
C132  VDC_V: 6.3V  ValueDisplayed: 1uF  [0402]  (hidden comment: GRM155R70J105MA12D)
C133  VDC_V: 25V  ValueDisplayed: 0.1uF  [0402]  (hidden comment: GRM155R71E104KE14D)
C240  ValueDisplayed: 0.1uF  [0402]  (hidden comment: GRM155R71E104KE14D)
C241  ValueDisplayed: 0.1uF  [0402]  (hidden comment: GRM155R71E104KE14D)
C242  ValueDisplayed: 0.1uF  [0402]  (hidden comment: GRM155R71E104KE14D)
C270  VDC_V: 10V  ValueDisplayed: 0.1uF  [0402]  (hidden comment: 885012105010)
FB3  BLM18EG121SN1D  [FP-BLM18EG121SN1D_0603-MFG]
FB4  BLM18EG121SN1D  [FP-BLM18EG121SN1D_0603-MFG]
R100  ValueDisplayed: 0  [0402]  (hidden comment: ERJ-2GE0R00X)
R101  ValueDisplayed: 0  [0402]  (hidden comment: ERJ-2GE0R00X)
R102  ValueDisplayed: 0  [0402]  (hidden comment: ERJ-2GE0R00X)
R103  ValueDisplayed: 0  [0402]  (hidden comment: ERJ-2GE0R00X)
R104  ValueDisplayed: 0  [0402]  (hidden comment: ERJ-2GE0R00X)
R105  ValueDisplayed: 0  [0402]  (hidden comment: ERJ-2GE0R00X)
R106  ValueDisplayed: 0  [0402]  (hidden comment: ERJ-2GE0R00X)
R107  ValueDisplayed: 11.5k  [0402]  (hidden comment: ERJ-2RKF1152X)
R108  ValueDisplayed: 2.49k  [0402]  (hidden comment: CRCW04022K49FKED)
R109  ValueDisplayed: 2.49k  [0402]  (hidden comment: CRCW04022K49FKED)
R110  ValueDisplayed: 2.49k  [0402]  (hidden comment: CRCW04022K49FKED)
R111  ValueDisplayed: 2.49k  [0402]  (hidden comment: CRCW04022K49FKED)
R112  ValueDisplayed: 2.49k  [0402]  (hidden comment: CRCW04022K49FKED)
R113  ValueDisplayed: 2.49k  [0402]  (hidden comment: CRCW04022K49FKED)
R114  ValueDisplayed: 2.49k  [0402]  (hidden comment: CRCW04022K49FKED)
R115  ValueDisplayed: 2.49k  [0402]  (hidden comment: CRCW04022K49FKED)
R116  ValueDisplayed: 2.49k  [0402]  (hidden comment: CRCW04022K49FKED)
R117  ValueDisplayed: 0  [0402]  (hidden comment: ERJ-2GE0R00X)
R118  ValueDisplayed: 0  [0402]  (hidden comment: ERJ-2GE0R00X)
R119  ValueDisplayed: 0  [0402]  (hidden comment: ERJ-2GE0R00X)
R120  ValueDisplayed: 2.49k  [0402]  (hidden comment: CRCW04022K49FKED)
R121  ValueDisplayed: 2.49k  [0402]  (hidden comment: CRCW04022K49FKED)
R122  ValueDisplayed: 2.49k  [0402]  (hidden comment: CRCW04022K49FKED)
R123  ValueDisplayed: 2.49k  [0402]  (hidden comment: CRCW04022K49FKED)
R124  ValueDisplayed: 2.49k  [0402]  (hidden comment: CRCW04022K49FKED)
R125  ValueDisplayed: 2.49k  [0402]  (hidden comment: CRCW04022K49FKED)
R126  ValueDisplayed: 2.49k  [0402]  (hidden comment: CRCW04022K49FKED)
R127  ValueDisplayed: 2.49k  [0402]  (hidden comment: CRCW04022K49FKED)
R128  ValueDisplayed: 2.49k  [0402]  (hidden comment: CRCW04022K49FKED)
R291  ValueDisplayed: 10.0k  [0402]  (hidden comment: ERJ-2RKF1002X)
R292  ValueDisplayed: 10.0k  [0402]  (hidden comment: ERJ-2RKF1002X)
R293  ValueDisplayed: 1.0k  [0402]  (hidden comment: ERJ-2GEJ102X)
R294  ValueDisplayed: 1.0k  [0402]  (hidden comment: ERJ-2GEJ102X)
R305  ValueDisplayed: 10.0k  [0402]  (hidden comment: ERJ-2RKF1002X)
R424  ValueDisplayed: 10.0k  [0402]  (hidden comment: ERJ-2RKF1002X)
R425  ValueDisplayed: 10.0k  [0402L]  (hidden comment: CRCW040210K0FKED)
TP7  TESTPOINT  [TP_25MIL-SMT]  (value not drawn)  (no BOM)
U22  DP83869HMRGZT  [RGZ0048B-MFG]
U50  TS3DDR3812RUAR  [RUA0042A-MFG]
U65  SN74LVC1G08DBVR  [DBV0005A_N]  (parts A,B of 2)
Y2  Frequency_Fixed: 25MHz  [Abracon_ABM10W]  (hidden comment: ABM10W-25.0000MHZ-4-D1X-T3)

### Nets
GND: C112.1 C113.1 C114.2 C115.1 C116.2 C117.2 C118.2 C119.2 C120.2 C121.2 C122.2 C123.1 C124.2 C125.2 C126.2 C127.2 C128.2 C129.1 C130.2 C131.2 C132.2 C133.2 C240.1 C241.1 C242.1 C270.2 R107.1 R120.1 R121.1 R122.1 R123.1 R124.1 R125.1 R126.1 R127.1 R128.1 R293.1 R294.1 U22.49(GND) U50.43(GND) U65.3(GND) Y2.2(GND) Y2.4(GND)
VDD_ETH1_1V1_FILT: C114.1 C115.2 C116.1 C117.1 C118.1 C119.1 C120.1 C121.1 FB3.2 U22.6(VDD1P1) U22.31(VDD1P1) U22.39(VDD1P1)
VDD_ETH1_2V5_FILT: C122.1 C123.2 C124.1 C125.1 C126.1 C127.1 FB4.2 U22.3(VDDA2P5) U22.9(VDDA2P5)
VDD_ETH_1V1: FB3.1
VDD_ETH_2V5: FB4.1
VSYS_3V3: C128.1 C129.2 C130.1 C131.1 C132.1 C133.1 C240.2 C241.2 C242.2 C270.1 R108.2 R109.2 R110.2 R111.2 R112.2 R113.2 R114.2 R115.2 R116.2 R291.1 R292.1 R305.1 R424.1 R425.2 U22.18(VDDIO) U22.30(VDDIO) U50.1(VCC) U50.17(VCC) U50.30(VCC) U65.5(VCC)
AM263P_CLKOUT0: R118.1 ; off-sheet AM263P_CLKOUT0
AM263P_ICSSM_MII1_COL: R112.1 R124.2 U22.45(LED_2/GPIO_0) ; off-sheet AM263P_ICSSM_MII1_COL
AM263P_ICSSM_MII1_RXCLK: U50.31(C5) ; off-sheet AM263P_ICSSM_MII1_RXCLK
AM263P_ICSSM_MII1_RXD0: U50.42(C0) ; off-sheet AM263P_ICSSM_MII1_RXD0
AM263P_ICSSM_MII1_RXD1: U50.40(C1) ; off-sheet AM263P_ICSSM_MII1_RXD1
AM263P_ICSSM_MII1_RXD2: U50.37(C2) ; off-sheet AM263P_ICSSM_MII1_RXD2
AM263P_ICSSM_MII1_RXD3: U50.35(C3) ; off-sheet AM263P_ICSSM_MII1_RXD3
AM263P_ICSSM_MII1_RXDV: U50.33(C4) ; off-sheet AM263P_ICSSM_MII1_RXDV
AM263P_ICSSM_MII1_RXER: R111.1 R123.2 U22.46(LED_1/RX_ER) ; off-sheet AM263P_ICSSM_MII1_RXER
AM263P_ICSSM_MII1_RXLINK: R110.1 R122.2 U22.47(LED_0) ; off-sheet AM263P_ICSSM_MII1_RXLINK
AM263P_ICSSM_MII1_TXCLK: U50.18(C11) ; off-sheet AM263P_ICSSM_MII1_TXCLK
AM263P_ICSSM_MII1_TXD0: U50.28(C6) ; off-sheet AM263P_ICSSM_MII1_TXD0
AM263P_ICSSM_MII1_TXD1: U50.26(C7) ; off-sheet AM263P_ICSSM_MII1_TXD1
AM263P_ICSSM_MII1_TXD2: U50.24(C8) ; off-sheet AM263P_ICSSM_MII1_TXD2
AM263P_ICSSM_MII1_TXD3: U50.22(C9) ; off-sheet AM263P_ICSSM_MII1_TXD3
AM263P_ICSSM_MII1_TXEN: U50.20(C10) ; off-sheet AM263P_ICSSM_MII1_TXEN
AM263P_RGMII1_RD0: U50.41(B0) ; off-sheet AM263P_RGMII1_RD0
AM263P_RGMII1_RD1: U50.39(B1) ; off-sheet AM263P_RGMII1_RD1
AM263P_RGMII1_RD2: U50.38(B2) ; off-sheet AM263P_RGMII1_RD2
AM263P_RGMII1_RD3: U50.36(B3) ; off-sheet AM263P_RGMII1_RD3
AM263P_RGMII1_RX_CTL: U50.34(B4) ; off-sheet AM263P_RGMII1_RX_CTL
AM263P_RGMII1_RXC: U50.32(B5) ; off-sheet AM263P_RGMII1_RXC
AM263P_RGMII1_TD0: U50.29(B6) ; off-sheet AM263P_RGMII1_TD0
AM263P_RGMII1_TD1: U50.27(B7) ; off-sheet AM263P_RGMII1_TD1
AM263P_RGMII1_TD2: U50.25(B8) ; off-sheet AM263P_RGMII1_TD2
AM263P_RGMII1_TD3: U50.23(B9) ; off-sheet AM263P_RGMII1_TD3
AM263P_RGMII1_TX_CTL: U50.21(B10) ; off-sheet AM263P_RGMII1_TX_CTL
AM263P_RGMII1_TXC: U50.19(B11) ; off-sheet AM263P_RGMII1_TXC
AM263P_WARMRSTN: U65.2(B) ; off-sheet AM263P_WARMRSTN
CPSW RGMI1/ICSSM_MII1_RST_EN: R424.2 U65.1(A) ; off-sheet CPSW RGMI1/ICSSM_MII1_RST_EN
ETH1_CLKOUT: R106.2 ; off-sheet ETH1_CLKOUT
ETH1_CLKOUT_R: R106.1 U22.40(CLK_OUT)
ETH1_GPIO_1: R114.1 R126.2 U22.22(JTAG_TDO/GPIO_1)
ETH1_PWDN: R305.2 U22.44(~{INT}/~{PWDN})
ETH1_RBIAS: R107.2 U22.12(RBIAS)
ETH1_RD0: R102.1 R108.1 R120.2 U50.2(A0)
ETH1_RD0_R: R102.2 U22.33(RX_D0)
ETH1_RD1: R103.1 R109.1 R121.2 U50.3(A1)
ETH1_RD1_R: R103.2 U22.34(RX_D1)
ETH1_RD2: R104.1 R115.1 R127.2 U50.4(A2)
ETH1_RD2_R: R104.2 U22.35(RX_D2)
ETH1_RD3: R105.1 R116.1 R128.2 U50.5(A3)
ETH1_RD3_R: R105.2 U22.36(RX_D3)
ETH1_RX_CTL: R101.1 R113.1 R125.2 U50.6(A4)
ETH1_RX_CTL_R: R101.2 U22.38(RX_CTRL/RX_DV)
ETH1_RXC: R100.1 U50.7(A5)
ETH1_RXC_R: R100.2 U22.32(RX_CLK)
ETH1_TD0: U22.28(TX_D0) U50.11(A6)
ETH1_TD1: U22.27(TX_D1) U50.12(A7)
ETH1_TD2: U22.26(TX_D2) U50.13(A8)
ETH1_TD3: U22.25(TX_D3) U50.14(A9)
ETH1_TD_A_N: U22.2(TD_M_A) ; off-sheet ETH1_TD_A_N
ETH1_TD_A_P: U22.1(TD_P_A) ; off-sheet ETH1_TD_A_P
ETH1_TD_B_N: U22.5(TD_M_B) ; off-sheet ETH1_TD_B_N
ETH1_TD_B_P: U22.4(TD_P_B) ; off-sheet ETH1_TD_B_P
ETH1_TD_C_N: U22.8(TD_M_C) ; off-sheet ETH1_TD_C_N
ETH1_TD_C_P: U22.7(TD_P_C) ; off-sheet ETH1_TD_C_P
ETH1_TD_D_N: U22.11(TD_M_D) ; off-sheet ETH1_TD_D_N
ETH1_TD_D_P: U22.10(TD_P_D) ; off-sheet ETH1_TD_D_P
ETH1_TX_CTL_EN: U22.37(TX_CTRL/TX_EN) U50.15(A10)
ETH1_TXC: U22.29(GTX_CLK/TX_CLK) U50.16(A11)
ETH1_XI: R117.2 R118.2 U22.20(XI)
ETH1_XO: R119.2 U22.19(XO)
ETH1_XTAL_XI: C112.2 R117.1 Y2.1
ETH1_XTAL_XO: C113.2 R119.1 Y2.3
MDIO_CLOCK: U22.42(MDC) ; off-sheet MDIO_CLOCK
MDIO_DATA: U22.41(MDIO) ; off-sheet MDIO_DATA
PHY1_RST: R425.1 U22.43(~{RESET}) U65.4(Y)
RGMII1_ICSSM_MUX_EN: R292.2 R294.2 U50.8(EN) ; off-sheet RGMII1_ICSSM_MUX_EN
RGMII1_ICSSM_MUX_SEL_GPIO105: R291.2 R293.2 U50.9(SEL1) U50.10(SEL2) ; off-sheet RGMII1_ICSSM_MUX_SEL_GPIO105
VDDA_ETH1_1V8: TP7.1 U22.13(VDDA1P8_1) U22.48(VDDA1P8_2)

Not connected (* = marked no-connect by the designer): U22 14(SON)* 15(SOP)* 16(SIP)* 17(SIN)* 21(JTAG_CLK/TX_ER)* 23(JTAG_TMS)* 24(JTAG_TDI/SD)*

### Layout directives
differential pair: ETH1_TD_A_N, ETH1_TD_A_P, ETH1_TD_B_N, ETH1_TD_B_P, ETH1_TD_C_N, ETH1_TD_C_P, ETH1_TD_D_N, ETH1_TD_D_P
mark named ETH1_TWISTED_PAIRS: ETH1_TD_A_N, ETH1_TD_A_P, ETH1_TD_B_N, ETH1_TD_B_P, ETH1_TD_C_N, ETH1_TD_C_P, ETH1_TD_D_N, ETH1_TD_D_P
mark named ETH1_CLK_DATA_CONTROL: ETH1_RD0, ETH1_RD1, ETH1_RD2, ETH1_RD3, ETH1_RX_CTL, ETH1_RXC, ETH1_TD0, ETH1_TD1, ETH1_TD2, ETH1_TD3, ETH1_TX_CTL_EN, ETH1_TXC

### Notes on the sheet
- AM263P Ethernet PHY #1 - CPSW RGMII1/ICSSM_MII1
- CPSW1 / ICSSM1 MUX
- MUX Default Pulls
- (near U22) RGMII/MII PHY
- (near R291) Note: TS3DDR MUX defaults
  - EN pulled low - MUX disabled (default)
  - SEL pulled low - path A <-> B enabled (default)
- (near U50) Note: CPSW / ICSSM MUX
  - selects between the CPSW RGMII1/MII1 interfaces and the PRU1 ICSSM MII1 interfaces
- (near U50) MUX Decoupling
- PHY  Decoupling
- (near Y2) 25 MHz Crystal
- PHY Strap Resistors
- PHY1_RST_LOGIC
- Oscillator Input Selection
- (near R119) Note: PHY Oscillator Input Selection
  - (default) select 25 MHz XTAL input to ETH1_XI/SO
  - optional select to disable 25 MHz XTAL and input AM263Px CLKOUT0 to PHY
- Note: PHY Strap Resistor Selection
  - PHY ADDRESS = 0b0011, 0x3
  - Auto-negotiation, 10/100/1000 advertised, Auto-MDI-X
  - RGMII to Copper (1000BaseT/100Base-TX/10Base-Te)

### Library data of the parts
C112 C113 = CMP-0035228-1: Multi-Layer Ceramic Capacitor 12pF C0G  ±5% 0402 Paper T/R; Manufacturer: Murata; TempCo: 30ppm/°C; SizeZ_mm: 0.55mm; AEC Qualified: No
C114 C122 C128 = CMP-0007497-5: CAP, CERM, 10 uF, 10 V, +/- 20%, X7R, 0603; Manufacturer: MuRata; TaMin_C: -55°C; Polarized: N; SizeAreaWB_mm2: 4.68; Value1: Unknown; U/M: EA; Value: 10uF; TaMax_C: 125°C; SizeZ_mm: 1; SizeX_mm: 1.6; SizeY_mm: 0.8; SizeArea_mm2: 1.28; AEC Category: Q200
C115 C123 C129 = CMP-0035343-1: Chip Multilayer Ceramic Capacitors for General Purpose, 0402, 10000pF, C0G, 30ppm/°C, 5%, 25V; Manufacturer: Murata; Value: 10nF; SizeZ_mm: 0.65mm; AEC Qualified: No
C116 C118 C120 C124 C126 C130 C132 = CMP-0006624-2: CAP, CERM, 1 uF, 6.3 V, +/- 20%, X7R, 0402; Manufacturer: MuRata; TaMin_C: -55°C; Polarized: N; SizeAreaWB_mm2: 3; Value1: Unknown; U/M: EA; Value: 1uF; TaMax_C: 125°C; SizeZ_mm: 0.6; SizeX_mm: 1; SizeY_mm: 0.5; Cap_F: 1µF; AEC Category: Q200
C117 C119 C121 C125 C127 C131 C133 = CMP-0006659-2: CAP, CERM, 0.1 uF, 25 V, +/- 10%, X7R, 0402; Manufacturer: MuRata; TaMin_C: -55°C; Polarized: N; SizeAreaWB_mm2: 3; Value1: Unknown; U/M: EA; Value: 0.1uF; TaMax_C: 125°C; SizeZ_mm: 0.6; SizeX_mm: 1; SizeY_mm: 0.5; Cap_F: 100nF; AEC Category: Q200
C240-C242 = CMP-0006659-2: CAP, CERM, 0.1 uF, 25 V, +/- 10%, X7R, 0402; Manufacturer: MuRata; TaMin_C: -55°C; Polarized: N; SizeAreaWB_mm2: 3; U/M: EA; Value: 0.1uF; TaMax_C: 125°C; SizeZ_mm: 0.6; SizeX_mm: 1; SizeY_mm: 0.5; Value2: 25V; Cap_F: 100nF; AEC Category: Q200; Value1: Unknown
C270 = CMP-0006221-2: CAP, CERM, 0.1 uF, 10 V, +/- 20%, X5R, 0402; Manufacturer: Wurth Elektronik; TaMin_C: -55°C; Polarized: N; SizeAreaWB_mm2: 3; Value1: Unknown; U/M: EA; Value: 0.1uF; TaMax_C: 85°C; SizeZ_mm: 0.6; SizeX_mm: 1; SizeY_mm: 0.5; Cap_F: 100nF; AEC Category: Q200
FB3 FB4 = CMP-0089199-1: 120 Ohms @ 100MHz 1  Ferrite Bead 0603 (1608 Metric) 2A 40mOhm; Manufacturer: Murata; DCR_ohm: 60m; AEC Qualified: No; Tolerance_%: 25%; SizeZ_mm: 0.95mm; Impedance At Frequency: 120Ω @ 100MHz
R100-R106 R117-R119 = CMP-0026992-3: RES, 0, 5%, 0.1 W, AEC-Q200 Grade 0, 0402; Manufacturer: Panasonic; Power_W: 100mW; TempCo: 600 ppm/C; Value_Code: 0000; Value: 0; EIA_Code: E24; SizeX_mm: 1; SizeY_mm: 0.5; SizeZ_mm: 0.6; Value2: 0.1W; AEC Qualified: Y; VDC_V: 50V; AEC Category: Q200; SizeAreaWB_mm2: 3
R107 = CMP-0082348-1: RES, 11.5 k, 1%, 0.1 W, AEC-Q200 Grade 0, 0402; Manufacturer: Panasonic; Value_Code: 11k5; SizeAreaWB_mm2: 3; SizeArea_mm2: 0.5; AEC Qualified: Y; AEC Category: Q200; Value: 11.5k; SizeZ_mm: 0.6; EIA_Code: E96; TempCo: 100 ppm/C; AEC Grade: 0; Power_W: 100mW; Value2: 0.1W; SizeX_mm: 1
R108-R116 R120-R128 = CMP-0026237-2: RES, 2.49 k, 1%, 0.063 W, AEC-Q200 Grade 0, 0402; Manufacturer: Vishay-Dale; Power_W: 63mW; TempCo: 100 ppm/C; Value_Code: 2k49; Value: 2.49k; EIA_Code: E96; SizeX_mm: 1; SizeY_mm: 0.5; SizeZ_mm: 0.6; Value2: 0.063W; AEC Qualified: Y; VDC_V: 50V; AEC Category: Q200; AEC Grade: 0
R291 R292 R305 R424 = CMP-0026658-1: RES, 10.0 k, 1%, 0.1 W, 0402; Manufacturer: Panasonic; Power_W: 100mW; TempCo: 100 ppm/C; Value_Code: 10k0; U/M: EA; Value: 10.0k; EIA_Code: E96; Res_ohm: 10k; SizeX_mm: 1; SizeY_mm: 0.5; SizeZ_mm: 0.6; Value2: 0.1W; VDC_V: 50V; AEC Category: Q200
R293 R294 = CMP-0078193-1: RES, 1.0 k, 5%, 0.1 W, AEC-Q200 Grade 0, 0402; Manufacturer: Panasonic; Value_Code: 1k00; SizeArea_mm2: 0.5; AEC Qualified: Y; AEC Category: Q200; Res_ohm: 1k; Value: 1.0k; SizeZ_mm: 0.6; Green_REACh: Passed; EIA_Code: E24; TempCo: 200 ppm/C; AEC Grade: 0; Power_W: 100mW; VDC_V: 50V; Value2: 0.1W; Green_Lifecycle: Active; U/M: EA; SizeX_mm: 1
R425 = CMP-0025958-3: RES, 10.0 k, 1%, 0.063 W, AEC-Q200 Grade 0, 0402; Manufacturer: Vishay-Dale; Power_W: 63mW; TempCo: 100 ppm/C; Value_Code: 10k0; Value: 10.0k; EIA_Code: E96; Res_ohm: 10k; SizeX_mm: 1; SizeY_mm: 0.5; SizeZ_mm: 0.6; Value2: 0.063W; AEC Qualified: Y; VDC_V: 50V; AEC Category: Q200; AEC Grade: 0
TP7 = CMP-0078143-3: TEST POINT.  No entry in BOM.
U22 = CMP-0091377-1: 1/1 Transceiver Ethernet 48-VQFN (7x7); Manufacturer: Texas Instruments; TaMin_C: -40°C; SizeZ_mm: 1mm; TaMax_C: +125°C; Max Supply Voltage: 3.45V; Number Of Channels: 1; AEC Qualified: No; Data Rate: 1000Mbits/s; Min Supply Voltage: 990mV; Simplex Duplex: Full-Duplex; Standoff Height: 0mm
U50 = CMP-0093539-2: IC MUX/DEMUX DDR3 1:2 42WQFN; Manufacturer: Texas Instruments; TaMax_C: +85°C; TaMin_C: -40°C; On State Resistance: 8Ω; SizeZ_mm: 0.8mm; Min Supply Voltage: 3V; Standoff Height: 0mm; Max Supply Voltage: 3.6V; AEC Qualified: No; PositionCount: 12; -3Db Bandwith: 1.675GHz; Nominal Supply Current: 300uA; AEC Category: Q200
U65 = CMP-0051588-2: Single 2-Input Positive-AND Gate, DBV0005A, LARGE T&R; Manufacturer: Texas Instruments; Logic: True; ICC @ Nom Voltage(Max)(mA): 0.01; VCC(Min)(V): 1.65; Bits(#): 1; Rating: Catalog; Schmitt Trigger: No; Voltage(Nom)(V): 1.8,2.5,3.3,5; Output Drive (IOL/IOH)(Max)(mA): 32/-32; Gate Type: AND; tpd @ Nom Voltage(Max)(ns): 4.5,6,4,5; VCC(Max)(V): 5.5; Output Type: CMOS; F @ Nom Voltage(Max)(Mhz): 150; Input Type: CMOS/TTL; Technology Family: LVC; AEC Category: Q200; AEC Qualified: N; CompType: IC
Y2 = CMP-0084811-1: Crystal, 25 MHz, 10 ppm, 4 pF, SMD; Manufacturer: Abracon Corporation; Load Capacitance: 4 pF; TaMax_C: 85°C; SizeY_mm: 2.5; SizeAreaWB_mm2: 10.5; AEC Category: Q200; Frequency Stability: 20 ppm; SizeX_mm: 2; SizeArea_mm2: 5; SizeZ_mm: 0.6; AEC Qualified: N; TaMin_C: -40°C; Frequency Tolerance: 10 ppm

## Sheet PROC171_Ehernet_PHY_2.SchDoc
size 431 x 279 mm; Date: Not shown in title block; ApprovedBy: Not shown in title block; CheckedBy: Not shown in title block; Author: Not shown in title block; CompanyName: Not shown in title block; Engineer: Not shown in title block; Organization: Not shown in title block; Address1: Not shown in title block; Address2: Not shown in title block; Address3: Not shown in title block; Address4: Not shown in title block; DocumentNumber: 17; Revision: Use project parameter SCH_Rev; SheetNumber: 17; SheetTotal: 26; PageSetup: Record=PageOptions¦CenterHorizontal=True¦CenterVertical=True¦PrintScale=1.00¦XCorrection=1.00¦YCorrection=1.00¦PrintKind=0¦BorderSize=5000000¦LeftOffset=0¦BottomOffset=0¦Orientation=2¦PaperLength=1000¦PaperWidth=1000¦Scale=100¦PaperSource=15¦PrintQuality=600¦MediaType=1¦DitherType=10¦PaperKind=Letter¦PrintScaleMode=1

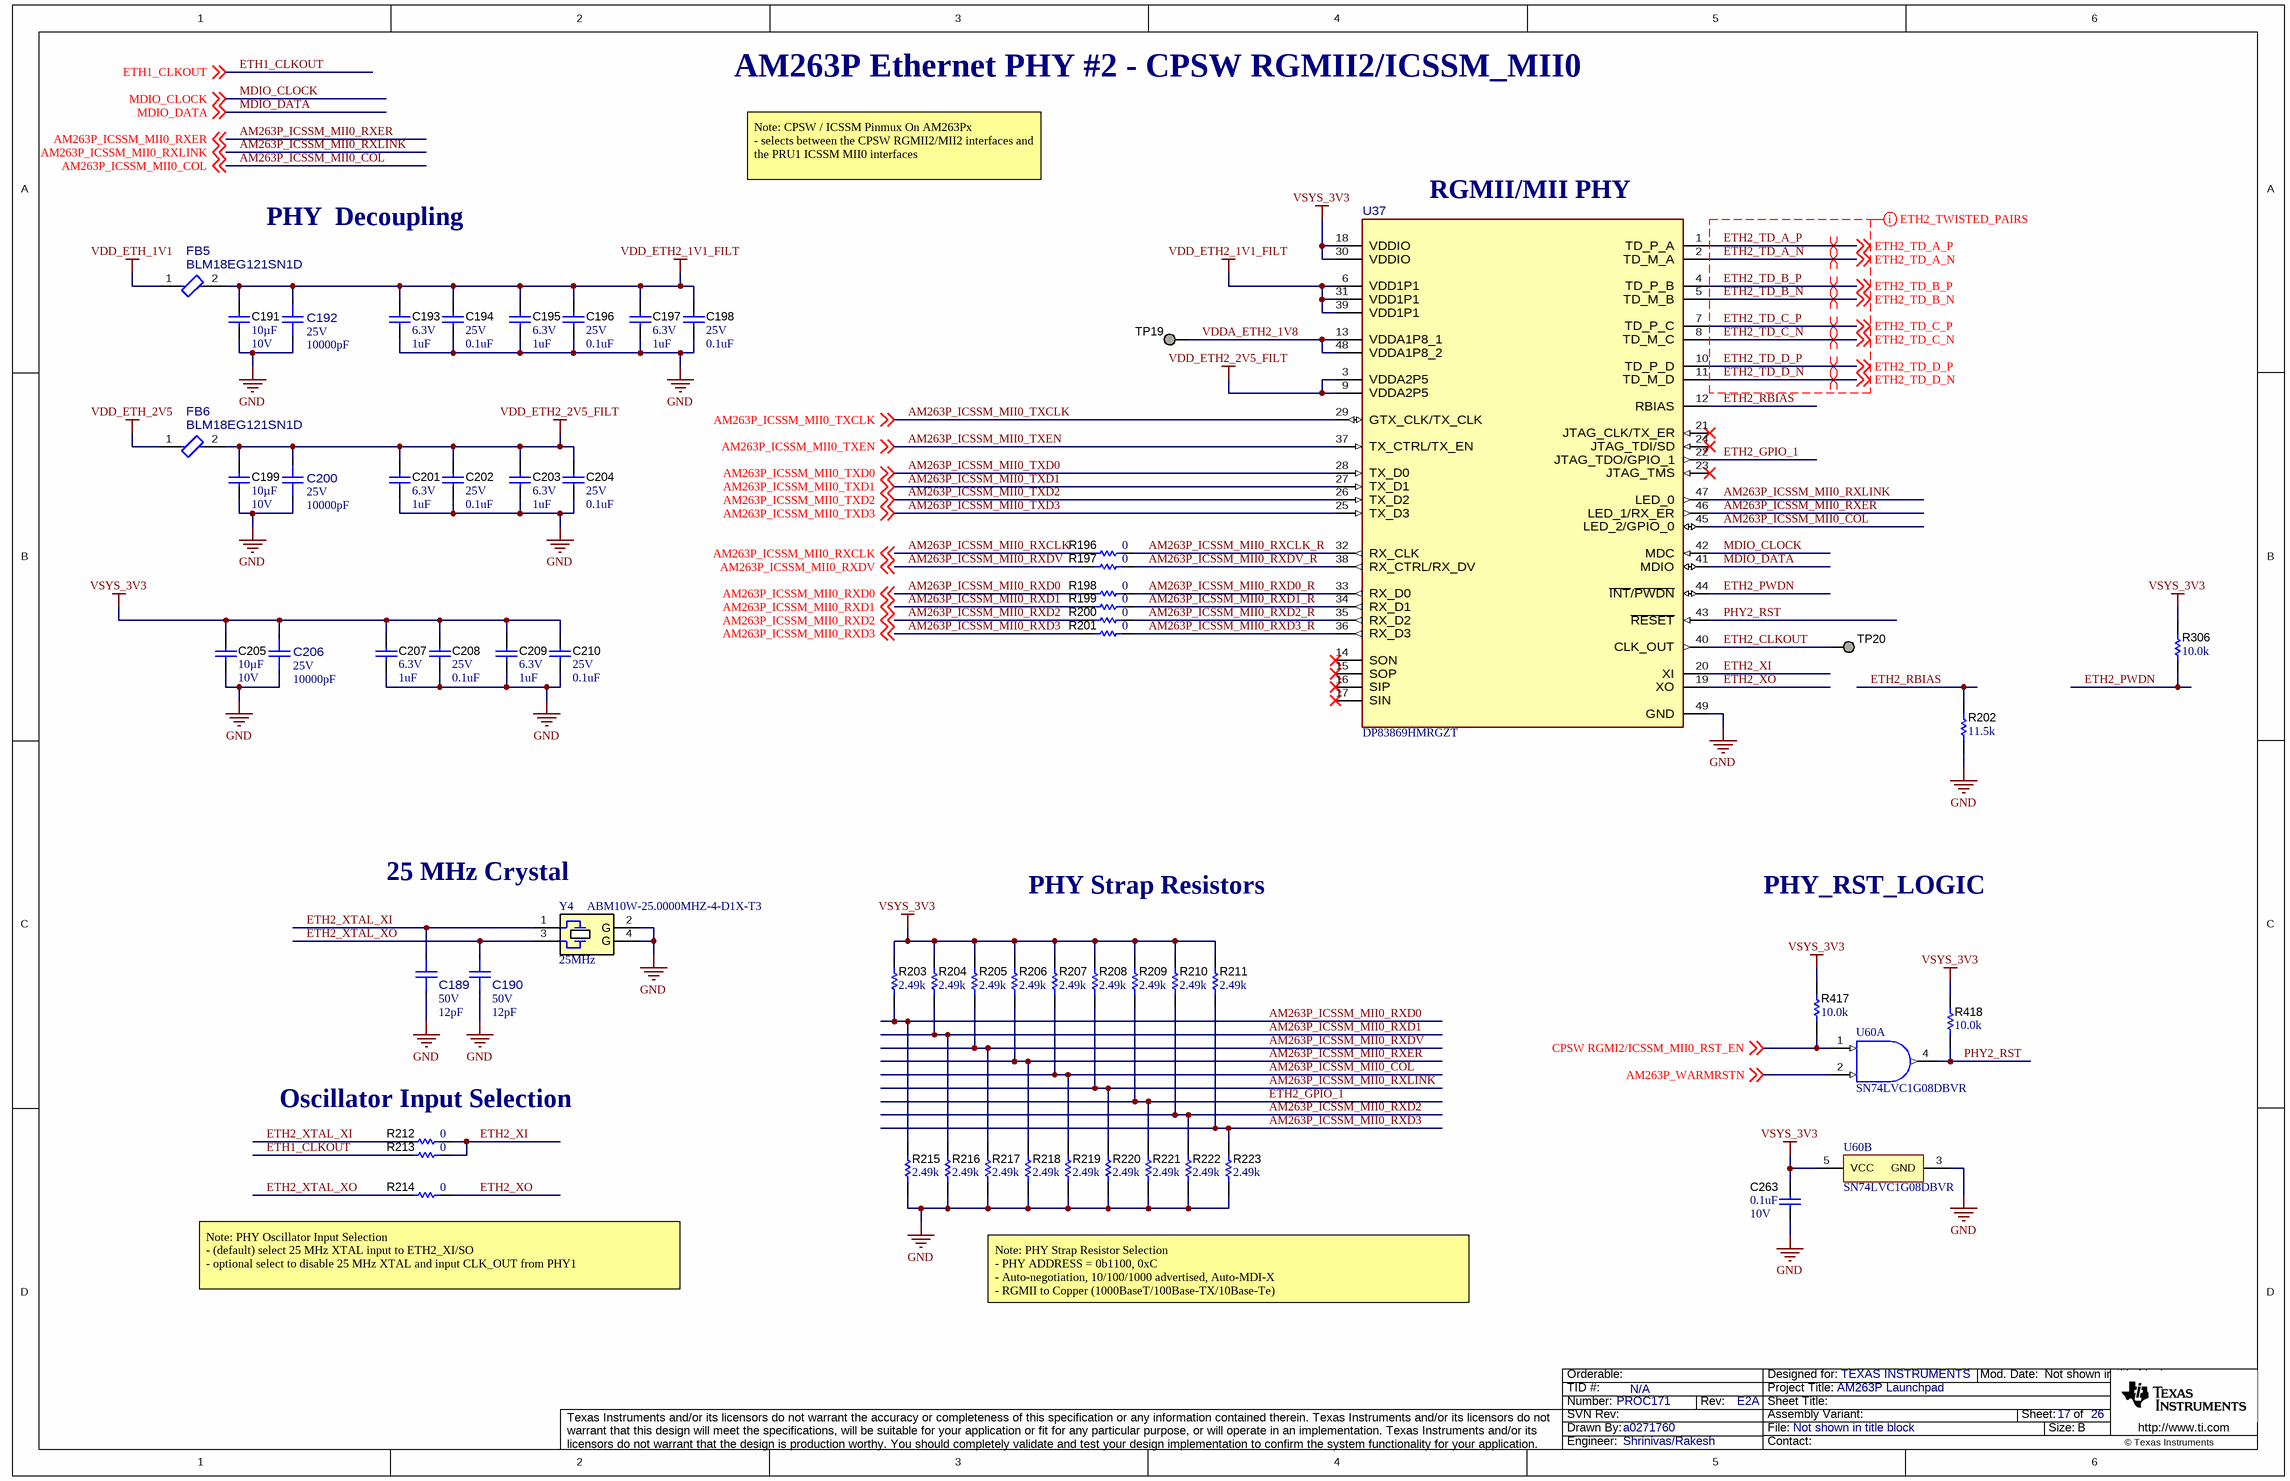
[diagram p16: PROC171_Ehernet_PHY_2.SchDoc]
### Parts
C189  VDC_V: 50V  ValueDisplayed: 12pF  [FP-GJM1555C1H120JB01D_0402-MFG]  (hidden comment: GJM1555C1H120JB01D)
C190  VDC_V: 50V  ValueDisplayed: 12pF  [FP-GJM1555C1H120JB01D_0402-MFG]  (hidden comment: GJM1555C1H120JB01D)
C191  Cap_F: 10µF  VDC_V: 10V  [0603]  (hidden comment: GRM188Z71A106MA73D)
C192  VDC_V: 25V  ValueDisplayed: 10000pF  [FP-GRM1555C1E103JE01D_0402-MFG]  (hidden comment: GRM1555C1E103JE01D)
C193  VDC_V: 6.3V  ValueDisplayed: 1uF  [0402]  (hidden comment: GRM155R70J105MA12D)
C194  VDC_V: 25V  ValueDisplayed: 0.1uF  [0402]  (hidden comment: GRM155R71E104KE14D)
C195  VDC_V: 6.3V  ValueDisplayed: 1uF  [0402]  (hidden comment: GRM155R70J105MA12D)
C196  VDC_V: 25V  ValueDisplayed: 0.1uF  [0402]  (hidden comment: GRM155R71E104KE14D)
C197  VDC_V: 6.3V  ValueDisplayed: 1uF  [0402]  (hidden comment: GRM155R70J105MA12D)
C198  VDC_V: 25V  ValueDisplayed: 0.1uF  [0402]  (hidden comment: GRM155R71E104KE14D)
C199  Cap_F: 10µF  VDC_V: 10V  [0603]  (hidden comment: GRM188Z71A106MA73D)
C200  VDC_V: 25V  ValueDisplayed: 10000pF  [FP-GRM1555C1E103JE01D_0402-MFG]  (hidden comment: GRM1555C1E103JE01D)
C201  VDC_V: 6.3V  ValueDisplayed: 1uF  [0402]  (hidden comment: GRM155R70J105MA12D)
C202  VDC_V: 25V  ValueDisplayed: 0.1uF  [0402]  (hidden comment: GRM155R71E104KE14D)
C203  VDC_V: 6.3V  ValueDisplayed: 1uF  [0402]  (hidden comment: GRM155R70J105MA12D)
C204  VDC_V: 25V  ValueDisplayed: 0.1uF  [0402]  (hidden comment: GRM155R71E104KE14D)
C205  Cap_F: 10µF  VDC_V: 10V  [0603]  (hidden comment: GRM188Z71A106MA73D)
C206  VDC_V: 25V  ValueDisplayed: 10000pF  [FP-GRM1555C1E103JE01D_0402-MFG]  (hidden comment: GRM1555C1E103JE01D)
C207  VDC_V: 6.3V  ValueDisplayed: 1uF  [0402]  (hidden comment: GRM155R70J105MA12D)
C208  VDC_V: 25V  ValueDisplayed: 0.1uF  [0402]  (hidden comment: GRM155R71E104KE14D)
C209  VDC_V: 6.3V  ValueDisplayed: 1uF  [0402]  (hidden comment: GRM155R70J105MA12D)
C210  VDC_V: 25V  ValueDisplayed: 0.1uF  [0402]  (hidden comment: GRM155R71E104KE14D)
C263  VDC_V: 10V  ValueDisplayed: 0.1uF  [0402]  (hidden comment: 885012105010)
FB5  BLM18EG121SN1D  [FP-BLM18EG121SN1D_0603-MFG]
FB6  BLM18EG121SN1D  [FP-BLM18EG121SN1D_0603-MFG]
R196  ValueDisplayed: 0  [0402]  (hidden comment: ERJ-2GE0R00X)
R197  ValueDisplayed: 0  [0402]  (hidden comment: ERJ-2GE0R00X)
R198  ValueDisplayed: 0  [0402]  (hidden comment: ERJ-2GE0R00X)
R199  ValueDisplayed: 0  [0402]  (hidden comment: ERJ-2GE0R00X)
R200  ValueDisplayed: 0  [0402]  (hidden comment: ERJ-2GE0R00X)
R201  ValueDisplayed: 0  [0402]  (hidden comment: ERJ-2GE0R00X)
R202  ValueDisplayed: 11.5k  [0402]  (hidden comment: ERJ-2RKF1152X)
R203  ValueDisplayed: 2.49k  [0402]  (hidden comment: CRCW04022K49FKED)
R204  ValueDisplayed: 2.49k  [0402]  (hidden comment: CRCW04022K49FKED)
R205  ValueDisplayed: 2.49k  [0402]  (hidden comment: CRCW04022K49FKED)
R206  ValueDisplayed: 2.49k  [0402]  (hidden comment: CRCW04022K49FKED)
R207  ValueDisplayed: 2.49k  [0402]  (hidden comment: CRCW04022K49FKED)
R208  ValueDisplayed: 2.49k  [0402]  (hidden comment: CRCW04022K49FKED)
R209  ValueDisplayed: 2.49k  [0402]  (hidden comment: CRCW04022K49FKED)
R210  ValueDisplayed: 2.49k  [0402]  (hidden comment: CRCW04022K49FKED)
R211  ValueDisplayed: 2.49k  [0402]  (hidden comment: CRCW04022K49FKED)
R212  ValueDisplayed: 0  [0402]  (hidden comment: ERJ-2GE0R00X)
R213  ValueDisplayed: 0  [0402]  (hidden comment: ERJ-2GE0R00X)
R214  ValueDisplayed: 0  [0402]  (hidden comment: ERJ-2GE0R00X)
R215  ValueDisplayed: 2.49k  [0402]  (hidden comment: CRCW04022K49FKED)
R216  ValueDisplayed: 2.49k  [0402]  (hidden comment: CRCW04022K49FKED)
R217  ValueDisplayed: 2.49k  [0402]  (hidden comment: CRCW04022K49FKED)
R218  ValueDisplayed: 2.49k  [0402]  (hidden comment: CRCW04022K49FKED)
R219  ValueDisplayed: 2.49k  [0402]  (hidden comment: CRCW04022K49FKED)
R220  ValueDisplayed: 2.49k  [0402]  (hidden comment: CRCW04022K49FKED)
R221  ValueDisplayed: 2.49k  [0402]  (hidden comment: CRCW04022K49FKED)
R222  ValueDisplayed: 2.49k  [0402]  (hidden comment: CRCW04022K49FKED)
R223  ValueDisplayed: 2.49k  [0402]  (hidden comment: CRCW04022K49FKED)
R306  ValueDisplayed: 10.0k  [0402]  (hidden comment: ERJ-2RKF1002X)
R417  ValueDisplayed: 10.0k  [0402]  (hidden comment: ERJ-2RKF1002X)
R418  ValueDisplayed: 10.0k  [0402L]  (hidden comment: CRCW040210K0FKED)
TP19  TESTPOINT  [TP_25MIL-SMT]  (value not drawn)  (no BOM)
TP20  TESTPOINT  [TP_25MIL-SMT]  (value not drawn)  (no BOM)
U37  DP83869HMRGZT  [RGZ0048B-MFG]
U60  SN74LVC1G08DBVR  [DBV0005A_N]  (parts A,B of 2)
Y4  Frequency_Fixed: 25MHz  [Abracon_ABM10W]  (hidden comment: ABM10W-25.0000MHZ-4-D1X-T3)

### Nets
GND: C189.1 C190.1 C191.2 C192.1 C193.2 C194.2 C195.2 C196.2 C197.2 C198.2 C199.2 C200.1 C201.2 C202.2 C203.2 C204.2 C205.2 C206.1 C207.2 C208.2 C209.2 C210.2 C263.2 R202.1 R215.1 R216.1 R217.1 R218.1 R219.1 R220.1 R221.1 R222.1 R223.1 U37.49(GND) U60.3(GND) Y4.2(GND) Y4.4(GND)
VDD_ETH2_1V1_FILT: C191.1 C192.2 C193.1 C194.1 C195.1 C196.1 C197.1 C198.1 FB5.2 U37.6(VDD1P1) U37.31(VDD1P1) U37.39(VDD1P1)
VDD_ETH2_2V5_FILT: C199.1 C200.2 C201.1 C202.1 C203.1 C204.1 FB6.2 U37.3(VDDA2P5) U37.9(VDDA2P5)
VDD_ETH_1V1: FB5.1
VDD_ETH_2V5: FB6.1
VSYS_3V3: C205.1 C206.2 C207.1 C208.1 C209.1 C210.1 C263.1 R203.2 R204.2 R205.2 R206.2 R207.2 R208.2 R209.2 R210.2 R211.2 R306.1 R417.1 R418.2 U37.18(VDDIO) U37.30(VDDIO) U60.5(VCC)
AM263P_ICSSM_MII0_COL: R207.1 R219.2 U37.45(LED_2/GPIO_0) ; off-sheet AM263P_ICSSM_MII0_COL
AM263P_ICSSM_MII0_RXCLK: R196.1 ; off-sheet AM263P_ICSSM_MII0_RXCLK
AM263P_ICSSM_MII0_RXCLK_R: R196.2 U37.32(RX_CLK)
AM263P_ICSSM_MII0_RXD0: R198.1 R203.1 R215.2 ; off-sheet AM263P_ICSSM_MII0_RXD0
AM263P_ICSSM_MII0_RXD0_R: R198.2 U37.33(RX_D0)
AM263P_ICSSM_MII0_RXD1: R199.1 R204.1 R216.2 ; off-sheet AM263P_ICSSM_MII0_RXD1
AM263P_ICSSM_MII0_RXD1_R: R199.2 U37.34(RX_D1)
AM263P_ICSSM_MII0_RXD2: R200.1 R210.1 R222.2 ; off-sheet AM263P_ICSSM_MII0_RXD2
AM263P_ICSSM_MII0_RXD2_R: R200.2 U37.35(RX_D2)
AM263P_ICSSM_MII0_RXD3: R201.1 R211.1 R223.2 ; off-sheet AM263P_ICSSM_MII0_RXD3
AM263P_ICSSM_MII0_RXD3_R: R201.2 U37.36(RX_D3)
AM263P_ICSSM_MII0_RXDV: R197.1 R205.1 R217.2 ; off-sheet AM263P_ICSSM_MII0_RXDV
AM263P_ICSSM_MII0_RXDV_R: R197.2 U37.38(RX_CTRL/RX_DV)
AM263P_ICSSM_MII0_RXER: R206.1 R218.2 U37.46(LED_1/RX_ER) ; off-sheet AM263P_ICSSM_MII0_RXER
AM263P_ICSSM_MII0_RXLINK: R208.1 R220.2 U37.47(LED_0) ; off-sheet AM263P_ICSSM_MII0_RXLINK
AM263P_ICSSM_MII0_TXCLK: U37.29(GTX_CLK/TX_CLK) ; off-sheet AM263P_ICSSM_MII0_TXCLK
AM263P_ICSSM_MII0_TXD0: U37.28(TX_D0) ; off-sheet AM263P_ICSSM_MII0_TXD0
AM263P_ICSSM_MII0_TXD1: U37.27(TX_D1) ; off-sheet AM263P_ICSSM_MII0_TXD1
AM263P_ICSSM_MII0_TXD2: U37.26(TX_D2) ; off-sheet AM263P_ICSSM_MII0_TXD2
AM263P_ICSSM_MII0_TXD3: U37.25(TX_D3) ; off-sheet AM263P_ICSSM_MII0_TXD3
AM263P_ICSSM_MII0_TXEN: U37.37(TX_CTRL/TX_EN) ; off-sheet AM263P_ICSSM_MII0_TXEN
AM263P_WARMRSTN: U60.2(B) ; off-sheet AM263P_WARMRSTN
CPSW RGMI2/ICSSM_MII0_RST_EN: R417.2 U60.1(A) ; off-sheet CPSW RGMI2/ICSSM_MII0_RST_EN
ETH1_CLKOUT: R213.1 ; off-sheet ETH1_CLKOUT
ETH2_CLKOUT: TP20.1 U37.40(CLK_OUT)
ETH2_GPIO_1: R209.1 R221.2 U37.22(JTAG_TDO/GPIO_1)
ETH2_PWDN: R306.2 U37.44(~{INT}/~{PWDN})
ETH2_RBIAS: R202.2 U37.12(RBIAS)
ETH2_TD_A_N: U37.2(TD_M_A) ; off-sheet ETH2_TD_A_N
ETH2_TD_A_P: U37.1(TD_P_A) ; off-sheet ETH2_TD_A_P
ETH2_TD_B_N: U37.5(TD_M_B) ; off-sheet ETH2_TD_B_N
ETH2_TD_B_P: U37.4(TD_P_B) ; off-sheet ETH2_TD_B_P
ETH2_TD_C_N: U37.8(TD_M_C) ; off-sheet ETH2_TD_C_N
ETH2_TD_C_P: U37.7(TD_P_C) ; off-sheet ETH2_TD_C_P
ETH2_TD_D_N: U37.11(TD_M_D) ; off-sheet ETH2_TD_D_N
ETH2_TD_D_P: U37.10(TD_P_D) ; off-sheet ETH2_TD_D_P
ETH2_XI: R212.2 R213.2 U37.20(XI)
ETH2_XO: R214.2 U37.19(XO)
ETH2_XTAL_XI: C189.2 R212.1 Y4.1
ETH2_XTAL_XO: C190.2 R214.1 Y4.3
MDIO_CLOCK: U37.42(MDC) ; off-sheet MDIO_CLOCK
MDIO_DATA: U37.41(MDIO) ; off-sheet MDIO_DATA
PHY2_RST: R418.1 U37.43(~{RESET}) U60.4(Y)
VDDA_ETH2_1V8: TP19.1 U37.13(VDDA1P8_1) U37.48(VDDA1P8_2)

Not connected (* = marked no-connect by the designer): U37 14(SON)* 15(SOP)* 16(SIP)* 17(SIN)* 21(JTAG_CLK/TX_ER)* 23(JTAG_TMS)* 24(JTAG_TDI/SD)*

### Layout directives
differential pair: ETH2_TD_A_N, ETH2_TD_A_P, ETH2_TD_B_N, ETH2_TD_B_P, ETH2_TD_C_N, ETH2_TD_C_P, ETH2_TD_D_N, ETH2_TD_D_P
mark named ETH2_TWISTED_PAIRS: ETH2_TD_A_N, ETH2_TD_A_P, ETH2_TD_B_N, ETH2_TD_B_P, ETH2_TD_C_N, ETH2_TD_C_P, ETH2_TD_D_N, ETH2_TD_D_P

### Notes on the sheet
- AM263P Ethernet PHY #2 - CPSW RGMII2/ICSSM_MII0
- PHY  Decoupling
- Note: CPSW / ICSSM Pinmux On AM263Px
  - selects between the CPSW RGMII2/MII2 interfaces and the PRU1 ICSSM MII0 interfaces
- (near U37) RGMII/MII PHY
- (near Y4) 25 MHz Crystal
- PHY Strap Resistors
- PHY_RST_LOGIC
- Oscillator Input Selection
- (near R214) Note: PHY Oscillator Input Selection
  - (default) select 25 MHz XTAL input to ETH2_XI/SO
  - optional select to disable 25 MHz XTAL and input CLK_OUT from PHY1
- Note: PHY Strap Resistor Selection
  - PHY ADDRESS = 0b1100, 0xC
  - Auto-negotiation, 10/100/1000 advertised, Auto-MDI-X
  - RGMII to Copper (1000BaseT/100Base-TX/10Base-Te)

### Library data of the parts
C189 C190 = CMP-0035228-1: as C112 on sheet PROC171_Ehernet_PHY_1
C191 C199 C205 = CMP-0007497-5: as C114 on sheet PROC171_Ehernet_PHY_1
C192 C200 C206 = CMP-0035343-1: as C115 on sheet PROC171_Ehernet_PHY_1
C193 C195 C197 C201 C203 C207 C209 = CMP-0006624-2: as C116 on sheet PROC171_Ehernet_PHY_1
C194 C196 C198 C202 C204 C208 C210 = CMP-0006659-2: as C117 on sheet PROC171_Ehernet_PHY_1
C263 = CMP-0006221-2: as C270 on sheet PROC171_Ehernet_PHY_1
FB5 FB6 = CMP-0089199-1: as FB3 on sheet PROC171_Ehernet_PHY_1
R196-R201 R212-R214 = CMP-0026992-3: as R100-R106 on sheet PROC171_Ehernet_PHY_1
R202 = CMP-0082348-1: as R107 on sheet PROC171_Ehernet_PHY_1
R203-R211 R215-R223 = CMP-0026237-2: as R108-R116 on sheet PROC171_Ehernet_PHY_1
R306 R417 = CMP-0026658-1: as R291 on sheet PROC171_Ehernet_PHY_1
R418 = CMP-0025958-3: as R425 on sheet PROC171_Ehernet_PHY_1
TP19 TP20 = CMP-0078143-3: TEST POINT.  No entry in BOM.
U37 = CMP-0091377-1: as U22 on sheet PROC171_Ehernet_PHY_1
U60 = CMP-0051588-2: as U65 on sheet PROC171_Ehernet_PHY_1
Y4 = CMP-0084811-1: as Y2 on sheet PROC171_Ehernet_PHY_1

## Sheet PROC171_Ehernet_RJ45_1.SchDoc
size 431 x 279 mm; Date: Not shown in title block; ApprovedBy: Not shown in title block; CheckedBy: Not shown in title block; Author: Not shown in title block; CompanyName: Not shown in title block; Engineer: Not shown in title block; Organization: Not shown in title block; Address1: Not shown in title block; Address2: Not shown in title block; Address3: Not shown in title block; Address4: Not shown in title block; DocumentNumber: 18; Revision: Use project parameter SCH_Rev; SheetNumber: 18; SheetTotal: 26; PageSetup: Record=PageOptions¦CenterHorizontal=True¦CenterVertical=True¦PrintScale=1.00¦XCorrection=1.00¦YCorrection=1.00¦PrintKind=0¦BorderSize=5000000¦LeftOffset=0¦BottomOffset=0¦Orientation=2¦PaperLength=1000¦PaperWidth=1000¦Scale=100¦PaperSource=15¦PrintQuality=600¦MediaType=1¦DitherType=10¦PaperKind=Letter¦PrintScaleMode=1

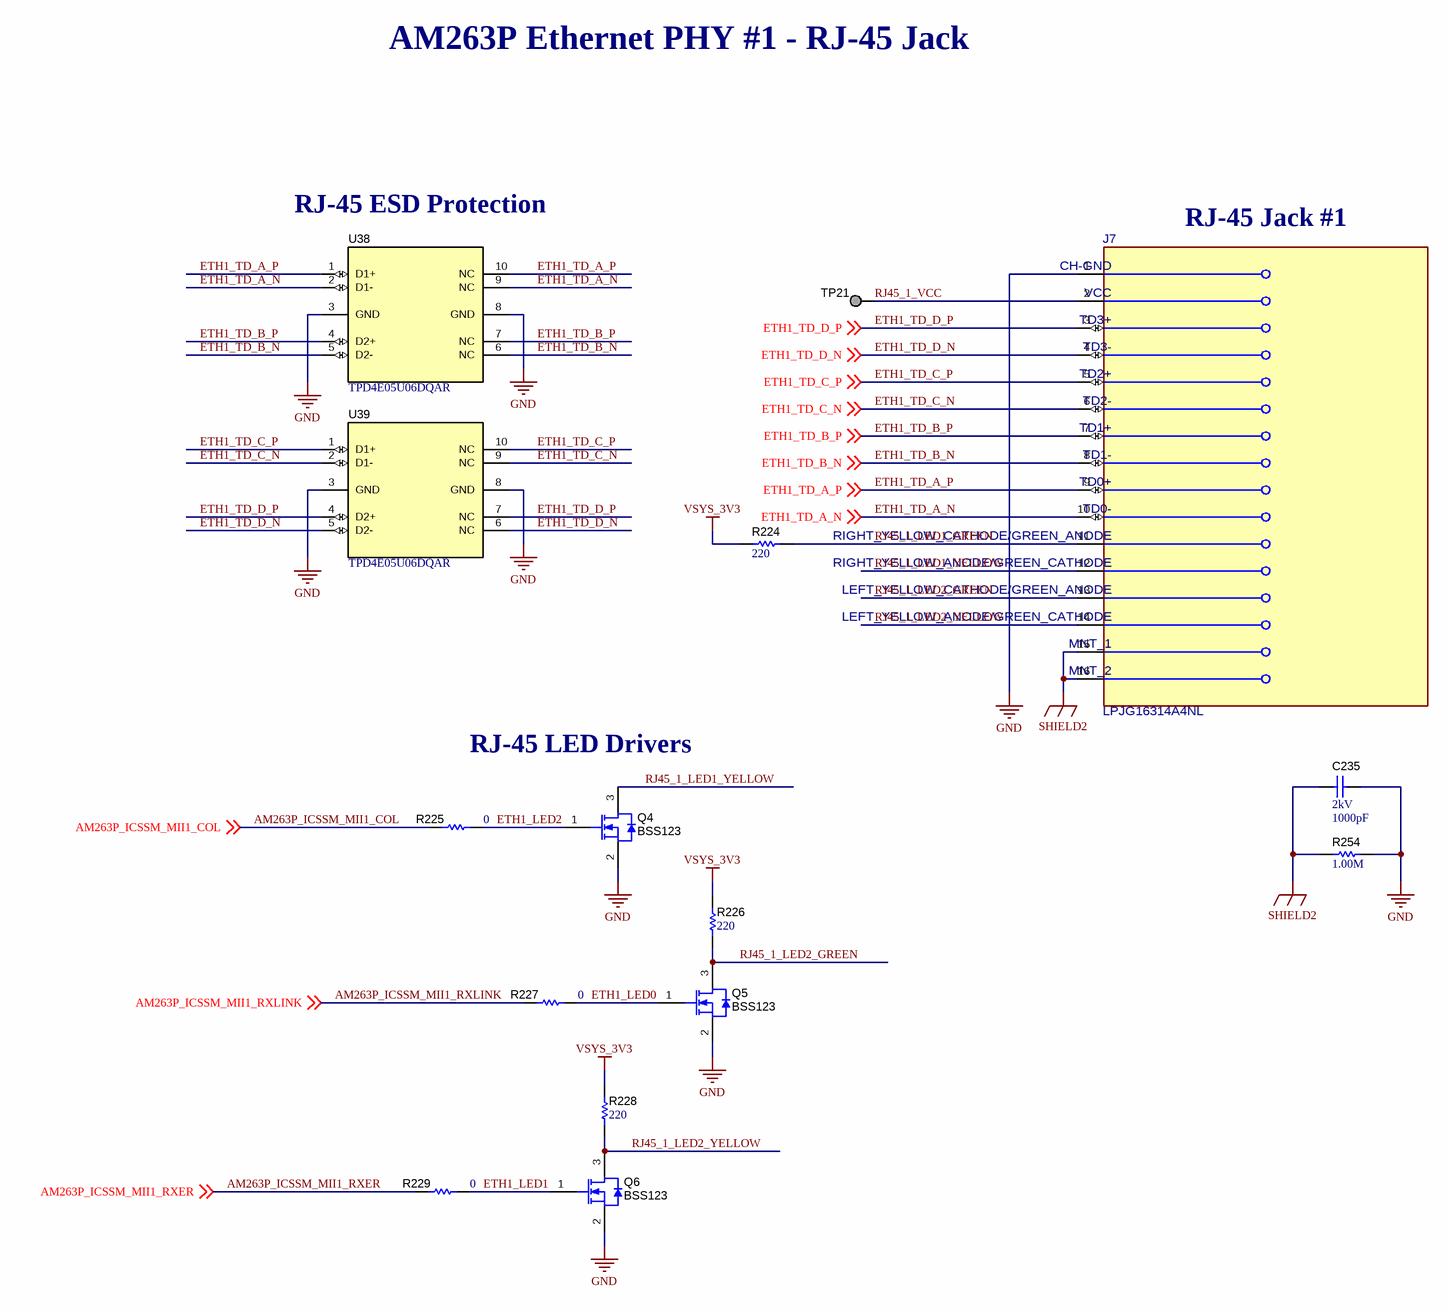
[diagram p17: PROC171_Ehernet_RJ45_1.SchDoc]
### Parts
C235  VDC_V: 2kV  ValueDisplayed: 1000pF  [1808]  (hidden comment: GR442QR73D102KW01L)
J7  LPJG16314A4NL  [FP-LPJG16314A4NL_CONN_RJ45-MFG]
Q4  BSS123  [SOT-23]
Q5  BSS123  [SOT-23]
Q6  BSS123  [SOT-23]
R224  ValueDisplayed: 220  [0402]  (hidden comment: CRCW0402220RJNED)
R225  ValueDisplayed: 0  [0402L]  (hidden comment: ERJ-2GE0R00X)
R226  ValueDisplayed: 220  [0402]  (hidden comment: CRCW0402220RJNED)
R227  ValueDisplayed: 0  [0402L]  (hidden comment: ERJ-2GE0R00X)
R228  ValueDisplayed: 220  [0402]  (hidden comment: CRCW0402220RJNED)
R229  ValueDisplayed: 0  [0402L]  (hidden comment: ERJ-2GE0R00X)
R254  ValueDisplayed: 1.00M  [0805_HV]  (hidden comment: ERJ-6ENF1004V)
TP21  TESTPOINT  [TP_25MIL-SMT]  (value not drawn)  (no BOM)
U38  TPD4E05U06DQAR  [DQA0010A]
U39  TPD4E05U06DQAR  [DQA0010A]

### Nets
GND: C235.1 J7.1(CH-GND) Q4.2(S) Q5.2(S) Q6.2(S) R254.2 U38.3(GND) U38.8(GND) U39.3(GND) U39.8(GND)
SHIELD2: C235.2 J7.15(MNT_1) J7.16(MNT_2) R254.1
VSYS_3V3: R224.1 R226.2 R228.2
AM263P_ICSSM_MII1_COL: R225.2 ; off-sheet AM263P_ICSSM_MII1_COL
AM263P_ICSSM_MII1_RXER: R229.2 ; off-sheet AM263P_ICSSM_MII1_RXER
AM263P_ICSSM_MII1_RXLINK: R227.2 ; off-sheet AM263P_ICSSM_MII1_RXLINK
ETH1_LED0: Q5.1(G) R227.1
ETH1_LED1: Q6.1(G) R229.1
ETH1_LED2: Q4.1(G) R225.1
ETH1_TD_A_N: J7.10(TD0-) U38.2(D1-) U38.9(NC) ; off-sheet ETH1_TD_A_N
ETH1_TD_A_P: J7.9(TD0+) U38.1(D1+) U38.10(NC) ; off-sheet ETH1_TD_A_P
ETH1_TD_B_N: J7.8(TD1-) U38.5(D2-) U38.6(NC) ; off-sheet ETH1_TD_B_N
ETH1_TD_B_P: J7.7(TD1+) U38.4(D2+) U38.7(NC) ; off-sheet ETH1_TD_B_P
ETH1_TD_C_N: J7.6(TD2-) U39.2(D1-) U39.9(NC) ; off-sheet ETH1_TD_C_N
ETH1_TD_C_P: J7.5(TD2+) U39.1(D1+) U39.10(NC) ; off-sheet ETH1_TD_C_P
ETH1_TD_D_N: J7.4(TD3-) U39.5(D2-) U39.6(NC) ; off-sheet ETH1_TD_D_N
ETH1_TD_D_P: J7.3(TD3+) U39.4(D2+) U39.7(NC) ; off-sheet ETH1_TD_D_P
RJ45_1_LED1_GREEN: J7.11(RIGHT_YELLOW_CATHODE/GREEN_ANODE) R224.2
RJ45_1_LED1_YELLOW: J7.12(RIGHT_YELLOW_ANODE/GREEN_CATHODE) Q4.3(D)
RJ45_1_LED2_GREEN: J7.13(LEFT_YELLOW_CATHODE/GREEN_ANODE) Q5.3(D) R226.1
RJ45_1_LED2_YELLOW: J7.14(LEFT_YELLOW_ANODE/GREEN_CATHODE) Q6.3(D) R228.1
RJ45_1_VCC: J7.2(VCC) TP21.1

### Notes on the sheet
- AM263P Ethernet PHY #1 - RJ-45 Jack
- RJ-45 ESD Protection
- RJ-45 Jack #1
- RJ-45 LED Drivers

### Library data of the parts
C235 = CMP-0009436-2: CAP, CERM, 1000 pF, 2000 V, +/- 10%, X7R, 1808; Manufacturer: MuRata; TaMin_C: -55°C; Polarized: N; SizeAreaWB_mm2: 16.5; Value1: Unknown; U/M: EA; Value: 1000pF; TaMax_C: 125°C; SizeZ_mm: 2.03; SizeX_mm: 4.5; SizeY_mm: 2; Value2: 2000V; SizeArea_mm2: 9; Cap_F: 1nF; AEC Category: Q200
J7 = CMP-0093483-1: RJ45 Connector with 1000 Base-TX Inetgrated Magnetic; Manufacturer: Link-PP; SizeZ_mm: 13.7mm; AEC Qualified: No; DUT-Pitch_mm: 1.27mm; Conn Gender: Female; Is Female: yes; ContactFinish: Gold; Conn Orientation: Horizontal
Q4-Q6 = CMP-0000947-2: MOSFET, N-CH, 100 V, 0.17 A, SOT-23; Alternate Manufacturer: None; Manufacturer: Fairchild Semiconductor; SizeZ_mm: 1.1; ChType: N; Value2: 1.8 nC; Value1: 1; VdsMax_V: 100V; SizeX_mm: 2.5; SizeY_mm: 3; Vgs_V: 20V; Value: 100V; Rdson45_ohm: 10; SizeArea_mm2: 7.5; AEC Category: Q101; IdsMax_A: 1.7dA; SizeAreaWB_mm2: 14; U/M: EA; QgTyp_nC: 1.8
R224 R226 R228 = CMP-0026878-3: RES, 220, 5%, 0.063 W, AEC-Q200 Grade 0, 0402; Manufacturer: Vishay-Dale; Power_W: 63mW; TempCo: 200 ppm/C; Value_Code: 220R; Value: 220; EIA_Code: E24; SizeX_mm: 1; SizeY_mm: 0.5; SizeZ_mm: 0.6; Value2: 0.063W; AEC Qualified: Y; VDC_V: 50V; AEC Category: Q200; AEC Grade: 0
R225 R227 R229 = CMP-0026992-3: as R100-R106 on sheet PROC171_Ehernet_PHY_1
R254 = CMP-0021522-3: RES, 1.00 M, 1%, 0.125 W, AEC-Q200 Grade 0, 0805; Manufacturer: Panasonic; Power_W: 125mW; TempCo: 100 ppm/C; Value_Code: 1M00; Value: 1.00Meg; EIA_Code: E96; Res_ohm: 1M; SizeX_mm: 2; SizeY_mm: 1.25; SizeZ_mm: 1.45; Value2: 0.125W; SizeArea_mm2: 2.5; AEC Qualified: Y; AEC Category: Q200; AEC Grade: 0; SizeAreaWB_mm2: 6.75
TP21 = CMP-0078143-3: TEST POINT.  No entry in BOM.
U38 U39 = CMP-0073613-3: 4-Channel Ultra-Low-Capacitance IEC ESD Protection Diode, DQA0010A (USON-10); Alternate Manufacturer: Texas Instruments; Green_Lifecycle: Active; SizeAreaWB_mm2: 7.0; Green_REACh: Passed; SizeZ_mm: 0.55; SizeX_mm: 1.0; SizeY_mm: 2.5; CompType: IC; AEC Category: Q200; AEC Qualified: N

## Sheet PROC171_Ehernet_RJ45_2.SchDoc
size 431 x 279 mm; Date: Not shown in title block; ApprovedBy: Not shown in title block; CheckedBy: Not shown in title block; Author: Not shown in title block; CompanyName: Not shown in title block; Engineer: Not shown in title block; Organization: Not shown in title block; Address1: Not shown in title block; Address2: Not shown in title block; Address3: Not shown in title block; Address4: Not shown in title block; DocumentNumber: 19; Revision: Use project parameter SCH_Rev; SheetNumber: 19; SheetTotal: 26; PageSetup: Record=PageOptions¦CenterHorizontal=True¦CenterVertical=True¦PrintScale=1.00¦XCorrection=1.00¦YCorrection=1.00¦PrintKind=0¦BorderSize=5000000¦LeftOffset=0¦BottomOffset=0¦Orientation=2¦PaperLength=1000¦PaperWidth=1000¦Scale=100¦PaperSource=15¦PrintQuality=600¦MediaType=1¦DitherType=10¦PaperKind=Letter¦PrintScaleMode=1

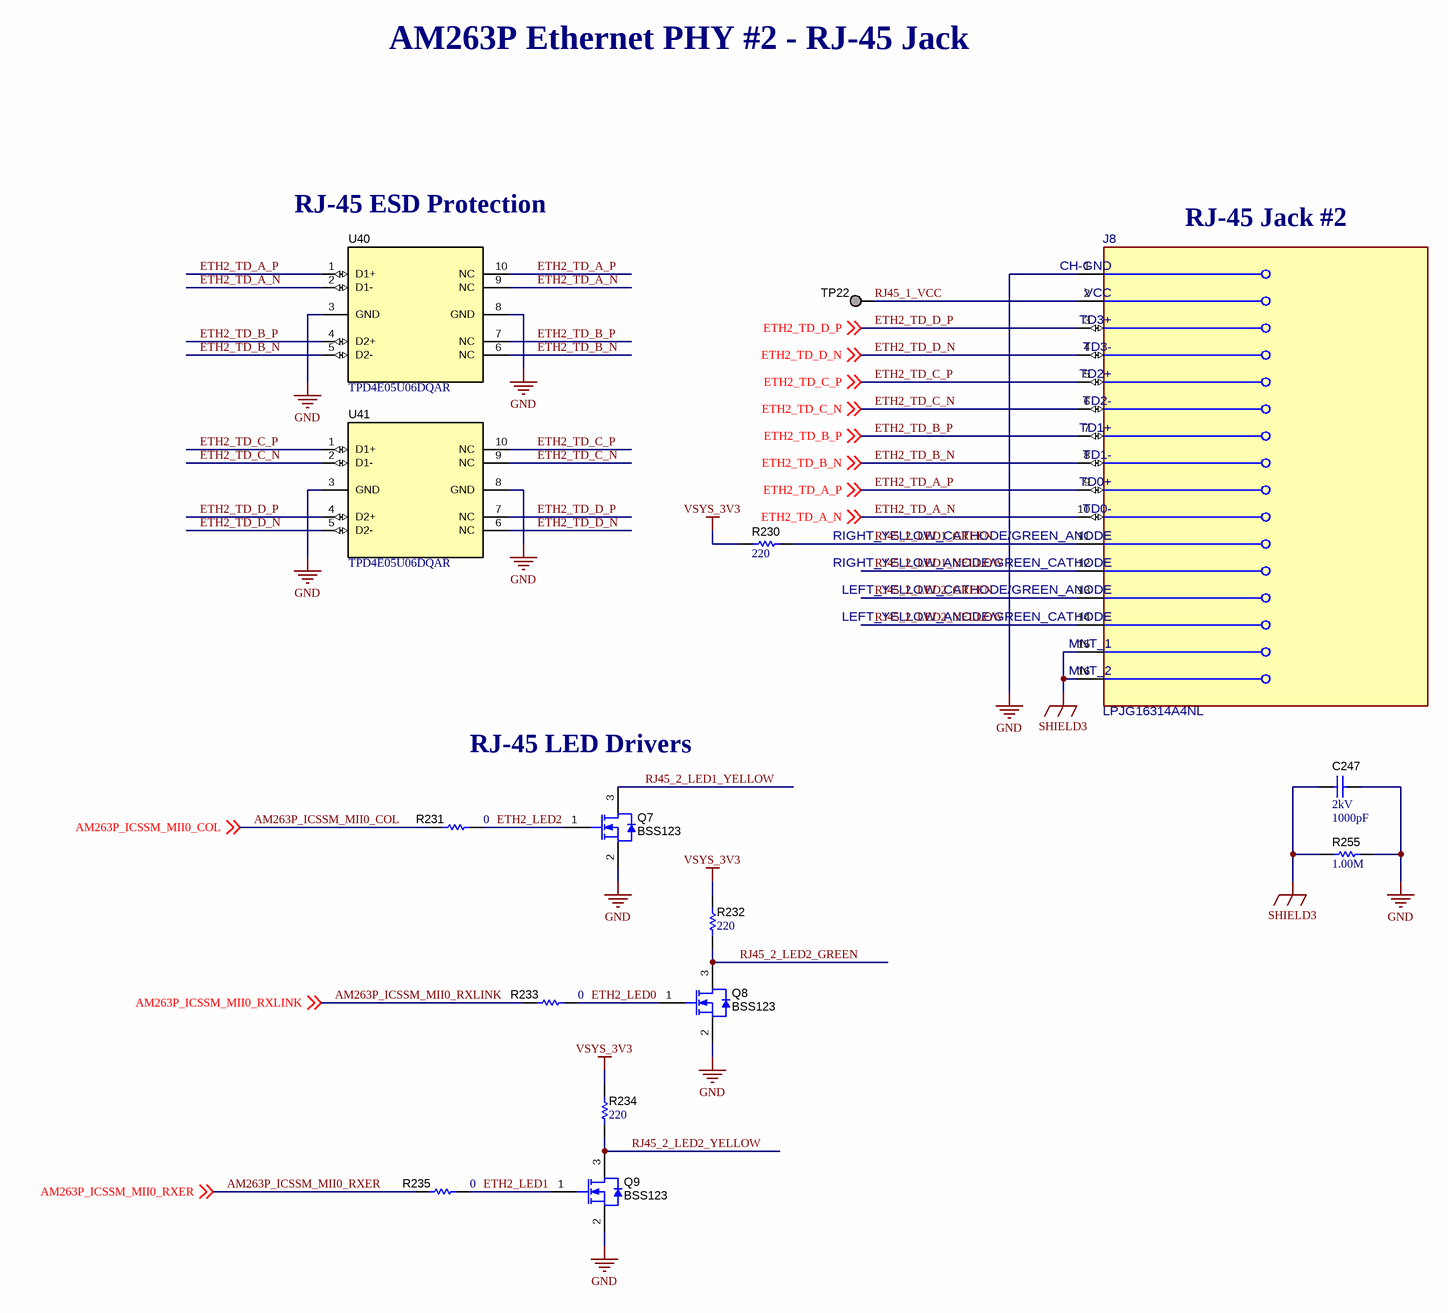
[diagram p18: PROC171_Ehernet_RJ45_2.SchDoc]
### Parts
C247  VDC_V: 2kV  ValueDisplayed: 1000pF  [1808]  (hidden comment: GR442QR73D102KW01L)
J8  LPJG16314A4NL  [FP-LPJG16314A4NL_CONN_RJ45-MFG]
Q7  BSS123  [SOT-23]
Q8  BSS123  [SOT-23]
Q9  BSS123  [SOT-23]
R230  ValueDisplayed: 220  [0402]  (hidden comment: CRCW0402220RJNED)
R231  ValueDisplayed: 0  [0402L]  (hidden comment: ERJ-2GE0R00X)
R232  ValueDisplayed: 220  [0402]  (hidden comment: CRCW0402220RJNED)
R233  ValueDisplayed: 0  [0402L]  (hidden comment: ERJ-2GE0R00X)
R234  ValueDisplayed: 220  [0402]  (hidden comment: CRCW0402220RJNED)
R235  ValueDisplayed: 0  [0402L]  (hidden comment: ERJ-2GE0R00X)
R255  ValueDisplayed: 1.00M  [0805_HV]  (hidden comment: ERJ-6ENF1004V)
TP22  TESTPOINT  [TP_25MIL-SMT]  (value not drawn)  (no BOM)
U40  TPD4E05U06DQAR  [DQA0010A]
U41  TPD4E05U06DQAR  [DQA0010A]

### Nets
GND: C247.1 J8.1(CH-GND) Q7.2(S) Q8.2(S) Q9.2(S) R255.2 U40.3(GND) U40.8(GND) U41.3(GND) U41.8(GND)
SHIELD3: C247.2 J8.15(MNT_1) J8.16(MNT_2) R255.1
VSYS_3V3: R230.1 R232.2 R234.2
AM263P_ICSSM_MII0_COL: R231.2 ; off-sheet AM263P_ICSSM_MII0_COL
AM263P_ICSSM_MII0_RXER: R235.2 ; off-sheet AM263P_ICSSM_MII0_RXER
AM263P_ICSSM_MII0_RXLINK: R233.2 ; off-sheet AM263P_ICSSM_MII0_RXLINK
ETH2_LED0: Q8.1(G) R233.1
ETH2_LED1: Q9.1(G) R235.1
ETH2_LED2: Q7.1(G) R231.1
ETH2_TD_A_N: J8.10(TD0-) U40.2(D1-) U40.9(NC) ; off-sheet ETH2_TD_A_N
ETH2_TD_A_P: J8.9(TD0+) U40.1(D1+) U40.10(NC) ; off-sheet ETH2_TD_A_P
ETH2_TD_B_N: J8.8(TD1-) U40.5(D2-) U40.6(NC) ; off-sheet ETH2_TD_B_N
ETH2_TD_B_P: J8.7(TD1+) U40.4(D2+) U40.7(NC) ; off-sheet ETH2_TD_B_P
ETH2_TD_C_N: J8.6(TD2-) U41.2(D1-) U41.9(NC) ; off-sheet ETH2_TD_C_N
ETH2_TD_C_P: J8.5(TD2+) U41.1(D1+) U41.10(NC) ; off-sheet ETH2_TD_C_P
ETH2_TD_D_N: J8.4(TD3-) U41.5(D2-) U41.6(NC) ; off-sheet ETH2_TD_D_N
ETH2_TD_D_P: J8.3(TD3+) U41.4(D2+) U41.7(NC) ; off-sheet ETH2_TD_D_P
RJ45_1_VCC: J8.2(VCC) TP22.1
RJ45_2_LED1_GREEN: J8.11(RIGHT_YELLOW_CATHODE/GREEN_ANODE) R230.2
RJ45_2_LED1_YELLOW: J8.12(RIGHT_YELLOW_ANODE/GREEN_CATHODE) Q7.3(D)
RJ45_2_LED2_GREEN: J8.13(LEFT_YELLOW_CATHODE/GREEN_ANODE) Q8.3(D) R232.1
RJ45_2_LED2_YELLOW: J8.14(LEFT_YELLOW_ANODE/GREEN_CATHODE) Q9.3(D) R234.1

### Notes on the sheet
- AM263P Ethernet PHY #2 - RJ-45 Jack
- RJ-45 ESD Protection
- RJ-45 Jack #2
- RJ-45 LED Drivers

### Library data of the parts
C247 = CMP-0009436-2: as C235 on sheet PROC171_Ehernet_RJ45_1
J8 = CMP-0093483-1: as J7 on sheet PROC171_Ehernet_RJ45_1
Q7-Q9 = CMP-0000947-2: as Q4 on sheet PROC171_Ehernet_RJ45_1
R230 R232 R234 = CMP-0026878-3: as R224 on sheet PROC171_Ehernet_RJ45_1
R231 R233 R235 = CMP-0026992-3: as R100-R106 on sheet PROC171_Ehernet_PHY_1
R255 = CMP-0021522-3: as R254 on sheet PROC171_Ehernet_RJ45_1
TP22 = CMP-0078143-3: TEST POINT.  No entry in BOM.
U40 U41 = CMP-0073613-3: as U38 on sheet PROC171_Ehernet_RJ45_1

## Sheet PROC171_Boosterpack_Headers.SchDoc
size 431 x 279 mm; Date: Not shown in title block; ApprovedBy: Not shown in title block; CheckedBy: Not shown in title block; Author: Not shown in title block; CompanyName: Not shown in title block; Engineer: Not shown in title block; Organization: Not shown in title block; Address1: Not shown in title block; Address2: Not shown in title block; Address3: Not shown in title block; Address4: Not shown in title block; DocumentNumber: 20; Revision: Use project parameter SCH_Rev; SheetNumber: 20; SheetTotal: 26; PageSetup: Record=PageOptions¦CenterHorizontal=True¦CenterVertical=True¦PrintScale=1.00¦XCorrection=1.00¦YCorrection=1.00¦PrintKind=0¦BorderSize=5000000¦LeftOffset=0¦BottomOffset=0¦Orientation=2¦PaperLength=1000¦PaperWidth=1000¦Scale=100¦PaperSource=15¦PrintQuality=600¦MediaType=1¦DitherType=10¦PaperKind=Letter¦PrintScaleMode=1

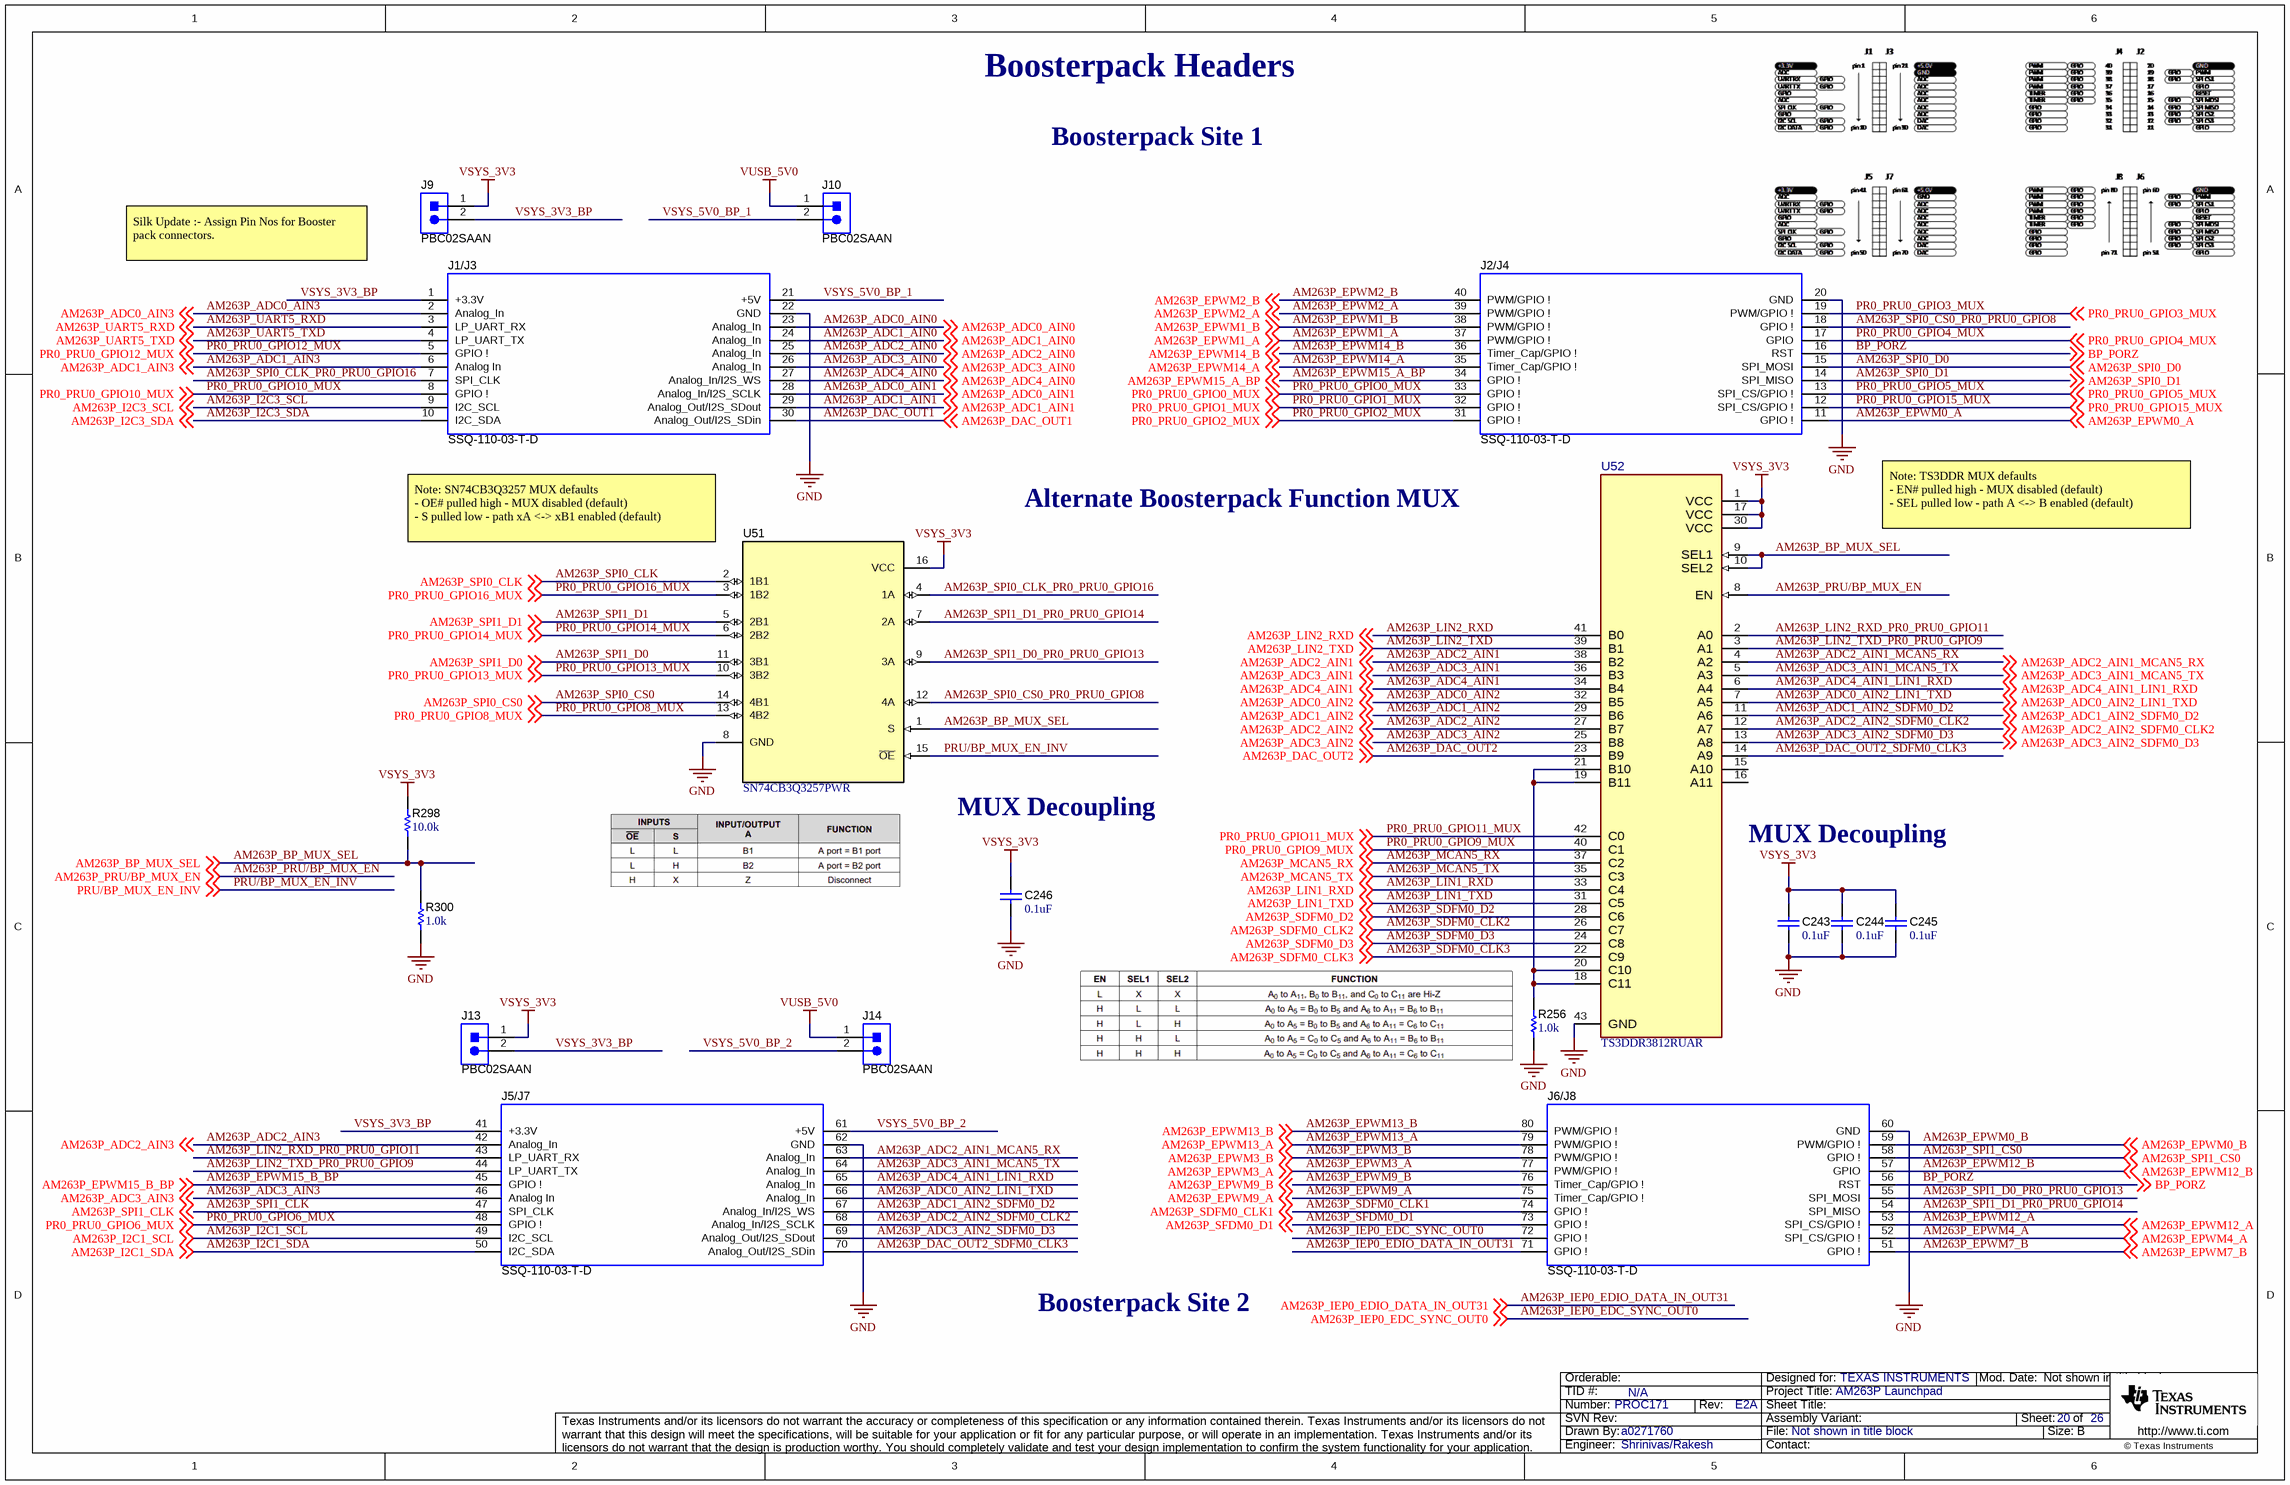
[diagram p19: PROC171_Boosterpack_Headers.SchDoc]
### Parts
C243  ValueDisplayed: 0.1uF  [0402]  (hidden comment: GRM155R71E104KE14D)
C244  ValueDisplayed: 0.1uF  [0402]  (hidden comment: GRM155R71E104KE14D)
C245  ValueDisplayed: 0.1uF  [0402]  (hidden comment: GRM155R71E104KE14D)
C246  ValueDisplayed: 0.1uF  [0402]  (hidden comment: GRM155R71E104KE14D)
J1/J3  SSQ-110-03-T-D  [BoosterPack_40pin_J1J3]
J2/J4  SSQ-110-03-T-D  [BoosterPack_40pin_J2J4]
J5/J7  SSQ-110-03-T-D  [BoosterPack_40pin_J5J7]
J6/J8  SSQ-110-03-T-D  [BoosterPack_40pin_J6J8]
J9  PBC02SAAN  [Sullins_PBC02SAAN]
J10  PBC02SAAN  [Sullins_PBC02SAAN]
J13  PBC02SAAN  [Sullins_PBC02SAAN]
J14  PBC02SAAN  [Sullins_PBC02SAAN]
R256  ValueDisplayed: 1.0k  [0402]  (hidden comment: ERJ-2GEJ102X)
R298  ValueDisplayed: 10.0k  [0402]  (hidden comment: ERJ-2RKF1002X)
R300  ValueDisplayed: 1.0k  [0402]  (hidden comment: ERJ-2GEJ102X)
U51  SN74CB3Q3257PWR  [PW0016A_L]
U52  TS3DDR3812RUAR  [RUA0042A-MFG]

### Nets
GND: C243.1 C244.1 C245.1 C246.1 J1/J3.22(GND) J2/J4.20(GND) J5/J7.62(GND) J6/J8.60(GND) R256.1 R300.1 U51.8(GND) U52.43(GND)
VSYS_3V3: C243.2 C244.2 C245.2 C246.2 J9.1 J13.1 R298.1 U51.16(VCC) U52.1(VCC) U52.17(VCC) U52.30(VCC)
VUSB_5V0: J10.1 J14.1
AM263P_ADC0_AIN0: J1/J3.23(Analog_In) ; off-sheet AM263P_ADC0_AIN0
AM263P_ADC0_AIN1: J1/J3.28(Analog_In/I2S_SCLK) ; off-sheet AM263P_ADC0_AIN1
AM263P_ADC0_AIN2: U52.32(B5) ; off-sheet AM263P_ADC0_AIN2
AM263P_ADC0_AIN2_LIN1_TXD: J5/J7.66(Analog_In) U52.7(A5) ; off-sheet AM263P_ADC0_AIN2_LIN1_TXD
AM263P_ADC0_AIN3: J1/J3.2(Analog_In) ; off-sheet AM263P_ADC0_AIN3
AM263P_ADC1_AIN0: J1/J3.24(Analog_In) ; off-sheet AM263P_ADC1_AIN0
AM263P_ADC1_AIN1: J1/J3.29(Analog_Out/I2S_SDout) ; off-sheet AM263P_ADC1_AIN1
AM263P_ADC1_AIN2: U52.29(B6) ; off-sheet AM263P_ADC1_AIN2
AM263P_ADC1_AIN2_SDFM0_D2: J5/J7.67(Analog_In/I2S_WS) U52.11(A6) ; off-sheet AM263P_ADC1_AIN2_SDFM0_D2
AM263P_ADC1_AIN3: J1/J3.6(Analog_In) ; off-sheet AM263P_ADC1_AIN3
AM263P_ADC2_AIN0: J1/J3.25(Analog_In) ; off-sheet AM263P_ADC2_AIN0
AM263P_ADC2_AIN1: U52.38(B2) ; off-sheet AM263P_ADC2_AIN1
AM263P_ADC2_AIN1_MCAN5_RX: J5/J7.63(Analog_In) U52.4(A2) ; off-sheet AM263P_ADC2_AIN1_MCAN5_RX
AM263P_ADC2_AIN2: U52.27(B7) ; off-sheet AM263P_ADC2_AIN2
AM263P_ADC2_AIN2_SDFM0_CLK2: J5/J7.68(Analog_In/I2S_SCLK) U52.12(A7) ; off-sheet AM263P_ADC2_AIN2_SDFM0_CLK2
AM263P_ADC2_AIN3: J5/J7.42(Analog_In) ; off-sheet AM263P_ADC2_AIN3
AM263P_ADC3_AIN0: J1/J3.26(Analog_In) ; off-sheet AM263P_ADC3_AIN0
AM263P_ADC3_AIN1: U52.36(B3) ; off-sheet AM263P_ADC3_AIN1
AM263P_ADC3_AIN1_MCAN5_TX: J5/J7.64(Analog_In) U52.5(A3) ; off-sheet AM263P_ADC3_AIN1_MCAN5_TX
AM263P_ADC3_AIN2: U52.25(B8) ; off-sheet AM263P_ADC3_AIN2
AM263P_ADC3_AIN2_SDFM0_D3: J5/J7.69(Analog_Out/I2S_SDout) U52.13(A8) ; off-sheet AM263P_ADC3_AIN2_SDFM0_D3
AM263P_ADC3_AIN3: J5/J7.46(Analog_In) ; off-sheet AM263P_ADC3_AIN3
AM263P_ADC4_AIN0: J1/J3.27(Analog_In/I2S_WS) ; off-sheet AM263P_ADC4_AIN0
AM263P_ADC4_AIN1: U52.34(B4) ; off-sheet AM263P_ADC4_AIN1
AM263P_ADC4_AIN1_LIN1_RXD: J5/J7.65(Analog_In) U52.6(A4) ; off-sheet AM263P_ADC4_AIN1_LIN1_RXD
AM263P_BP_MUX_SEL: R298.2 R300.2 U51.1(S) U52.9(SEL1) U52.10(SEL2) ; off-sheet AM263P_BP_MUX_SEL
AM263P_DAC_OUT1: J1/J3.30(Analog_Out/I2S_SDin) ; off-sheet AM263P_DAC_OUT1
AM263P_DAC_OUT2: U52.23(B9) ; off-sheet AM263P_DAC_OUT2
AM263P_DAC_OUT2_SDFM0_CLK3: J5/J7.70(Analog_Out/I2S_SDin) U52.14(A9)
AM263P_EPWM0_A: J2/J4.11(GPIO_!) ; off-sheet AM263P_EPWM0_A
AM263P_EPWM0_B: J6/J8.59(PWM/GPIO_!) ; off-sheet AM263P_EPWM0_B
AM263P_EPWM1_A: J2/J4.37(PWM/GPIO_!) ; off-sheet AM263P_EPWM1_A
AM263P_EPWM1_B: J2/J4.38(PWM/GPIO_!) ; off-sheet AM263P_EPWM1_B
AM263P_EPWM2_A: J2/J4.39(PWM/GPIO_!) ; off-sheet AM263P_EPWM2_A
AM263P_EPWM2_B: J2/J4.40(PWM/GPIO_!) ; off-sheet AM263P_EPWM2_B
AM263P_EPWM3_A: J6/J8.77(PWM/GPIO_!) ; off-sheet AM263P_EPWM3_A
AM263P_EPWM3_B: J6/J8.78(PWM/GPIO_!) ; off-sheet AM263P_EPWM3_B
AM263P_EPWM4_A: J6/J8.52(SPI_CS/GPIO_!) ; off-sheet AM263P_EPWM4_A
AM263P_EPWM7_B: J6/J8.51(GPIO_!) ; off-sheet AM263P_EPWM7_B
AM263P_EPWM9_A: J6/J8.75(Timer_Cap/GPIO_!) ; off-sheet AM263P_EPWM9_A
AM263P_EPWM9_B: J6/J8.76(Timer_Cap/GPIO_!) ; off-sheet AM263P_EPWM9_B
AM263P_EPWM12_A: J6/J8.53(SPI_CS/GPIO_!) ; off-sheet AM263P_EPWM12_A
AM263P_EPWM12_B: J6/J8.57(GPIO) ; off-sheet AM263P_EPWM12_B
AM263P_EPWM13_A: J6/J8.79(PWM/GPIO_!) ; off-sheet AM263P_EPWM13_A
AM263P_EPWM13_B: J6/J8.80(PWM/GPIO_!) ; off-sheet AM263P_EPWM13_B
AM263P_EPWM14_A: J2/J4.35(Timer_Cap/GPIO_!) ; off-sheet AM263P_EPWM14_A
AM263P_EPWM14_B: J2/J4.36(Timer_Cap/GPIO_!) ; off-sheet AM263P_EPWM14_B
AM263P_EPWM15_A_BP: J2/J4.34(GPIO_!) ; off-sheet AM263P_EPWM15_A_BP
AM263P_EPWM15_B_BP: J5/J7.45(GPIO_!) ; off-sheet AM263P_EPWM15_B_BP
AM263P_I2C1_SCL: J5/J7.49(I2C_SCL) ; off-sheet AM263P_I2C1_SCL
AM263P_I2C1_SDA: J5/J7.50(I2C_SDA) ; off-sheet AM263P_I2C1_SDA
AM263P_I2C3_SCL: J1/J3.9(I2C_SCL) ; off-sheet AM263P_I2C3_SCL
AM263P_I2C3_SDA: J1/J3.10(I2C_SDA) ; off-sheet AM263P_I2C3_SDA
AM263P_IEP0_EDC_SYNC_OUT0: J6/J8.72(GPIO_!) ; off-sheet AM263P_IEP0_EDC_SYNC_OUT0
AM263P_IEP0_EDIO_DATA_IN_OUT31: J6/J8.71(GPIO_!) ; off-sheet AM263P_IEP0_EDIO_DATA_IN_OUT31
AM263P_LIN1_RXD: U52.33(C4) ; off-sheet AM263P_LIN1_RXD
AM263P_LIN1_TXD: U52.31(C5) ; off-sheet AM263P_LIN1_TXD
AM263P_LIN2_RXD: U52.41(B0) ; off-sheet AM263P_LIN2_RXD
AM263P_LIN2_RXD_PR0_PRU0_GPIO11: J5/J7.43(LP_UART_RX) U52.2(A0)
AM263P_LIN2_TXD: U52.39(B1) ; off-sheet AM263P_LIN2_TXD
AM263P_LIN2_TXD_PR0_PRU0_GPIO9: J5/J7.44(LP_UART_TX) U52.3(A1)
AM263P_MCAN5_RX: U52.37(C2) ; off-sheet AM263P_MCAN5_RX
AM263P_MCAN5_TX: U52.35(C3) ; off-sheet AM263P_MCAN5_TX
AM263P_PRU/BP_MUX_EN: U52.8(EN) ; off-sheet AM263P_PRU/BP_MUX_EN
AM263P_SDFM0_CLK1: J6/J8.74(GPIO_!) ; off-sheet AM263P_SDFM0_CLK1
AM263P_SDFM0_CLK2: U52.26(C7) ; off-sheet AM263P_SDFM0_CLK2
AM263P_SDFM0_CLK3: U52.22(C9) ; off-sheet AM263P_SDFM0_CLK3
AM263P_SDFM0_D2: U52.28(C6) ; off-sheet AM263P_SDFM0_D2
AM263P_SDFM0_D3: U52.24(C8) ; off-sheet AM263P_SDFM0_D3
AM263P_SFDM0_D1: J6/J8.73(GPIO_!) ; off-sheet AM263P_SFDM0_D1
AM263P_SPI0_CLK: U51.2(1B1) ; off-sheet AM263P_SPI0_CLK
AM263P_SPI0_CLK_PR0_PRU0_GPIO16: J1/J3.7(SPI_CLK) U51.4(1A)
AM263P_SPI0_CS0: U51.14(4B1) ; off-sheet AM263P_SPI0_CS0
AM263P_SPI0_CS0_PR0_PRU0_GPIO8: J2/J4.18(GPIO_!) U51.12(4A)
AM263P_SPI0_D0: J2/J4.15(SPI_MOSI) ; off-sheet AM263P_SPI0_D0
AM263P_SPI0_D1: J2/J4.14(SPI_MISO) ; off-sheet AM263P_SPI0_D1
AM263P_SPI1_CLK: J5/J7.47(SPI_CLK) ; off-sheet AM263P_SPI1_CLK
AM263P_SPI1_CS0: J6/J8.58(GPIO_!) ; off-sheet AM263P_SPI1_CS0
AM263P_SPI1_D0: U51.11(3B1) ; off-sheet AM263P_SPI1_D0
AM263P_SPI1_D0_PR0_PRU0_GPIO13: J6/J8.55(SPI_MOSI) U51.9(3A)
AM263P_SPI1_D1: U51.5(2B1) ; off-sheet AM263P_SPI1_D1
AM263P_SPI1_D1_PR0_PRU0_GPIO14: J6/J8.54(SPI_MISO) U51.7(2A)
AM263P_UART5_RXD: J1/J3.3(LP_UART_RX) ; off-sheet AM263P_UART5_RXD
AM263P_UART5_TXD: J1/J3.4(LP_UART_TX) ; off-sheet AM263P_UART5_TXD
BP_PORZ: J2/J4.16(RST) J6/J8.56(RST) ; off-sheet BP_PORZ
PR0_PRU0_GPIO0_MUX: J2/J4.33(GPIO_!) ; off-sheet PR0_PRU0_GPIO0_MUX
PR0_PRU0_GPIO1_MUX: J2/J4.32(GPIO_!) ; off-sheet PR0_PRU0_GPIO1_MUX
PR0_PRU0_GPIO2_MUX: J2/J4.31(GPIO_!) ; off-sheet PR0_PRU0_GPIO2_MUX
PR0_PRU0_GPIO3_MUX: J2/J4.19(PWM/GPIO_!) ; off-sheet PR0_PRU0_GPIO3_MUX
PR0_PRU0_GPIO4_MUX: J2/J4.17(GPIO) ; off-sheet PR0_PRU0_GPIO4_MUX
PR0_PRU0_GPIO5_MUX: J2/J4.13(SPI_CS/GPIO_!) ; off-sheet PR0_PRU0_GPIO5_MUX
PR0_PRU0_GPIO6_MUX: J5/J7.48(GPIO_!) ; off-sheet PR0_PRU0_GPIO6_MUX
PR0_PRU0_GPIO8_MUX: U51.13(4B2) ; off-sheet PR0_PRU0_GPIO8_MUX
PR0_PRU0_GPIO9_MUX: U52.40(C1) ; off-sheet PR0_PRU0_GPIO9_MUX
PR0_PRU0_GPIO10_MUX: J1/J3.8(GPIO_!) ; off-sheet PR0_PRU0_GPIO10_MUX
PR0_PRU0_GPIO11_MUX: U52.42(C0) ; off-sheet PR0_PRU0_GPIO11_MUX
PR0_PRU0_GPIO12_MUX: J1/J3.5(GPIO_!) ; off-sheet PR0_PRU0_GPIO12_MUX
PR0_PRU0_GPIO13_MUX: U51.10(3B2) ; off-sheet PR0_PRU0_GPIO13_MUX
PR0_PRU0_GPIO14_MUX: U51.6(2B2) ; off-sheet PR0_PRU0_GPIO14_MUX
PR0_PRU0_GPIO15_MUX: J2/J4.12(SPI_CS/GPIO_!) ; off-sheet PR0_PRU0_GPIO15_MUX
PR0_PRU0_GPIO16_MUX: U51.3(1B2) ; off-sheet PR0_PRU0_GPIO16_MUX
PRU/BP_MUX_EN_INV: U51.15(~{OE}) ; off-sheet PRU/BP_MUX_EN_INV
VSYS_3V3_BP: J1/J3.1(+3.3V) J5/J7.41(+3.3V) J9.2 J13.2
VSYS_5V0_BP_1: J1/J3.21(+5V) J10.2
VSYS_5V0_BP_2: J5/J7.61(+5V) J14.2
NetR256_2: R256.2 U52.18(C11) U52.19(B11) U52.20(C10) U52.21(B10)

Not connected (* = marked no-connect by the designer): U52 15(A10) 16(A11)

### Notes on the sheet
- Boosterpack Headers
- Boosterpack Site 1
- Silk Update :- Assign Pin Nos for Booster pack connectors.
- Note: SN74CB3Q3257 MUX defaults
  - OE# pulled high - MUX disabled (default)
  - S pulled low - path xA <-> xB1 enabled (default)
- Alternate Boosterpack Function MUX
- Note: TS3DDR MUX defaults
  - EN# pulled high - MUX disabled (default)
  - SEL pulled low - path A <-> B enabled (default)
- MUX Decoupling
- (near U52) MUX Decoupling
- Boosterpack Site 2

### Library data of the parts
C243-C246 = CMP-0006659-2: as C240-C242 on sheet PROC171_Ehernet_PHY_1
J1/J3 = CMP-0003837-4: Receptacle, 2.54mm, 10x2, Tin, TH; Alternate PartNumber: CRD-081413-A-G; Manufacturer: Samtec; Alternate Manufacturer: Major League Electronics; Note: Booster Pack 40 pin J1 and J3; Green_Lifecycle: Active; Green_REACh: Incomplete
J2/J4 = CMP-0078266-4: Receptacle, 2.54mm, 10x2, Tin, TH; Alternate PartNumber: CRD-081413-A-G; Manufacturer: Samtec; Alternate Manufacturer: Major League Electronics; Note: Booster Pack 40 pin J2 and J4; Green_REACh: Incomplete; Green_Lifecycle: Active
J5/J7 = CMP-0081070-3: Receptacle, 2.54mm, 10x2, Tin, TH; Alternate PartNumber: CRD-081413-A-G; Manufacturer: Samtec; Alternate Manufacturer: Major League Electronics; Note: Booster Pack 40 pin J5 and J7; Green_REACh: Incomplete; Green_Lifecycle: Active
J6/J8 = CMP-0081071-3: Receptacle, 2.54mm, 10x2, Tin, TH; Alternate PartNumber: CRD-081413-A-G; Manufacturer: Samtec; Alternate Manufacturer: Major League Electronics; Note: Booster Pack 40 pin J6 and J8; Green_REACh: Incomplete; Green_Lifecycle: Active
J9 J10 J13 J14 = CMP-0054566-1: Header, 100mil, 2x1, Gold, TH; Manufacturer: Sullins Connector Solutions; CNHeader: TRUE; Current_A: 3A; Green_Lifecycle: Active; Shrouded: N; Gender: Male; Green_REACh: Passed; Voltage_V: 1.8kV; Row_Count: 1; Pitch_mm: 2.54; CT: FALSE; Cert_UL: Y
R256 R300 = CMP-0078193-1: as R293 on sheet PROC171_Ehernet_PHY_1
R298 = CMP-0026658-1: as R291 on sheet PROC171_Ehernet_PHY_1
U51 = CMP-0076540-1: 4-Bit One-of-2 FET Multiplexer/Demultiplexer 2.5-V/3.3-V Low-Voltage, High-Bandwidth Bus Switch, PW0016A (TSSOP-16); Manufacturer: Texas Instruments; SizeAreaWB_mm2: 58.8; SizeArea_mm2: 32.0; SizeZ_mm: 1.2; SizeY_mm: 5.0; U/M: EA; CompType: IC; SizeX_mm: 6.4
U52 = CMP-0093539-2: as U50 on sheet PROC171_Ehernet_PHY_1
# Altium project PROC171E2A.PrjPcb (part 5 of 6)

## Sheet PROC171_Breakout_Headers.SchDoc
size 431 x 279 mm; Date: Not shown in title block; ApprovedBy: Not shown in title block; CheckedBy: Not shown in title block; Author: Not shown in title block; CompanyName: Not shown in title block; Engineer: Not shown in title block; Organization: Not shown in title block; Address1: Not shown in title block; Address2: Not shown in title block; Address3: Not shown in title block; Address4: Not shown in title block; DocumentNumber: 21; Revision: Use project parameter SCH_Rev; SheetNumber: 21; SheetTotal: 26; PageSetup: Record=PageOptions¦CenterHorizontal=True¦CenterVertical=True¦PrintScale=1.00¦XCorrection=1.00¦YCorrection=1.00¦PrintKind=0¦BorderSize=5000000¦LeftOffset=0¦BottomOffset=0¦Orientation=2¦PaperLength=1000¦PaperWidth=1000¦Scale=100¦PaperSource=15¦PrintQuality=600¦MediaType=1¦DitherType=10¦PaperKind=Letter¦PrintScaleMode=1

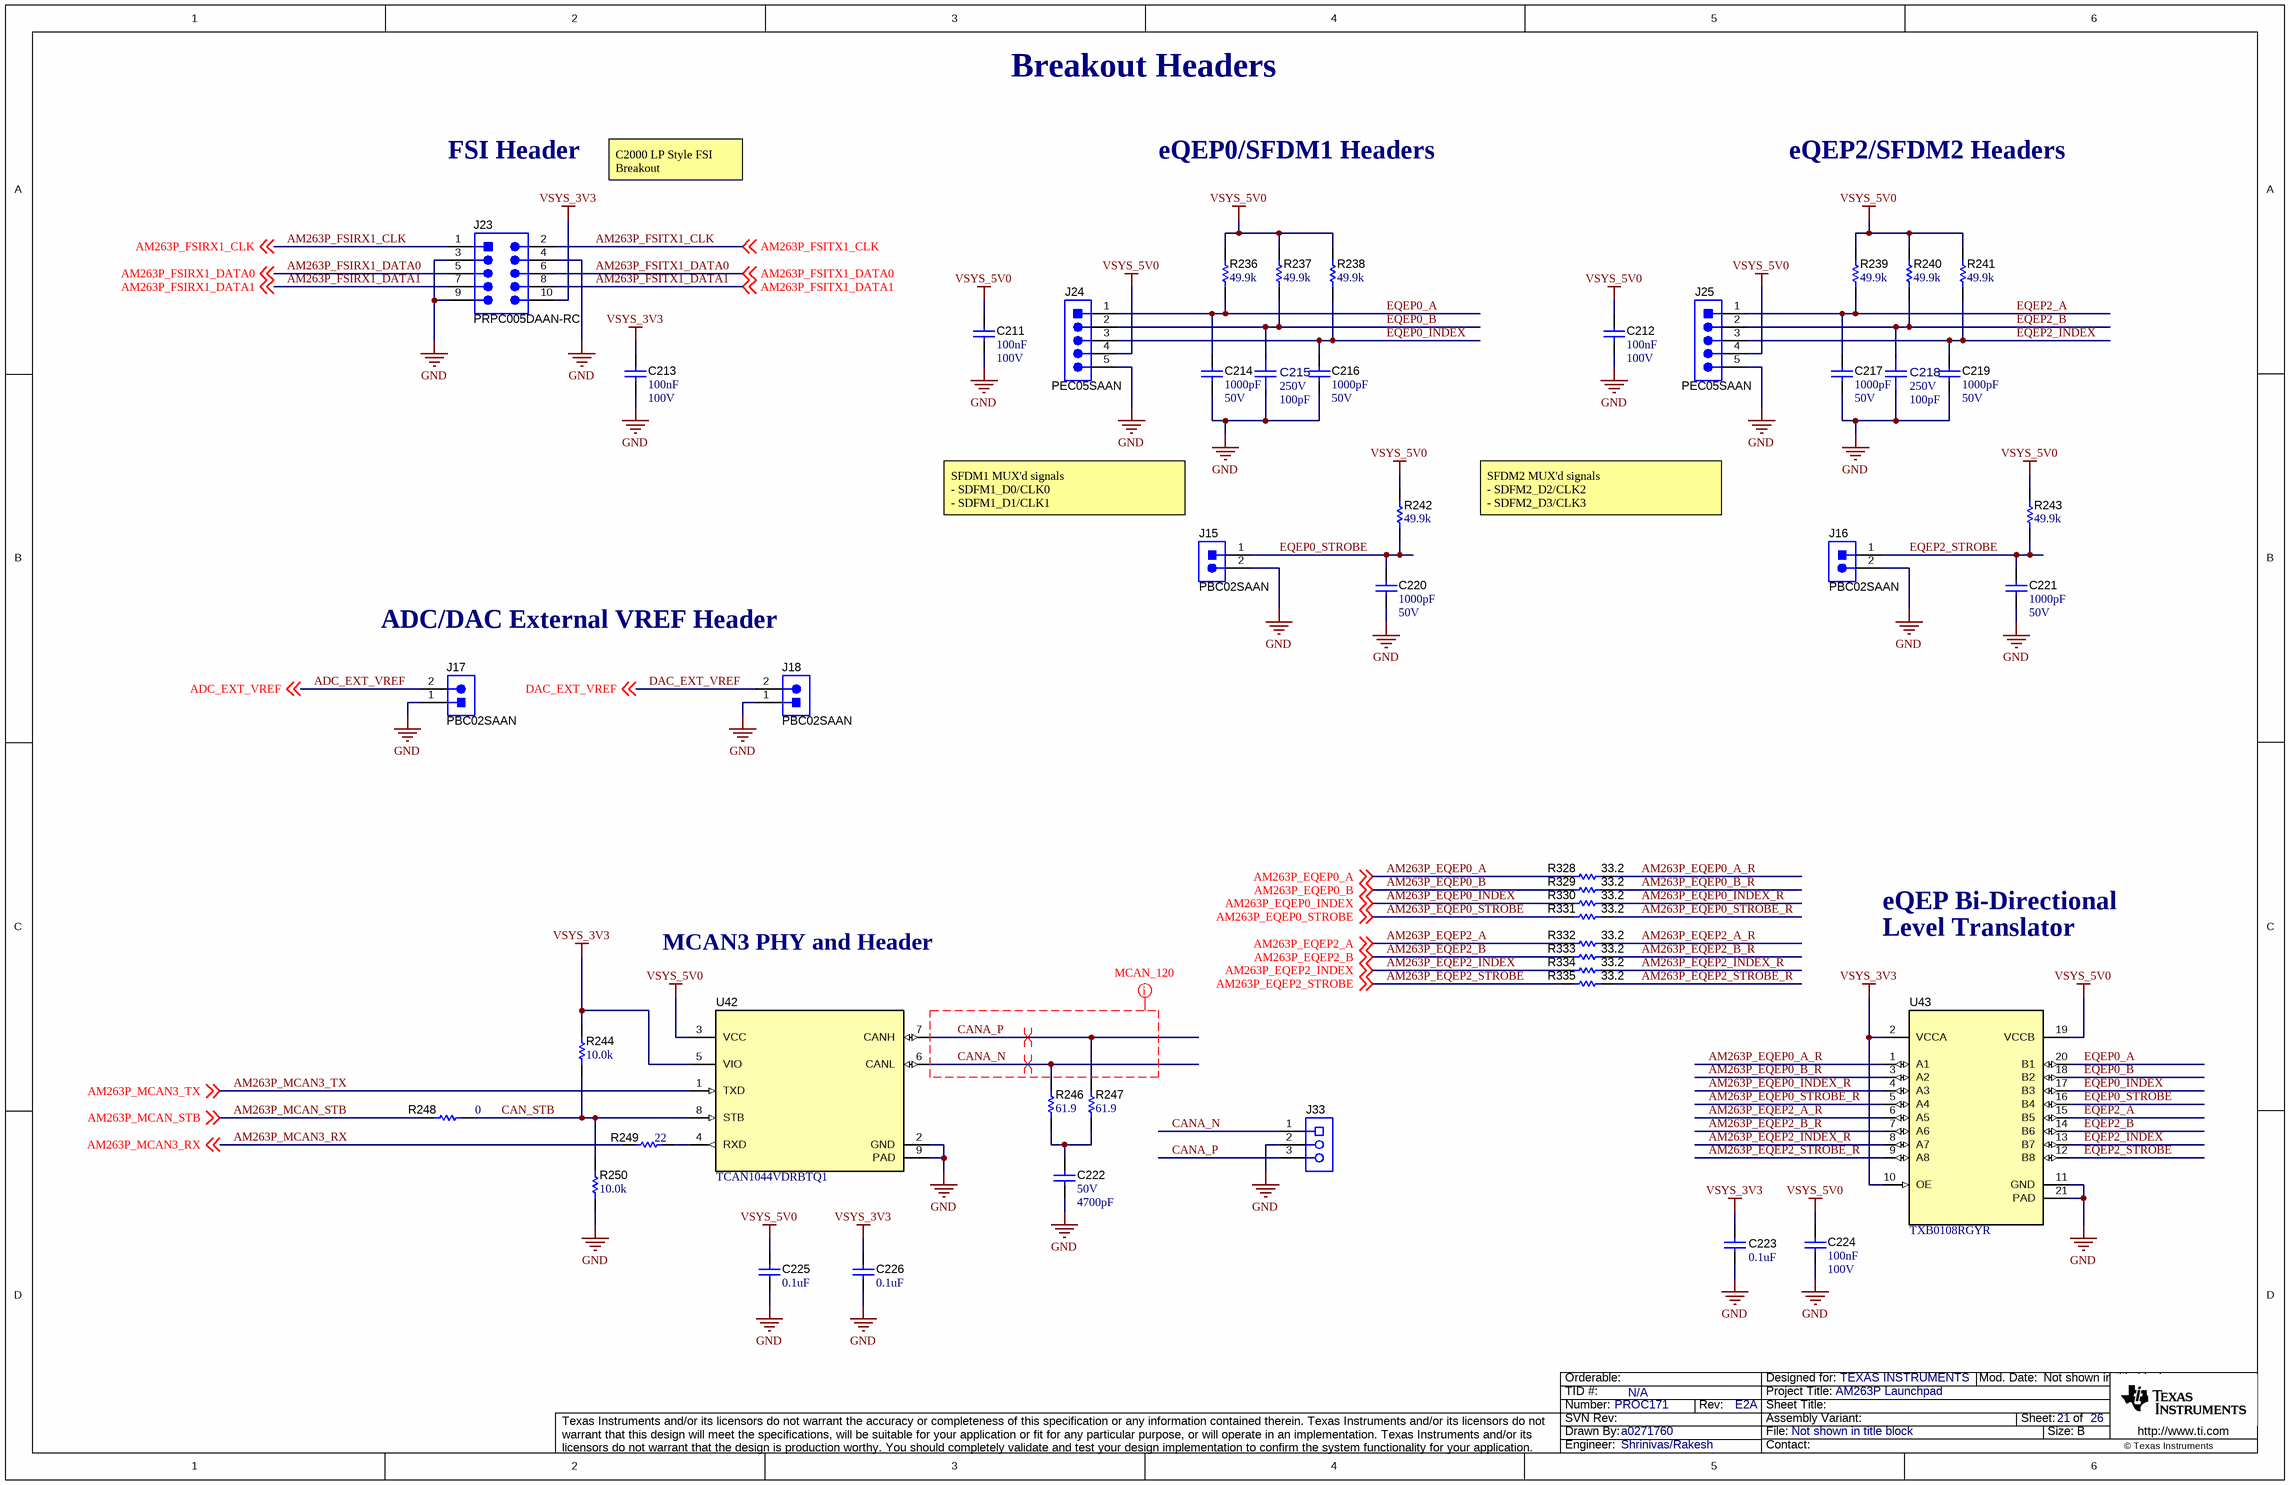
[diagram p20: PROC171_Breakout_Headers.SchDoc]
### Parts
C211  Cap_F: 100nF  VDC_V: 100V  [0603]  (hidden comment: GRM188R72A104KA35D)
C212  Cap_F: 100nF  VDC_V: 100V  [0603]  (hidden comment: GRM188R72A104KA35D)
C213  Cap_F: 100nF  VDC_V: 100V  [0603]  (hidden comment: GRM188R72A104KA35D)
C214  ValueDisplayed: 1000pF  VDC_V: 50V  [0603]  (hidden comment: GRM1885C1H102JA01D)
C215  VDC_V: 250V  ValueDisplayed: 100pF  [FP-GQM1875C2E101JB12D_0603-MFG]  (hidden comment: GQM1875C2E101JB12D)
C216  ValueDisplayed: 1000pF  VDC_V: 50V  [0603]  (hidden comment: GRM1885C1H102JA01D)
C217  ValueDisplayed: 1000pF  VDC_V: 50V  [0603]  (hidden comment: GRM1885C1H102JA01D)
C218  VDC_V: 250V  ValueDisplayed: 100pF  [FP-GQM1875C2E101JB12D_0603-MFG]  (hidden comment: GQM1875C2E101JB12D)
C219  ValueDisplayed: 1000pF  VDC_V: 50V  [0603]  (hidden comment: GRM1885C1H102JA01D)
C220  ValueDisplayed: 1000pF  VDC_V: 50V  [0603]  (hidden comment: GRM1885C1H102JA01D)
C221  ValueDisplayed: 1000pF  VDC_V: 50V  [0603]  (hidden comment: GRM1885C1H102JA01D)
C222  VDC_V: 50V  ValueDisplayed: 4700pF  [0402]  (hidden comment: GRM155R71H472KA01D)
C223  ValueDisplayed: 0.1uF  [0402]  (hidden comment: GRM155R71E104KE14D)
C224  Cap_F: 100nF  VDC_V: 100V  [0603]  (hidden comment: GRM188R72A104KA35D)
C225  ValueDisplayed: 0.1uF  [0402]  (hidden comment: GRM155R71E104KE14D)
C226  ValueDisplayed: 0.1uF  [0402]  (hidden comment: GRM155R71E104KE14D)
J15  PBC02SAAN  [Sullins_PBC02SAAN]
J16  PBC02SAAN  [Sullins_PBC02SAAN]
J17  PBC02SAAN  [Sullins_PBC02SAAN]
J18  PBC02SAAN  [Sullins_PBC02SAAN]
J23  PRPC005DAAN-RC  [Sullins_xxPC005DAAN-RC]
J24  PEC05SAAN  [Sullins_PxC05SAAN]
J25  PEC05SAAN  [Sullins_PxC05SAAN]
J33  OSTTE030161  [On-Shore_OSTTE030161]  (value not drawn)
R236  ValueDisplayed: 49.9k  [0402]  (hidden comment: ERJ-2RKF4992X)
R237  ValueDisplayed: 49.9k  [0402]  (hidden comment: ERJ-2RKF4992X)
R238  ValueDisplayed: 49.9k  [0402]  (hidden comment: ERJ-2RKF4992X)
R239  ValueDisplayed: 49.9k  [0402]  (hidden comment: ERJ-2RKF4992X)
R240  ValueDisplayed: 49.9k  [0402]  (hidden comment: ERJ-2RKF4992X)
R241  ValueDisplayed: 49.9k  [0402]  (hidden comment: ERJ-2RKF4992X)
R242  ValueDisplayed: 49.9k  [0402]  (hidden comment: ERJ-2RKF4992X)
R243  ValueDisplayed: 49.9k  [0402]  (hidden comment: ERJ-2RKF4992X)
R244  ValueDisplayed: 10.0k  [0402L]  (hidden comment: CRCW040210K0FKED)
R246  ValueDisplayed: 61.9  [0402L]  (hidden comment: CRCW040261R9FKED)
R247  ValueDisplayed: 61.9  [0402L]  (hidden comment: CRCW040261R9FKED)
R248  ValueDisplayed: 0  [0402L]  (hidden comment: ERJ-2GE0R00X)
R249  ValueDisplayed: 22  [0402]  (hidden comment: CRCW040222R0JNED)
R250  ValueDisplayed: 10.0k  [0402L]  (hidden comment: CRCW040210K0FKED)
R328  ValueDisplayed: 33.2  [0402]  (hidden comment: CRCW040233R2FKED)
R329  ValueDisplayed: 33.2  [0402]  (hidden comment: CRCW040233R2FKED)
R330  ValueDisplayed: 33.2  [0402]  (hidden comment: CRCW040233R2FKED)
R331  ValueDisplayed: 33.2  [0402]  (hidden comment: CRCW040233R2FKED)
R332  ValueDisplayed: 33.2  [0402]  (hidden comment: CRCW040233R2FKED)
R333  ValueDisplayed: 33.2  [0402]  (hidden comment: CRCW040233R2FKED)
R334  ValueDisplayed: 33.2  [0402]  (hidden comment: CRCW040233R2FKED)
R335  ValueDisplayed: 33.2  [0402]  (hidden comment: CRCW040233R2FKED)
U42  TCAN1044VDRBTQ1  [DRB0008J]
U43  TXB0108RGYR  [RGY0020A]

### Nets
GND: C211.2 C212.2 C213.2 C214.2 C215.1 C216.2 C217.2 C218.1 C219.2 C220.2 C221.2 C222.2 C223.1 C224.2 C225.1 C226.1 J15.2 J16.2 J17.1 J18.1 J23.3 J23.4 J23.9 J24.5 J25.5 J33.2 R250.1 U42.2(GND) U42.9(PAD) U43.11(GND) U43.21(PAD)
VSYS_3V3: C213.1 C223.2 C226.2 J23.10 R244.2 U42.5(VIO) U43.2(VCCA) U43.10(OE)
VSYS_5V0: C211.1 C212.1 C224.1 C225.2 J24.4 J25.4 R236.2 R237.2 R238.2 R239.2 R240.2 R241.2 R242.2 R243.2 U42.3(VCC) U43.19(VCCB)
ADC_EXT_VREF: J17.2 ; off-sheet ADC_EXT_VREF
AM263P_EQEP0_A: R328.1 ; off-sheet AM263P_EQEP0_A
AM263P_EQEP0_A_R: R328.2 U43.1(A1)
AM263P_EQEP0_B: R329.1 ; off-sheet AM263P_EQEP0_B
AM263P_EQEP0_B_R: R329.2 U43.3(A2)
AM263P_EQEP0_INDEX: R330.1 ; off-sheet AM263P_EQEP0_INDEX
AM263P_EQEP0_INDEX_R: R330.2 U43.4(A3)
AM263P_EQEP0_STROBE: R331.1 ; off-sheet AM263P_EQEP0_STROBE
AM263P_EQEP0_STROBE_R: R331.2 U43.5(A4)
AM263P_EQEP2_A: R332.1 ; off-sheet AM263P_EQEP2_A
AM263P_EQEP2_A_R: R332.2 U43.6(A5)
AM263P_EQEP2_B: R333.1 ; off-sheet AM263P_EQEP2_B
AM263P_EQEP2_B_R: R333.2 U43.7(A6)
AM263P_EQEP2_INDEX: R334.1 ; off-sheet AM263P_EQEP2_INDEX
AM263P_EQEP2_INDEX_R: R334.2 U43.8(A7)
AM263P_EQEP2_STROBE: R335.1 ; off-sheet AM263P_EQEP2_STROBE
AM263P_EQEP2_STROBE_R: R335.2 U43.9(A8)
AM263P_FSIRX1_CLK: J23.1 ; off-sheet AM263P_FSIRX1_CLK
AM263P_FSIRX1_DATA0: J23.5 ; off-sheet AM263P_FSIRX1_DATA0
AM263P_FSIRX1_DATA1: J23.7 ; off-sheet AM263P_FSIRX1_DATA1
AM263P_FSITX1_CLK: J23.2 ; off-sheet AM263P_FSITX1_CLK
AM263P_FSITX1_DATA0: J23.6 ; off-sheet AM263P_FSITX1_DATA0
AM263P_FSITX1_DATA1: J23.8 ; off-sheet AM263P_FSITX1_DATA1
AM263P_MCAN3_RX: R249.1 ; off-sheet AM263P_MCAN3_RX
AM263P_MCAN3_TX: U42.1(TXD) ; off-sheet AM263P_MCAN3_TX
AM263P_MCAN_STB: R248.2 ; off-sheet AM263P_MCAN_STB
CAN_STB: R244.1 R248.1 R250.2 U42.8(STB)
CANA_N: J33.1 R246.2 U42.6(CANL)
CANA_P: J33.3 R247.2 U42.7(CANH)
DAC_EXT_VREF: J18.2 ; off-sheet DAC_EXT_VREF
EQEP0_A: C214.1 J24.1 R236.1 U43.20(B1)
EQEP0_B: C215.2 J24.2 R237.1 U43.18(B2)
EQEP0_INDEX: C216.1 J24.3 R238.1 U43.17(B3)
EQEP0_STROBE: C220.1 J15.1 R242.1 U43.16(B4)
EQEP2_A: C217.1 J25.1 R239.1 U43.15(B5)
EQEP2_B: C218.2 J25.2 R240.1 U43.14(B6)
EQEP2_INDEX: C219.1 J25.3 R241.1 U43.13(B7)
EQEP2_STROBE: C221.1 J16.1 R243.1 U43.12(B8)
NetC222_1: C222.1 R246.1 R247.1
NetR249_2: R249.2 U42.4(RXD)

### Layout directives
differential pair: CANA_N, CANA_P
mark named MCAN_120: CANA_N, CANA_P

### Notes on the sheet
- Breakout Headers
- FSI Header
- eQEP0/SFDM1 Headers
- eQEP2/SFDM2 Headers
- C2000 LP Style FSI Breakout
- SFDM1 MUX'd signals
  - SDFM1_D0/CLK0
  - SDFM1_D1/CLK1
- SFDM2 MUX'd signals
  - SDFM2_D2/CLK2
  - SDFM2_D3/CLK3
- ADC/DAC External VREF Header
- MCAN3 PHY and Header
- eQEP Bi-Directional
- Level Translator

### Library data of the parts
C211-C213 C224 = CMP-0007469-4: CAP, CERM, 0.1 uF, 100 V, +/- 10%, X7R, 0603; Manufacturer: MuRata; TaMin_C: -55°C; Polarized: N; SizeAreaWB_mm2: 4.68; Value1: Unknown; U/M: EA; Value: 0.1uF; TaMax_C: 125°C; SizeZ_mm: 1; SizeX_mm: 1.6; SizeY_mm: 0.8; SizeArea_mm2: 1.28; AEC Category: Q200
C214 C216 C217 C219-C221 = CMP-0007173-4: CAP, CERM, 1000 pF, 50 V, +/- 5%, C0G/NP0, 0603; Manufacturer: MuRata; Value: 1000pF; U/M: EA; SizeAreaWB_mm2: 4.68; SizeX_mm: 1.6; SizeZ_mm: 1; SizeArea_mm2: 1.28; TaMax_C: 125°C; SizeY_mm: 0.8; Cap_F: 1nF; TaMin_C: -55°C; Value1: Unknown; AEC Category: Q200; Polarized: N
C215 C218 = CMP-0035320-1: Ceramic Capacitor 100pF ±5% 250VDC C0G 0603 Paper T/R; Manufacturer: Murata; TempCo: 30ppm/°C; Tolerance_%: 0.05%; SizeZ_mm: 0.8mm; AEC Qualified: No
C222 = CMP-0006692-2: CAP, CERM, 4700 pF, 50 V, +/- 10%, X7R, 0402; Manufacturer: MuRata; TaMin_C: -55°C; Polarized: N; SizeAreaWB_mm2: 3; Value1: Unknown; U/M: EA; Value: 4700pF; TaMax_C: 125°C; SizeZ_mm: 0.6; SizeX_mm: 1; SizeY_mm: 0.5; Cap_F: 4.7nF; AEC Category: Q200
C223 C225 C226 = CMP-0006659-2: CAP, CERM, 0.1 uF, 25 V, +/- 10%, X7R, 0402; Manufacturer: MuRata; TaMin_C: -55°C; Polarized: N; SizeAreaWB_mm2: 3; U/M: EA; Value: 0.1uF; TaMax_C: 125°C; SizeZ_mm: 0.6; SizeX_mm: 1; SizeY_mm: 0.5; Value2: 25V; Cap_F: 100nF; AEC Category: Q200; Value1: Unknown
J15-J18 = CMP-0054566-1: Header, 100mil, 2x1, Gold, TH; Manufacturer: Sullins Connector Solutions; CNHeader: TRUE; Current_A: 3A; Green_Lifecycle: Active; Shrouded: N; Gender: Male; Green_REACh: Passed; Voltage_V: 1.8kV; Row_Count: 1; Pitch_mm: 2.54; CT: FALSE; Cert_UL: Y
J23 = CMP-0080722-2: Header, 2.54mm, 5x2, Gold, TH; Manufacturer: Sullins Connector Solutions; Pitch_mm: 2.54; Gender: Male; Cert_UL: Y; Current_A: 3A; Voltage_V: 1kV; Shrouded: N; Row_Count: 2
J24 J25 = CMP-0054597-1: Header, 2.54mm, 5x1, Tin, TH; Manufacturer: Sullins Connector Solutions; CNHeader: TRUE; Current_A: 3A; Green_Lifecycle: Not Set; Shrouded: N; Gender: Male; Green_REACh: Incomplete; Voltage_V: 1.8kV; Row_Count: 1; Pitch_mm: 2.54; CT: FALSE; Cert_UL: Y
J33 = CMP-0075352-1: Terminal Block, 3.5mm, 3x1, Tin, R/A, TH; Manufacturer: On-Shore Technology; CNHeader: False; Current_A: 10A; Green_Lifecycle: Not Set; Gender: Female; Cert_CSA: Y; Green_REACh: Incomplete; Voltage_V: 125V; Row_Count: 1; Pitch_mm: 3.5; CT: True
R236-R243 = CMP-0026702-1: RES, 49.9 k, 1%, 0.1 W, AEC-Q200 Grade 0, 0402; Manufacturer: Panasonic; Power_W: 100mW; TempCo: 100 ppm/C; Value_Code: 49k9; U/M: EA; Value: 49.9k; EIA_Code: E96; SizeX_mm: 1; SizeY_mm: 0.5; SizeZ_mm: 0.6; Value2: 0.1W; AEC Qualified: Y; VDC_V: 50V; AEC Grade: 0; AEC Category: Q200
R244 R250 = CMP-0025958-3: RES, 10.0 k, 1%, 0.063 W, AEC-Q200 Grade 0, 0402; Manufacturer: Vishay-Dale; Power_W: 63mW; TempCo: 100 ppm/C; Value_Code: 10k0; Value: 10.0k; EIA_Code: E96; Res_ohm: 10k; SizeX_mm: 1; SizeY_mm: 0.5; SizeZ_mm: 0.6; Value2: 0.063W; AEC Qualified: Y; VDC_V: 50V; AEC Category: Q200; AEC Grade: 0
R246 R247 = CMP-0026491-2: RES, 61.9, 1%, 0.063 W, AEC-Q200 Grade 0, 0402; Manufacturer: Vishay-Dale; Power_W: 63mW; TempCo: 100 ppm/C; Value_Code: 61R9; Value: 61.9; EIA_Code: E96; SizeX_mm: 1; SizeY_mm: 0.5; SizeZ_mm: 0.6; Value2: 0.063W; AEC Qualified: Y; VDC_V: 50V; AEC Category: Q200; AEC Grade: 0
R248 = CMP-0026992-3: RES, 0, 5%, 0.1 W, AEC-Q200 Grade 0, 0402; Manufacturer: Panasonic; Power_W: 100mW; TempCo: 600 ppm/C; Value_Code: 0000; Value: 0; EIA_Code: E24; SizeX_mm: 1; SizeY_mm: 0.5; SizeZ_mm: 0.6; Value2: 0.1W; AEC Qualified: Y; VDC_V: 50V; AEC Category: Q200; SizeAreaWB_mm2: 3
R249 = CMP-0026880-3: RES, 22, 5%, 0.063 W, AEC-Q200 Grade 0, 0402; Manufacturer: Vishay-Dale; Power_W: 63mW; TempCo: 200 ppm/C; Value_Code: 22R0; Value: 22; EIA_Code: E24; SizeX_mm: 1; SizeY_mm: 0.5; SizeZ_mm: 0.6; Value2: 0.063W; AEC Qualified: Y; VDC_V: 50V; AEC Category: Q200; AEC Grade: 0
R328-R335 = CMP-0026299-2: RES, 33.2, 1%, 0.063 W, AEC-Q200 Grade 0, 0402; Manufacturer: Vishay-Dale; Power_W: 63mW; TempCo: 100 ppm/C; Value_Code: 33R2; Value: 33.2; EIA_Code: E96; SizeX_mm: 1; SizeY_mm: 0.5; SizeZ_mm: 0.6; Value2: 0.063W; AEC Qualified: Y; VDC_V: 50V; AEC Category: Q200; AEC Grade: 0
U42 = CMP-0079884-2: Automotive High Speed CAN Transceiver, DRB0008J (VSON-8); Alternate Manufacturer: Texas Instruments; Alternate PartNumber: TCAN1044VDRBRQ1; SizeX_mm: 3; AEC Category: Q200; SizeAreaWB_mm2: 16; SizeZ_mm: 1; SizeArea_mm2: 9; AEC Qualified: Y; CompType: IC
U43 = CMP-0074359-2: 8-Bit Bidirectional Voltage-Level Shifter with Auto Direction Sensing and +/-15-kV ESD Protect, RGY0020A (VQFN-20); Manufacturer: Texas Instruments; SizeZ_mm: 1.0; SizeX_mm: 3.5; SizeY_mm: 4.5; SizeArea_mm2: 15.75; CompType: IC; U/M: EA; SizeAreaWB_mm2: 24.75

## Sheet PROC171_IO_EXPANDER.SchDoc
size 431 x 279 mm; DocumentNumber: 25; SheetNumber: 25; SheetTotal: 26

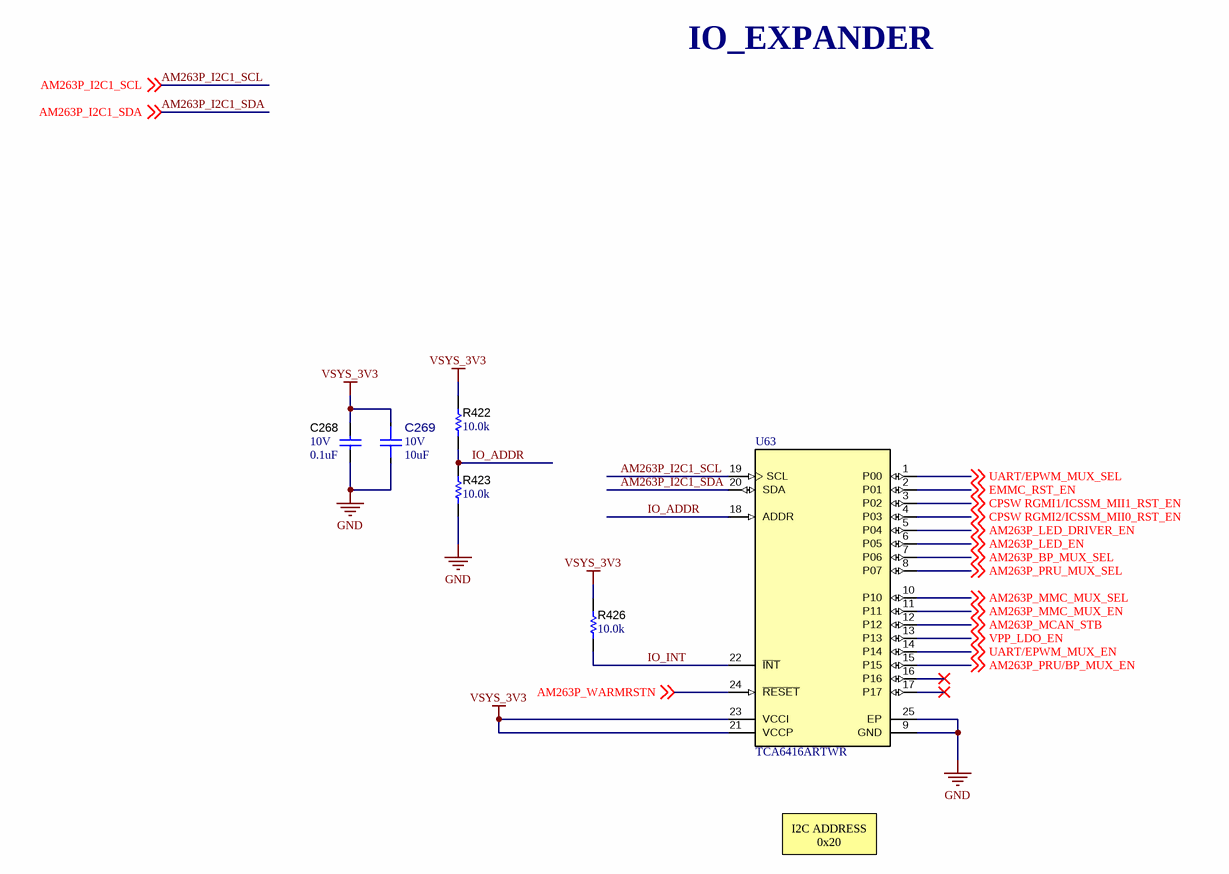
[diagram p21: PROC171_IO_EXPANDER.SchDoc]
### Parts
C268  VDC_V: 10V  ValueDisplayed: 0.1uF  [0402]  (hidden comment: 885012105010)
C269  ValueDisplayed: 10uF  VDC_V: 10V  [FP-KGM05CR51A106MH_0402-MFG]  (hidden comment: KGM05CR51A106MH)
R422  ValueDisplayed: 10.0k  [0402]  (hidden comment: ERJ-2RKF1002X)
R423  ValueDisplayed: 10.0k  [0402]  (hidden comment: ERJ-2RKF1002X)
R426  ValueDisplayed: 10.0k  [0402]  (hidden comment: ERJ-2RKF1002X)
U63  TCA6416ARTWR  [RTW0024B]

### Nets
GND: C268.2 C269.2 R423.1 U63.9(GND) U63.25(EP)
VSYS_3V3: C268.1 C269.1 R422.2 R426.2 U63.21(VCCP) U63.23(VCCI)
AM263P_BP_MUX_SEL: U63.7(P06) ; off-sheet AM263P_BP_MUX_SEL
AM263P_I2C1_SCL: U63.19(SCL) ; off-sheet AM263P_I2C1_SCL
AM263P_I2C1_SDA: U63.20(SDA) ; off-sheet AM263P_I2C1_SDA
AM263P_LED_DRIVER_EN: U63.5(P04) ; off-sheet AM263P_LED_DRIVER_EN
AM263P_LED_EN: U63.6(P05) ; off-sheet AM263P_LED_EN
AM263P_MCAN_STB: U63.12(P12) ; off-sheet AM263P_MCAN_STB
AM263P_MMC_MUX_EN: U63.11(P11) ; off-sheet AM263P_MMC_MUX_EN
AM263P_MMC_MUX_SEL: U63.10(P10) ; off-sheet AM263P_MMC_MUX_SEL
AM263P_PRU/BP_MUX_EN: U63.15(P15) ; off-sheet AM263P_PRU/BP_MUX_EN
AM263P_PRU_MUX_SEL: U63.8(P07) ; off-sheet AM263P_PRU_MUX_SEL
AM263P_WARMRSTN: U63.24(~{RESET}) ; off-sheet AM263P_WARMRSTN
CPSW RGMI1/ICSSM_MII1_RST_EN: U63.3(P02) ; off-sheet CPSW RGMI1/ICSSM_MII1_RST_EN
CPSW RGMI2/ICSSM_MII0_RST_EN: U63.4(P03) ; off-sheet CPSW RGMI2/ICSSM_MII0_RST_EN
EMMC_RST_EN: U63.2(P01) ; off-sheet EMMC_RST_EN
IO_ADDR: R422.1 R423.2 U63.18(ADDR)
IO_INT: R426.1 U63.22(~{INT})
UART/EPWM_MUX_EN: U63.14(P14) ; off-sheet UART/EPWM_MUX_EN
UART/EPWM_MUX_SEL: U63.1(P00) ; off-sheet UART/EPWM_MUX_SEL
VPP_LDO_EN: U63.13(P13) ; off-sheet VPP_LDO_EN

Not connected (* = marked no-connect by the designer): U63 16(P16)* 17(P17)*

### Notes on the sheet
- IO_EXPANDER
- I2C ADDRESS 0x20

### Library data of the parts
C268 = CMP-0006221-2: CAP, CERM, 0.1 uF, 10 V, +/- 20%, X5R, 0402; Manufacturer: Wurth Elektronik; TaMin_C: -55°C; Polarized: N; SizeAreaWB_mm2: 3; Value1: Unknown; U/M: EA; Value: 0.1uF; TaMax_C: 85°C; SizeZ_mm: 0.6; SizeX_mm: 1; SizeY_mm: 0.5; Cap_F: 100nF; AEC Category: Q200
C269 = CMP-0043010-1: 10 µF ±20% 10V Ceramic Capacitor X5R 0402 (1005 Metric); Manufacturer: KYOCERA AVX; AEC Qualified: No; Cap_F: 10µF; SizeZ_mm: 0.7mm; TempCo: 15%; Value: 10µF
R422 R423 R426 = CMP-0026658-1: RES, 10.0 k, 1%, 0.1 W, 0402; Manufacturer: Panasonic; Power_W: 100mW; TempCo: 100 ppm/C; Value_Code: 10k0; U/M: EA; Value: 10.0k; EIA_Code: E96; Res_ohm: 10k; SizeX_mm: 1; SizeY_mm: 0.5; SizeZ_mm: 0.6; Value2: 0.1W; VDC_V: 50V; AEC Category: Q200
U63 = CMP-0043175-2: Low-Voltage 16-Bit I2C and SMBus I/O Expander, 16 Outputs, 1.65 to 5.5 V, -40 to 85 degC, 24-pin QFN (RTW), Green (RoHS & no Sb/Br); Manufacturer: Texas Instruments; SubFamily: I2C IO Expander; VCC(Max)(V): 5.5; VCC(Min)(V): 1.65; No. of Outputs: 16; fSCLK(Max)(MHz): 400; 5V Tolerant I/O: Yes; I2C Address: 0100 00x

## Sheet PROC171_LED.SchDoc
size 431 x 279 mm; Date: Not shown in title block; ApprovedBy: Not shown in title block; CheckedBy: Not shown in title block; Author: Not shown in title block; CompanyName: Not shown in title block; Engineer: Not shown in title block; Organization: Not shown in title block; Address1: Not shown in title block; Address2: Not shown in title block; Address3: Not shown in title block; Address4: Not shown in title block; DocumentNumber: 24; Revision: Use project parameter SCH_Rev; SheetNumber: 24; SheetTotal: 26; PageSetup: Record=PageOptions¦CenterHorizontal=True¦CenterVertical=True¦PrintScale=1.00¦XCorrection=1.00¦YCorrection=1.00¦PrintKind=0¦BorderSize=5000000¦LeftOffset=0¦BottomOffset=0¦Orientation=2¦PaperLength=1000¦PaperWidth=1000¦Scale=100¦PaperSource=15¦PrintQuality=600¦MediaType=1¦DitherType=10¦PaperKind=Letter¦PrintScaleMode=1

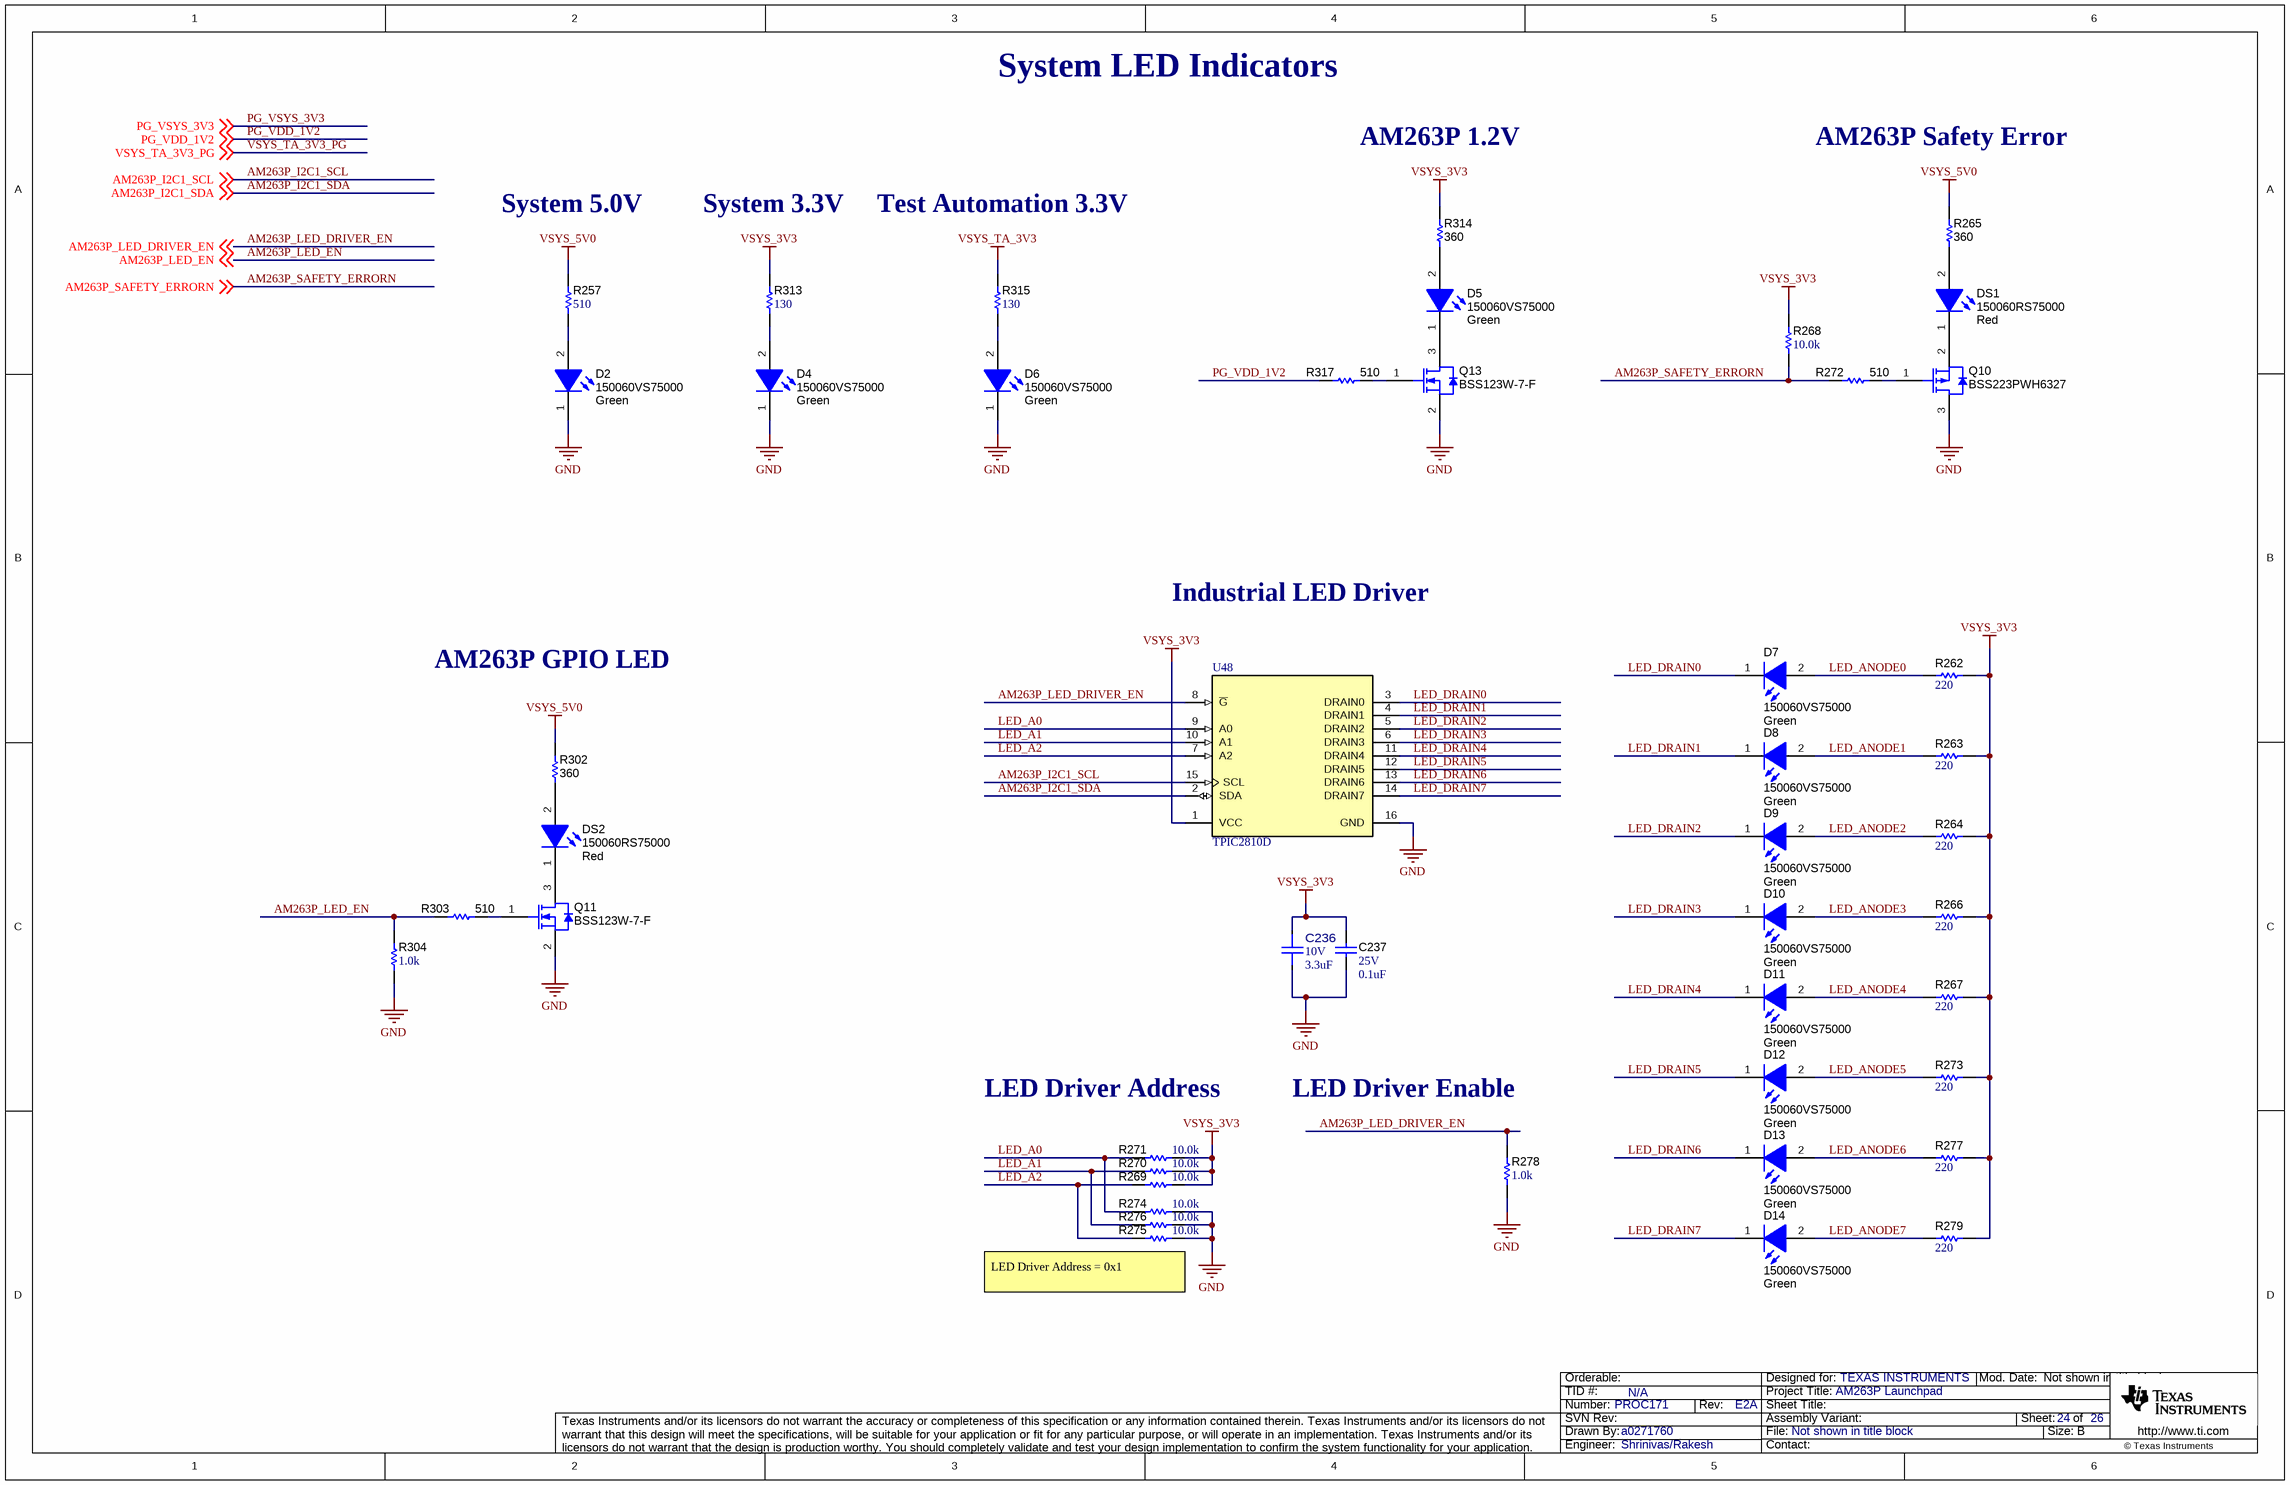
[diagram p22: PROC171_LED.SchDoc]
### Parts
C236  VDC_V: 10V  ValueDisplayed: 3.3uF  [FP-CL10A335KP8NNNC_0603-MFG]  (hidden comment: CL10A335KP8NNNC)
C237  VDC_V: 25V  ValueDisplayed: 0.1uF  [0402]  (hidden comment: GRM155R71E104KE14D)
D2  150060VS75000  value Green  [WL-SMCW_GREEN]
D4  150060VS75000  value Green  [WL-SMCW_GREEN]
D5  150060VS75000  value Green  [WL-SMCW_GREEN]
D6  150060VS75000  value Green  [WL-SMCW_GREEN]
D7  150060VS75000  value Green  [WL-SMCW_GREEN]
D8  150060VS75000  value Green  [WL-SMCW_GREEN]
D9  150060VS75000  value Green  [WL-SMCW_GREEN]
D10  150060VS75000  value Green  [WL-SMCW_GREEN]
D11  150060VS75000  value Green  [WL-SMCW_GREEN]
D12  150060VS75000  value Green  [WL-SMCW_GREEN]
D13  150060VS75000  value Green  [WL-SMCW_GREEN]
D14  150060VS75000  value Green  [WL-SMCW_GREEN]
DS1  150060RS75000  value Red  [WL-SMCW_RED]
DS2  150060RS75000  value Red  [WL-SMCW_RED]
Q10  BSS223PWH6327  [SOT-323]
Q11  BSS123W-7-F  [SOT-323]
Q13  BSS123W-7-F  [SOT-323]
R257  ValueDisplayed: 510  [0402]  (hidden comment: ERJ-2RKF5100X)
R262  ValueDisplayed: 220  [0402]  (hidden comment: ERJ-2RKF2200X)
R263  ValueDisplayed: 220  [0402]  (hidden comment: ERJ-2RKF2200X)
R264  ValueDisplayed: 220  [0402]  (hidden comment: ERJ-2RKF2200X)
R265  ValueDisplayed: 360  [0402L]  (hidden comment: ERJ-2GEJ361X)
R266  ValueDisplayed: 220  [0402]  (hidden comment: ERJ-2RKF2200X)
R267  ValueDisplayed: 220  [0402]  (hidden comment: ERJ-2RKF2200X)
R268  ValueDisplayed: 10.0k  [0402]  (hidden comment: ERJ-2RKF1002X)
R269  ValueDisplayed: 10.0k  [0402]  (hidden comment: ERJ-2RKF1002X)
R270  ValueDisplayed: 10.0k  [0402]  (hidden comment: ERJ-2RKF1002X)
R271  ValueDisplayed: 10.0k  [0402]  (hidden comment: ERJ-2RKF1002X)
R272  ValueDisplayed: 510  [0402L]  (hidden comment: ERJ-2GEJ511X)
R273  ValueDisplayed: 220  [0402]  (hidden comment: ERJ-2RKF2200X)
R274  ValueDisplayed: 10.0k  [0402]  (hidden comment: ERJ-2RKF1002X)
R275  ValueDisplayed: 10.0k  [0402]  (hidden comment: ERJ-2RKF1002X)
R276  ValueDisplayed: 10.0k  [0402]  (hidden comment: ERJ-2RKF1002X)
R277  ValueDisplayed: 220  [0402]  (hidden comment: ERJ-2RKF2200X)
R278  ValueDisplayed: 1.0k  [0402]  (hidden comment: ERJ-2GEJ102X)
R279  ValueDisplayed: 220  [0402]  (hidden comment: ERJ-2RKF2200X)
R302  ValueDisplayed: 360  [0402L]  (hidden comment: ERJ-2GEJ361X)
R303  ValueDisplayed: 510  [0402L]  (hidden comment: ERJ-2GEJ511X)
R304  ValueDisplayed: 1.0k  [0402]  (hidden comment: ERJ-2GEJ102X)
R313  ValueDisplayed: 130  [0402]  (hidden comment: CRCW0402130RFKED)
R314  ValueDisplayed: 360  [0402L]  (hidden comment: ERJ-2GEJ361X)
R315  ValueDisplayed: 130  [0402]  (hidden comment: CRCW0402130RFKED)
R317  ValueDisplayed: 510  [0402L]  (hidden comment: ERJ-2GEJ511X)
U48  TPIC2810D  [D0016A_N]

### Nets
GND: C236.2 C237.2 D2.1(K) D4.1(K) D6.1(K) Q10.3(D) Q11.2(S) Q13.2(S) R274.1 R275.1 R276.1 R278.1 R304.1 U48.16(GND)
VSYS_3V3: C236.1 C237.1 R262.2 R263.2 R264.2 R266.2 R267.2 R268.2 R269.1 R270.1 R271.1 R273.2 R277.2 R279.2 R313.2 R314.2 U48.1(VCC)
VSYS_5V0: R257.2 R265.2 R302.2
VSYS_TA_3V3: R315.2
AM263P_I2C1_SCL: U48.15(SCL) ; off-sheet AM263P_I2C1_SCL
AM263P_I2C1_SDA: U48.2(SDA) ; off-sheet AM263P_I2C1_SDA
AM263P_LED_DRIVER_EN: R278.2 U48.8(~{G}) ; off-sheet AM263P_LED_DRIVER_EN
AM263P_LED_EN: R303.1 R304.2 ; off-sheet AM263P_LED_EN
AM263P_SAFETY_ERRORN: R268.1 R272.1 ; off-sheet AM263P_SAFETY_ERRORN
LED_A0: R271.2 R274.2 U48.9(A0)
LED_A1: R270.2 R276.2 U48.10(A1)
LED_A2: R269.2 R275.2 U48.7(A2)
LED_ANODE0: D7.2(A) R262.1
LED_ANODE1: D8.2(A) R263.1
LED_ANODE2: D9.2(A) R264.1
LED_ANODE3: D10.2(A) R266.1
LED_ANODE4: D11.2(A) R267.1
LED_ANODE5: D12.2(A) R273.1
LED_ANODE6: D13.2(A) R277.1
LED_ANODE7: D14.2(A) R279.1
LED_DRAIN0: D7.1(K) U48.3(DRAIN0)
LED_DRAIN1: D8.1(K) U48.4(DRAIN1)
LED_DRAIN2: D9.1(K) U48.5(DRAIN2)
LED_DRAIN3: D10.1(K) U48.6(DRAIN3)
LED_DRAIN4: D11.1(K) U48.11(DRAIN4)
LED_DRAIN5: D12.1(K) U48.12(DRAIN5)
LED_DRAIN6: D13.1(K) U48.13(DRAIN6)
LED_DRAIN7: D14.1(K) U48.14(DRAIN7)
PG_VDD_1V2: R317.1 ; off-sheet PG_VDD_1V2
NetD2_2: D2.2(A) R257.1
NetD4_2: D4.2(A) R313.1
NetD5_1: D5.1(K) Q13.3(D)
NetD5_2: D5.2(A) R314.1
NetD6_2: D6.2(A) R315.1
NetDS1_1: DS1.1(K) Q10.2(S)
NetDS1_2: DS1.2(A) R265.1
NetDS2_1: DS2.1(K) Q11.3(D)
NetDS2_2: DS2.2(A) R302.1
NetQ10_1: Q10.1(G) R272.2
NetQ11_1: Q11.1(G) R303.2
NetQ13_1: Q13.1(G) R317.2

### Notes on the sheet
- System LED Indicators
- AM263P 1.2V
- AM263P Safety Error
- System 5.0V
- System 3.3V
- Test Automation 3.3V
- Industrial LED Driver
- AM263P GPIO LED
- LED Driver Address
- LED Driver Enable
- (near R275) LED Driver Address = 0x1

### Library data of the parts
C236 = CMP-0042976-1: Cap Ceramic 3.3uF 10V X5R ±10% Pad SMD 0603 +85°C T/R; Manufacturer: Samsung; TempCo: 15%; Value: 3.3µF; SizeZ_mm: 0.9mm; AEC Qualified: No
C237 = CMP-0006659-2: CAP, CERM, 0.1 uF, 25 V, +/- 10%, X7R, 0402; Manufacturer: MuRata; TaMin_C: -55°C; Polarized: N; SizeAreaWB_mm2: 3; Value1: Unknown; U/M: EA; Value: 0.1uF; TaMax_C: 125°C; SizeZ_mm: 0.6; SizeX_mm: 1; SizeY_mm: 0.5; Cap_F: 100nF; AEC Category: Q200
D2 D4-D14 = CMP-0002894-2: LED, Green, SMD; Manufacturer: Wurth Elektronik; Io_A: 20mA; Value1: W; Vf_V: 2V; Type: AlInGaP
DS1 DS2 = CMP-0002947-3: LED, Red, SMD; Manufacturer: Wurth Elektronik; Value1: 0.072W; Vf_V: 2V; Angle: 140; Tjmax_C: 85°C; Type: AlInGaP; Vr_V: 5V; Io_A: 30mA; Power_TotalModule: 72mW
Q10 = CMP-0000010-3: MOSFET, P-CH, -20 V, -0.39 A, SOT-323; Alternate Manufacturer: None; Manufacturer: Infineon Technologies; Value: -20V; Rdson45_ohm: 1.2; SizeX_mm: 2.2; AEC Category: Q101; ChMode: Enhancement; Vgs_V: -12V; Value1: 1; IdsMax_A: -390mA; ChType: P; SizeAreaWB_mm2: 10.24; QgTyp_nC: -0.5; SizeArea_mm2: 4.84; SizeZ_mm: 1.1
Q11 Q13 = CMP-0000948-2: MOSFET, N-CH, 100 V, 0.17 A, SOT-323; Alternate Manufacturer: None; Manufacturer: Diodes Inc.; SizeZ_mm: 1.1; ChType: N; Value1: 1; VdsMax_V: 100V; SizeX_mm: 2.2; Vgs_V: 20V; Value: 100V; Rdson45_ohm: 10; SizeArea_mm2: 4.84; AEC Category: Q101; IdsMax_A: 170mA; SizeAreaWB_mm2: 10.24; U/M: EA
R257 = CMP-0026704-1: RES, 510, 1%, 0.1 W, 0402; Manufacturer: Panasonic; Power_W: 100mW; TempCo: 100 ppm/C; Value_Code: 510R; U/M: EA; Value: 510; SizeX_mm: 1; SizeY_mm: 0.5; SizeZ_mm: 0.6; Value2: 0.1W; VDC_V: 50V; AEC Category: Q200
R262-R264 R266 R267 R273 R277 R279 = CMP-0026680-1: RES, 220, 1%, 0.1 W, AEC-Q200 Grade 0, 0402; Manufacturer: Panasonic; Power_W: 100mW; TempCo: 100 ppm/C; Value_Code: 220R; U/M: EA; Value: 220; SizeX_mm: 1; SizeY_mm: 0.5; SizeZ_mm: 0.6; Value2: 0.1W; AEC Qualified: Y; VDC_V: 50V; AEC Grade: 0; AEC Category: Q200
R265 R302 R314 = CMP-0078194-1: RES, 360, 5%, 0.1 W, AEC-Q200 Grade 0, 0402; Manufacturer: Panasonic; Value_Code: 360R; SizeArea_mm2: 0.5; AEC Qualified: Y; AEC Category: Q200; Value: 360; SizeZ_mm: 0.6; EIA_Code: E24; TempCo: 200 ppm/C; AEC Grade: 0; Power_W: 100mW; VDC_V: 50V; Value2: 0.1W; U/M: EA; SizeX_mm: 1
R268-R271 R274-R276 = CMP-0026658-1: as R422 on sheet PROC171_IO_EXPANDER
R272 R303 R317 = CMP-0078212-1: RES, 510, 5%, 0.1 W, AEC-Q200 Grade 0, 0402; Manufacturer: Panasonic; Value_Code: 510R; SizeArea_mm2: 0.5; AEC Qualified: Y; AEC Category: Q200; Value: 510; SizeZ_mm: 0.6; EIA_Code: E24; TempCo: 200 ppm/C; AEC Grade: 0; Power_W: 100mW; VDC_V: 50V; Value2: 0.1W; U/M: EA; SizeX_mm: 1
R278 R304 = CMP-0078193-1: RES, 1.0 k, 5%, 0.1 W, AEC-Q200 Grade 0, 0402; Manufacturer: Panasonic; Value_Code: 1k00; SizeArea_mm2: 0.5; AEC Qualified: Y; AEC Category: Q200; Res_ohm: 1k; Value: 1.0k; SizeZ_mm: 0.6; Green_REACh: Passed; EIA_Code: E24; TempCo: 200 ppm/C; AEC Grade: 0; Power_W: 100mW; VDC_V: 50V; Value2: 0.1W; Green_Lifecycle: Active; U/M: EA; SizeX_mm: 1
R313 R315 = CMP-0025998-3: RES, 130, 1%, 0.063 W, AEC-Q200 Grade 0, 0402; Manufacturer: Vishay-Dale; Power_W: 63mW; TempCo: 100 ppm/C; Value_Code: 130R; Value: 130; EIA_Code: E96; SizeX_mm: 1; SizeY_mm: 0.5; SizeZ_mm: 0.6; Value2: 0.063W; AEC Qualified: Y; VDC_V: 50V; AEC Category: Q200; AEC Grade: 0
U48 = CMP-0044782-1: 8-Bit LED Driver with I2C Interface, D0016A, TUBE; Manufacturer: Texas Instruments; IO(PEAK)(A): 0.21; Priority (type 2): 1; rDS(on)(Ohms): 5; VDS(Max)(V): 40; IO(CONT)(A): 0.1; ICC(uA): 620; tPLH(ns): 1150; Rating: Catalog

## Sheet PROC171_XDS110_1.SchDoc: XDS110 JTAG/USB-to-UART Bridge
size 431 x 279 mm; Date: Not shown in title block; ApprovedBy: Not shown in title block; CheckedBy: Not shown in title block; Author: Not shown in title block; CompanyName: Not shown in title block; Engineer: Not shown in title block; Organization: Not shown in title block; Address1: Not shown in title block; Address2: Not shown in title block; Address3: Not shown in title block; Address4: Not shown in title block; DocumentNumber: 22; Revision: Use project parameter SCH_Rev; SheetNumber: 22; SheetTotal: 26; PageSetup: Record=PageOptions¦CenterHorizontal=True¦CenterVertical=True¦PrintScale=1.00¦XCorrection=1.00¦YCorrection=1.00¦PrintKind=0¦BorderSize=5000000¦LeftOffset=0¦BottomOffset=0¦Orientation=2¦PaperLength=1000¦PaperWidth=1000¦Scale=100¦PaperSource=15¦PrintQuality=600¦MediaType=1¦DitherType=10¦PaperKind=Letter¦PrintScaleMode=1

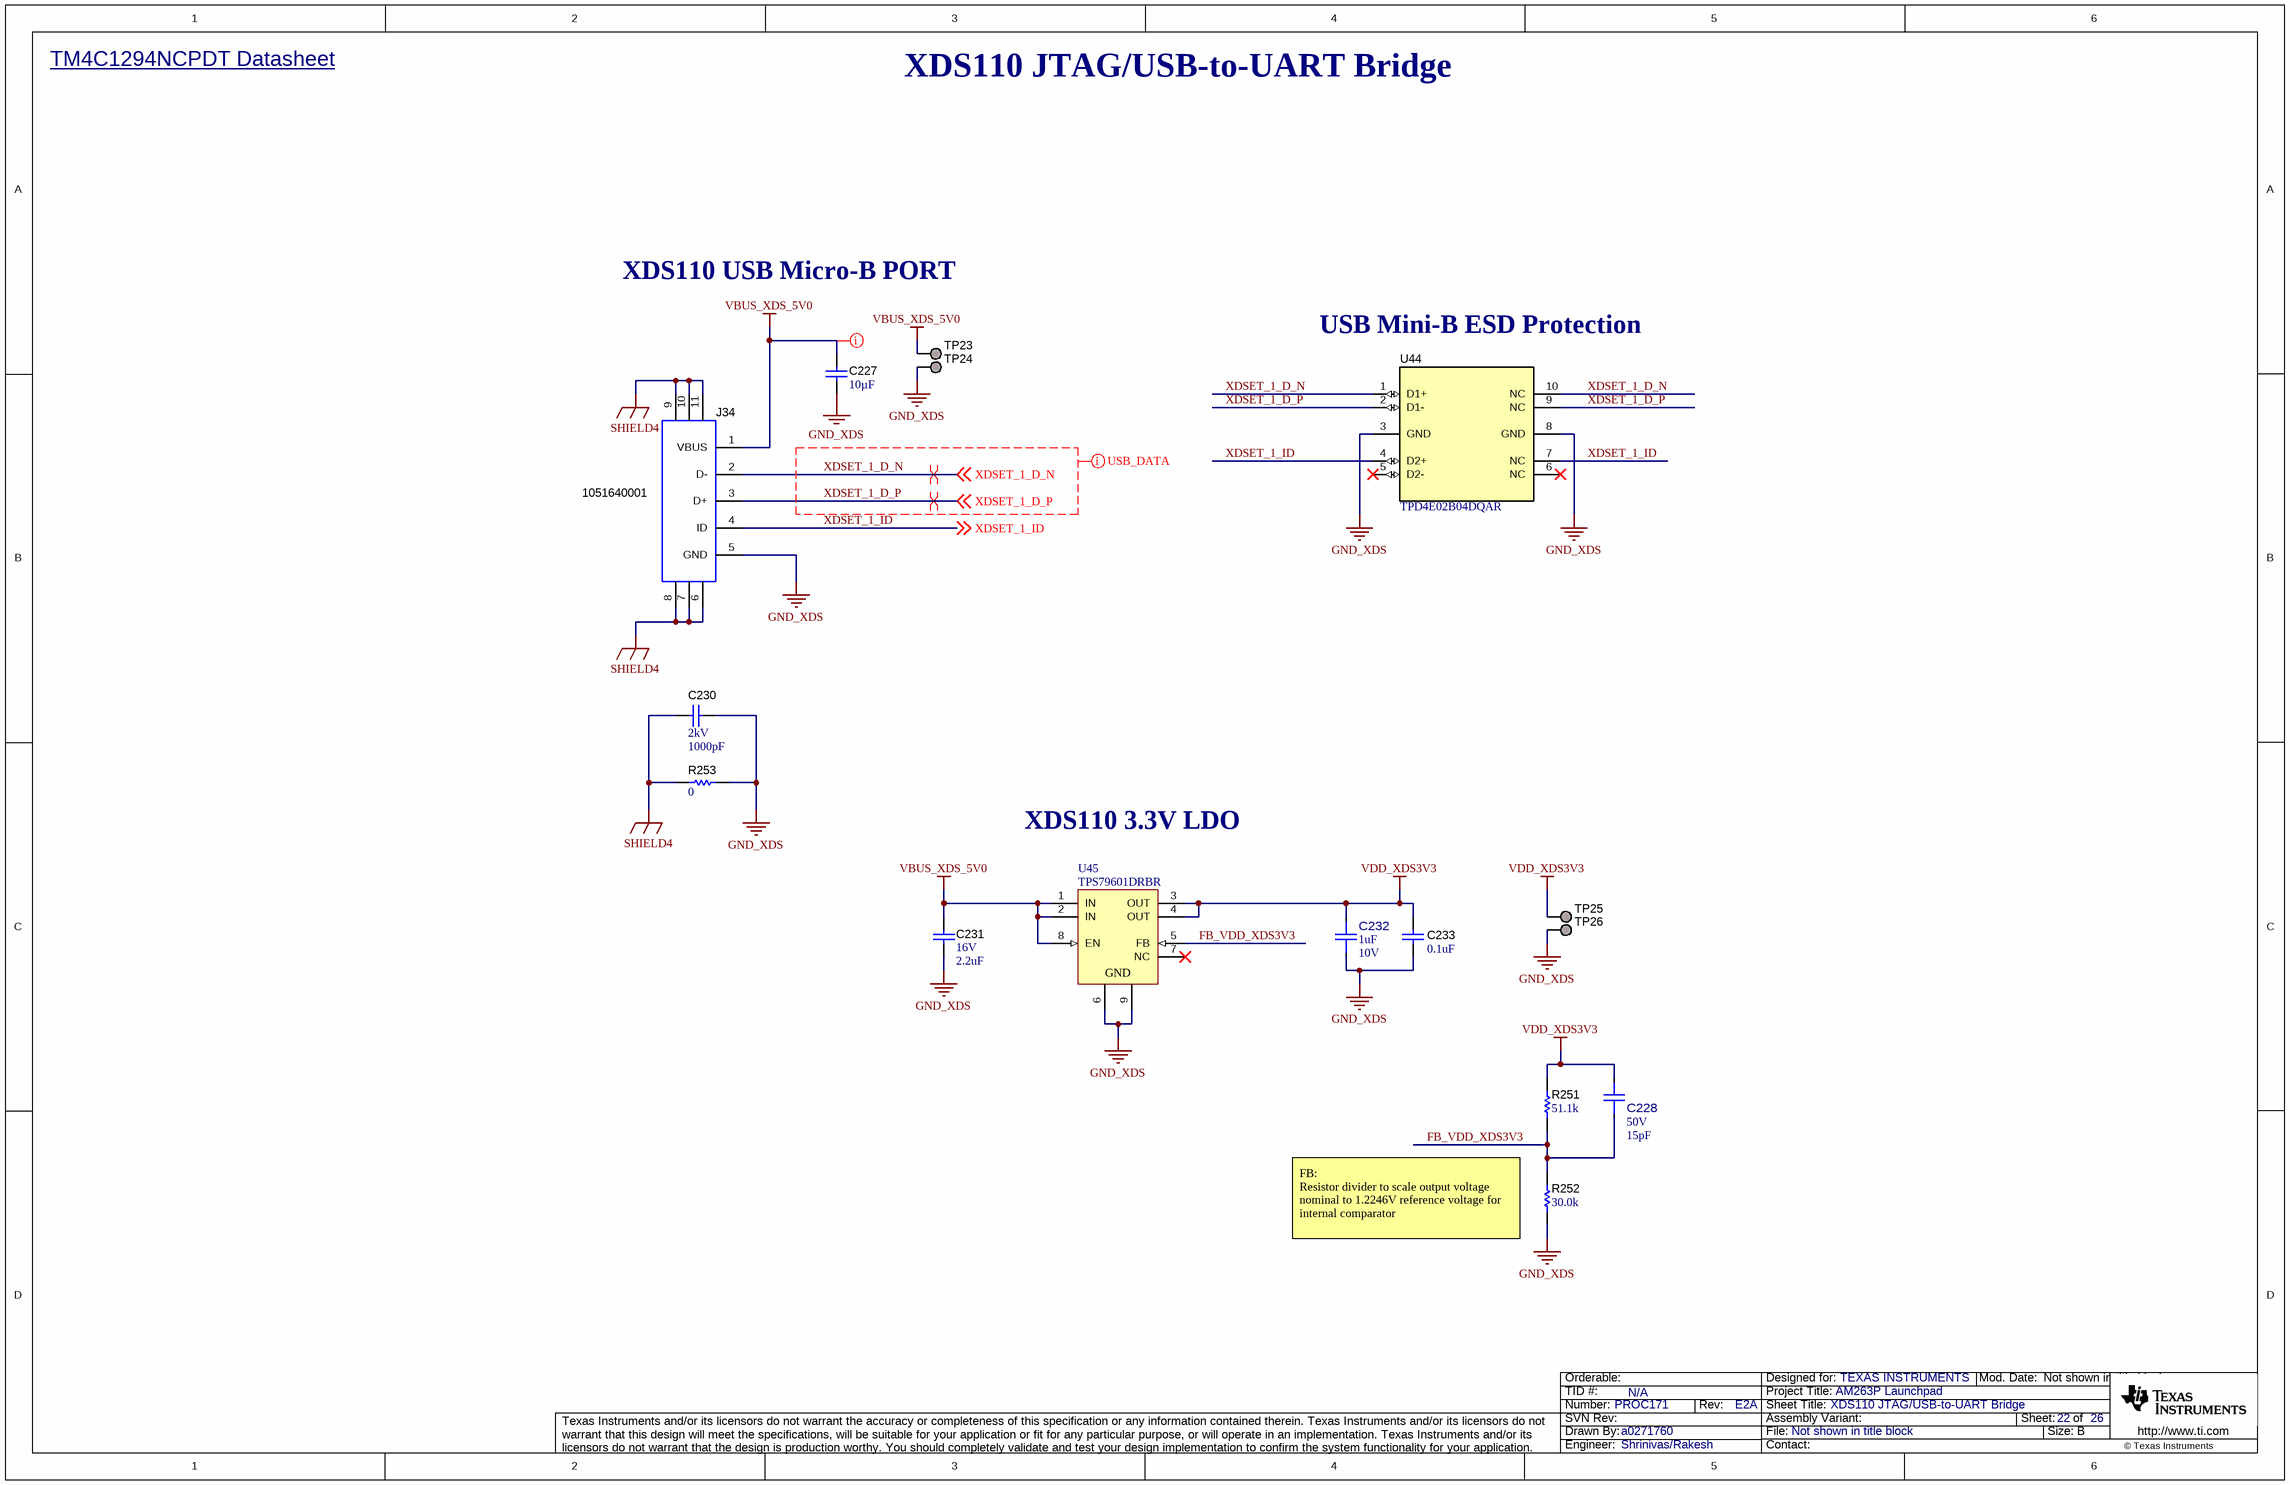
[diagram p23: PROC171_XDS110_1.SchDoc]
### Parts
C227  Cap_F: 10µF  [0805_HV]  (hidden comment: GRM21BZ71E106KE15L)
C228  VDC_V: 50V  ValueDisplayed: 15pF  [FP-GJM1555C1H150FB01D_0402-MFG]  (hidden comment: GJM1555C1H150FB01D)
C230  VDC_V: 2kV  ValueDisplayed: 1000pF  [1808]  (hidden comment: GR442QR73D102KW01L)
C231  VDC_V: 16V  ValueDisplayed: 2.2uF  [0402]  (hidden comment: GRM155C81C225KE11D)
C232  ValueDisplayed: 1uF  VDC_V: 10V  [FP-GRM155C71A105KE11D_0402-MFG]  (hidden comment: GRM155C71A105KE11D)
C233  ValueDisplayed: 0.1uF  [0402]  (hidden comment: GRM155R71E104KE14D)
J34  1051640001  [Molex_1051640001]
R251  ValueDisplayed: 51.1k  [0402]  (hidden comment: CRCW040251K1FKED)
R252  ValueDisplayed: 30.0k  [0402]  (hidden comment: CRCW040230K0FKED)
R253  ValueDisplayed: 0  [0805_HV]  (hidden comment: ERJ-6GEY0R00V)
TP23  TESTPOINT  [TP_25MIL-SMT]  (value not drawn)  (no BOM)
TP24  TESTPOINT  [TP_25MIL-SMT]  (value not drawn)  (no BOM)
TP25  TESTPOINT  [TP_25MIL-SMT]  (value not drawn)  (no BOM)
TP26  TESTPOINT  [TP_25MIL-SMT]  (value not drawn)  (no BOM)
U44  TPD4E02B04DQAR  [DQA0010A]
U45  TPS79601DRBR  [DRB0008B]

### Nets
GND_XDS: C227.2 C230.1 C231.2 C232.1 C233.1 J34.5(GND) R252.1 R253.2 TP24.1 TP26.1 U44.3(GND) U44.8(GND) U45.6(GND) U45.9(GND)
SHIELD4: C230.2 J34.6 J34.7 J34.8 J34.9 J34.10 J34.11 R253.1
VBUS_XDS_5V0: C227.1 C231.1 J34.1(VBUS) TP23.1 U45.1(IN) U45.2(IN) U45.8(EN)
VDD_XDS3V3: C228.2 C232.2 C233.2 R251.2 TP25.1 U45.3(OUT) U45.4(OUT)
FB_VDD_XDS3V3: C228.1 R251.1 R252.2 U45.5(FB)
XDSET_1_D_N: J34.2(D-) U44.1(D1+) U44.10(NC) ; off-sheet XDSET_1_D_N
XDSET_1_D_P: J34.3(D+) U44.2(D1-) U44.9(NC) ; off-sheet XDSET_1_D_P
XDSET_1_ID: J34.4(ID) U44.4(D2+) U44.7(NC) ; off-sheet XDSET_1_ID

Not connected (* = marked no-connect by the designer): U44 5(D2-)* 6(NC)*; U45 7(NC)*

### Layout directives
differential pair: XDSET_1_D_N, XDSET_1_D_P
net class POWER: VBUS_XDS_5V0
mark named USB_DATA: XDSET_1_D_N, XDSET_1_D_P

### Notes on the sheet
- TM4C1294NCPDT Datasheet <http://www.ti.com/lit/ds/symlink/tm4c1294ncpdt.pdf>
- XDS110 JTAG/USB-to-UART Bridge
- XDS110 USB Micro-B PORT
- USB Mini-B ESD Protection
- XDS110 3.3V LDO
- (near R252) FB:
  Resistor divider to scale output voltage nominal to 1.2246V reference voltage for internal comparator

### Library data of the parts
C227 = CMP-0008378-2: CAP, CERM, 10 uF, 25 V, +/- 10%, X7R, 0805; Manufacturer: MuRata; TaMin_C: -55°C; Polarized: N; SizeAreaWB_mm2: 6.75; Value1: Unknown; U/M: EA; Value: 10uF; TaMax_C: 125°C; SizeZ_mm: 1.45; SizeX_mm: 2; SizeY_mm: 1.25; Cap_Case: 0805; Value2: 25V; SizeArea_mm2: 2.5; AEC Category: Q200
C228 = CMP-0035231-1: Multi-Layer Ceramic Capacitor 15pF C0G  ±1% 0402 Paper T/R; Manufacturer: Murata; TempCo: 30ppm/°C; SizeZ_mm: 0.55mm; AEC Qualified: No
C230 = CMP-0009436-2: CAP, CERM, 1000 pF, 2000 V, +/- 10%, X7R, 1808; Manufacturer: MuRata; TaMin_C: -55°C; Polarized: N; SizeAreaWB_mm2: 16.5; Value1: Unknown; U/M: EA; Value: 1000pF; TaMax_C: 125°C; SizeZ_mm: 2.03; SizeX_mm: 4.5; SizeY_mm: 2; Value2: 2000V; SizeArea_mm2: 9; Cap_F: 1nF; AEC Category: Q200
C231 = CMP-0006526-2: CAP, CERM, 2.2 uF, 16 V, +/- 10%, X6S, 0402; Manufacturer: MuRata; TaMin_C: -55°C; Polarized: N; SizeAreaWB_mm2: 3; Value1: Unknown; U/M: EA; Value: 2.2uF; TaMax_C: 105°C; SizeZ_mm: 0.6; SizeX_mm: 1; SizeY_mm: 0.5; Cap_F: 2.2µF; AEC Category: Q200
C232 = CMP-0035346-1: 1µF ±10% 10V Ceramic Capacitor X7S 0402 (1005 Metric); Manufacturer: Murata; AEC Qualified: No; SizeZ_mm: 0.6mm; TempCo: 22%
C233 = CMP-0006659-2: as C223 on sheet PROC171_Breakout_Headers
J34 = CMP-0055311-1: Receptacle, USB 2.0, Micro B, 5 Position, R/A, SMT; Manufacturer: Molex; CNHeader: FALSE; Current_A: 1.8A; Gender: Female; Voltage_V: 30V; Pitch_mm: 0.65; ContactFinish: Gold; CT: TRUE; Cert_UL: Y
R251 = CMP-0026437-2: RES, 51.1 k, 1%, 0.063 W, AEC-Q200 Grade 0, 0402; Manufacturer: Vishay-Dale; Power_W: 63mW; TempCo: 100 ppm/C; Value_Code: 51k1; Value: 51.1k; EIA_Code: E96; SizeX_mm: 1; SizeY_mm: 0.5; SizeZ_mm: 0.6; Value2: 0.063W; AEC Qualified: Y; VDC_V: 50V; AEC Category: Q200; AEC Grade: 0
R252 = CMP-0078244-2: RES, 30.0 k, 1%, 0.063 W, AEC-Q200 Grade 0, 0402; Manufacturer: Vishay-Dale; Power_W: 63mW; Green_Lifecycle: Active; TempCo: 100 ppm/C; Value_Code: 30k0; Green_REACh: Passed; Value: 30.0k; Res_ohm: 30k; SizeX_mm: 1; SizeY_mm: 0.5; SizeZ_mm: 0.6; Value2: 0.063W; AEC Qualified: Y; VDC_V: 50V; AEC Grade: 0; AEC Category: Q200
R253 = CMP-0020616-3: RES, 0, 5%, 0.125 W, AEC-Q200 Grade 0, 0805; Manufacturer: Panasonic; Power_W: 125mW; TempCo: 600 ppm/C; Value_Code: 0000; Value: 0; EIA_Code: E24; SizeX_mm: 2; SizeY_mm: 1.25; SizeZ_mm: 1.45; Value2: 0.125W; SizeArea_mm2: 2.5; AEC Qualified: Y; VDC_V: 150V; AEC Category: Q200; SizeAreaWB_mm2: 6.75
TP23-TP26 = CMP-0078143-3: TEST POINT.  No entry in BOM.
U44 = CMP-0073612-3: 4-Channel ESD Protection Diode for USB Type-C and HDMI 2.0, DQA0010A (USON-10); Alternate Manufacturer: Texas Instruments; Green_Lifecycle: Active; SizeAreaWB_mm2: 7.0; Green_REACh: Passed; SizeZ_mm: 0.55; SizeX_mm: 1.0; SizeY_mm: 2.5; CompType: IC; AEC Category: Q200; AEC Qualified: Y
U45 = CMP-0036402-3: Single Output High PSRR LDO, 1 A, Adjustable 1.2 to 5.5 V Output, 2.7 to 5.5 V Input, 8-pin SON (DRB), -40 to 125 degC, Green (RoHS & no Sb/Br); Manufacturer: Texas Instruments; Vin(Min)(V): 2.7; Vout Adj(Max)(V): 5.5; Vout Adj(Min)(V): 1.2; Accuracy(%): 2; SubFamily: Single Channel LDO; Iq(Typ)(mA): 0.26; Vdo(Typ)(mV): 250; Iout(Max)(A): 1; AEC Category: Q200; AEC Qualified: N; CompType: IC; SizeAreaWB_mm2: 16.0; SizeArea_mm2: 9.0; SizeX_mm: 3.0; SizeZ_mm: 1.0

## Sheet PROC171_XDS110_2.SchDoc: XDS110 JTAG/USB-to-UART Bridge
size 431 x 279 mm; Date: Not shown in title block; ApprovedBy: Not shown in title block; CheckedBy: Not shown in title block; Author: Not shown in title block; CompanyName: Not shown in title block; Engineer: Not shown in title block; Organization: Not shown in title block; Address1: Not shown in title block; Address2: Not shown in title block; Address3: Not shown in title block; Address4: Not shown in title block; DocumentNumber: 23; Revision: Use project parameter SCH_Rev; SheetNumber: 23; SheetTotal: 26; PageSetup: Record=PageOptions¦CenterHorizontal=True¦CenterVertical=True¦PrintScale=1.00¦XCorrection=1.00¦YCorrection=1.00¦PrintKind=0¦BorderSize=5000000¦LeftOffset=0¦BottomOffset=0¦Orientation=2¦PaperLength=1000¦PaperWidth=1000¦Scale=100¦PaperSource=15¦PrintQuality=600¦MediaType=1¦DitherType=10¦PaperKind=Letter¦PrintScaleMode=1

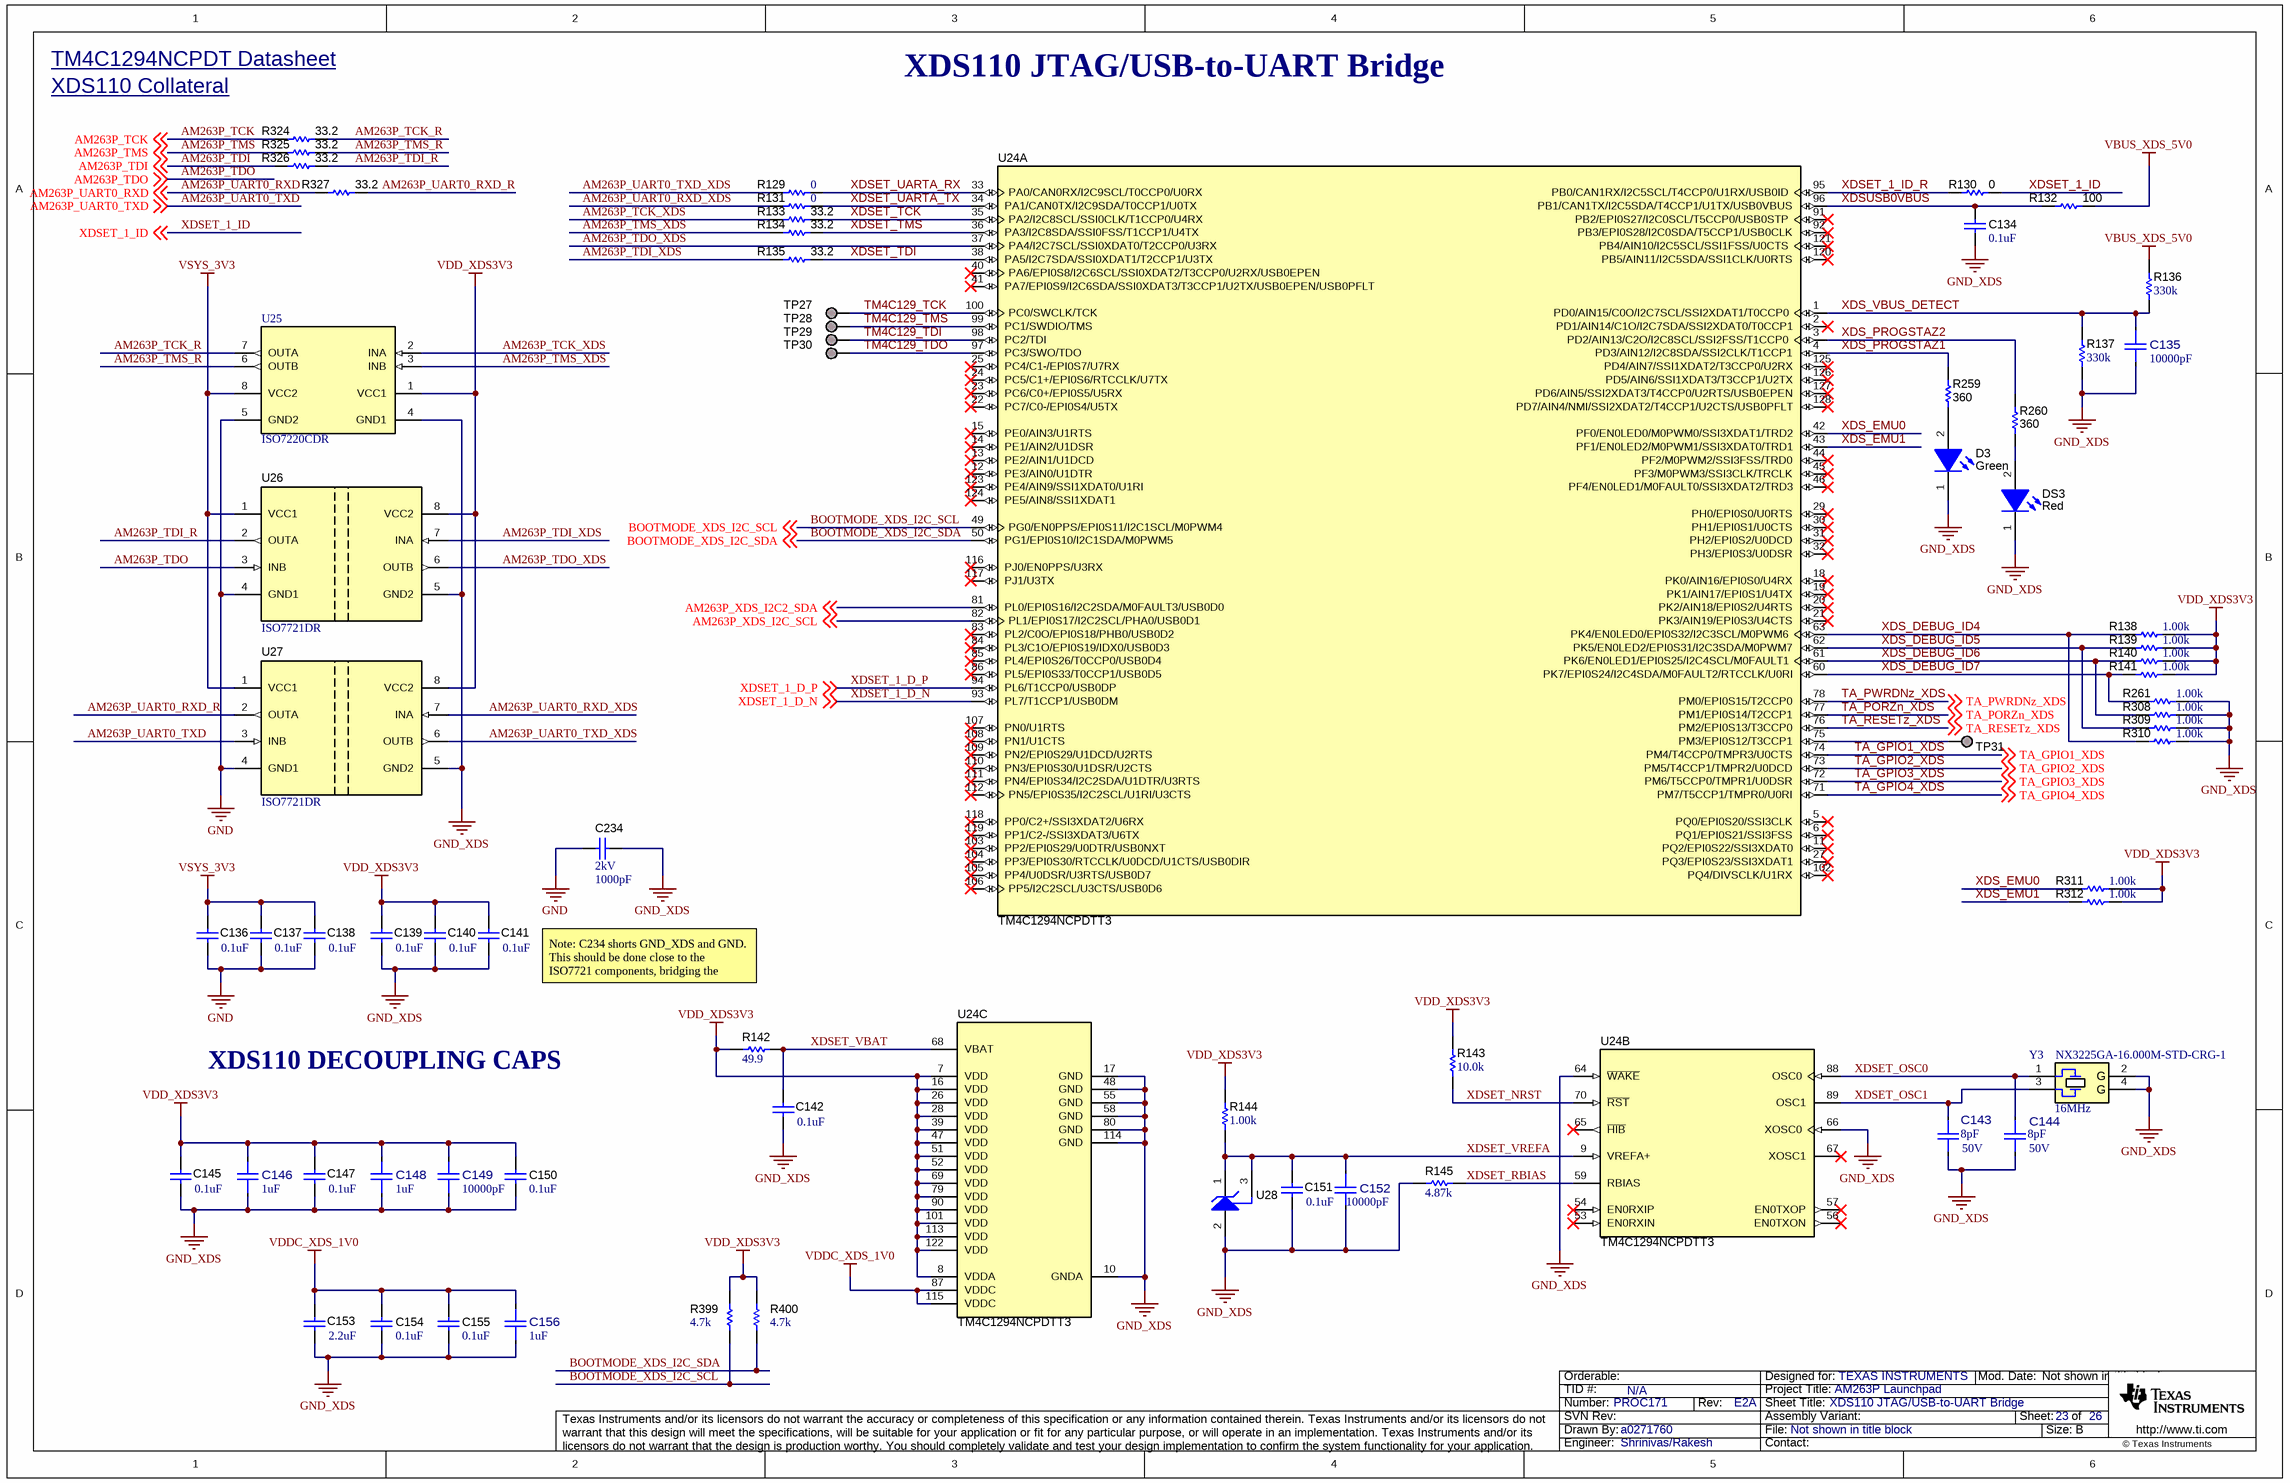
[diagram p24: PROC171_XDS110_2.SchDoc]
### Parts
C134  ValueDisplayed: 0.1uF  [0402]  (hidden comment: GRM155R71E104KE14D)
C135  ValueDisplayed: 10000pF  [FP-GRM1555C1E103JE01D_0402-MFG]  (hidden comment: GRM1555C1E103JE01D)
C136  ValueDisplayed: 0.1uF  [0402]  (hidden comment: GRM155R71E104KE14D)
C137  ValueDisplayed: 0.1uF  [0402]  (hidden comment: GRM155R71E104KE14D)
C138  ValueDisplayed: 0.1uF  [0402]  (hidden comment: GRM155R71E104KE14D)
C139  ValueDisplayed: 0.1uF  [0402]  (hidden comment: GRM155R71E104KE14D)
C140  ValueDisplayed: 0.1uF  [0402]  (hidden comment: GRM155R71E104KE14D)
C141  ValueDisplayed: 0.1uF  [0402]  (hidden comment: GRM155R71E104KE14D)
C142  ValueDisplayed: 0.1uF  [0402]  (hidden comment: GRM155R71E104KE14D)
C143  Cap_F: 8pF  VDC_V: 50V  [FP-GJM1555C1H8R0DB01D_0402-MFG]  (hidden comment: GJM1555C1H8R0DB01D)
C144  Cap_F: 8pF  VDC_V: 50V  [FP-GJM1555C1H8R0DB01D_0402-MFG]  (hidden comment: GJM1555C1H8R0DB01D)
C145  ValueDisplayed: 0.1uF  [0402]  (hidden comment: GRM155R71E104KE14D)
C146  ValueDisplayed: 1uF  [FP-GRM155C71A105KE11D_0402-MFG]  (hidden comment: GRM155C71A105KE11D)
C147  ValueDisplayed: 0.1uF  [0402]  (hidden comment: GRM155R71E104KE14D)
C148  ValueDisplayed: 1uF  [FP-GRM155C71A105KE11D_0402-MFG]  (hidden comment: GRM155C71A105KE11D)
C149  ValueDisplayed: 10000pF  [FP-GRM1555C1E103JE01D_0402-MFG]  (hidden comment: GRM1555C1E103JE01D)
C150  ValueDisplayed: 0.1uF  [0402]  (hidden comment: GRM155R71E104KE14D)
C151  ValueDisplayed: 0.1uF  [0402]  (hidden comment: GRM155R71E104KE14D)
C152  ValueDisplayed: 10000pF  [FP-GRM1555C1E103JE01D_0402-MFG]  (hidden comment: GRM1555C1E103JE01D)
C153  ValueDisplayed: 2.2uF  [0402]  (hidden comment: GRM155C81C225KE11D)
C154  ValueDisplayed: 0.1uF  [0402]  (hidden comment: GRM155R71E104KE14D)
C155  ValueDisplayed: 0.1uF  [0402]  (hidden comment: GRM155R71E104KE14D)
C156  ValueDisplayed: 1uF  [FP-GRM155C71A105KE11D_0402-MFG]  (hidden comment: GRM155C71A105KE11D)
C234  VDC_V: 2kV  ValueDisplayed: 1000pF  [1808]  (hidden comment: GR442QR73D102KW01L)
D3  value Green  [WL-SMCW_GREEN]  (hidden comment: 150060VS75000)
DS3  value Red  [WL-SMCW_RED]  (hidden comment: 150060RS75000)
R129  ValueDisplayed: 0  [0402]  (hidden comment: ERJ-2GE0R00X)
R130  ValueDisplayed: 0  [0402L]  (hidden comment: ERJ-2GE0R00X)
R131  ValueDisplayed: 0  [0402]  (hidden comment: ERJ-2GE0R00X)
R132  ValueDisplayed: 100  [0402L]  (hidden comment: ERJ-2GEJ101X)
R133  ValueDisplayed: 33.2  [0402]  (hidden comment: CRCW040233R2FKED)
R134  ValueDisplayed: 33.2  [0402]  (hidden comment: CRCW040233R2FKED)
R135  ValueDisplayed: 33.2  [0402]  (hidden comment: CRCW040233R2FKED)
R136  ValueDisplayed: 330k  [0402L]  (hidden comment: CRCW0402330KFKED)
R137  ValueDisplayed: 330k  [0402L]  (hidden comment: CRCW0402330KFKED)
R138  ValueDisplayed: 1.00k  [0402L]  (hidden comment: CRCW04021K00FKED)
R139  ValueDisplayed: 1.00k  [0402L]  (hidden comment: CRCW04021K00FKED)
R140  ValueDisplayed: 1.00k  [0402L]  (hidden comment: CRCW04021K00FKED)
R141  ValueDisplayed: 1.00k  [0402L]  (hidden comment: CRCW04021K00FKED)
R142  ValueDisplayed: 49.9  [0402L]  (hidden comment: CRCW040249R9FKED)
R143  ValueDisplayed: 10.0k  [0402L]  (hidden comment: CRCW040210K0FKED)
R144  ValueDisplayed: 1.00k  [0402L]  (hidden comment: CRCW04021K00FKED)
R145  ValueDisplayed: 4.87k  [0402L]  (hidden comment: CRCW04024K87FKED)
R259  ValueDisplayed: 360  [0402L]  (hidden comment: ERJ-2GEJ361X)
R260  ValueDisplayed: 360  [0402L]  (hidden comment: ERJ-2GEJ361X)
R261  ValueDisplayed: 1.00k  [0402L]  (hidden comment: CRCW04021K00FKED)
R308  ValueDisplayed: 1.00k  [0402L]  (hidden comment: CRCW04021K00FKED)
R309  ValueDisplayed: 1.00k  [0402L]  (hidden comment: CRCW04021K00FKED)
R310  ValueDisplayed: 1.00k  [0402L]  (hidden comment: CRCW04021K00FKED)
R311  ValueDisplayed: 1.00k  [0402L]  (hidden comment: CRCW04021K00FKED)
R312  ValueDisplayed: 1.00k  [0402L]  (hidden comment: CRCW04021K00FKED)
R324  ValueDisplayed: 33.2  [0402]  (hidden comment: CRCW040233R2FKED)
R325  ValueDisplayed: 33.2  [0402]  (hidden comment: CRCW040233R2FKED)
R326  ValueDisplayed: 33.2  [0402]  (hidden comment: CRCW040233R2FKED)
R327  ValueDisplayed: 33.2  [0402]  (hidden comment: CRCW040233R2FKED)
R399  ValueDisplayed: 4.7k  [0402]  (hidden comment: CRCW04024K70JNED)
R400  ValueDisplayed: 4.7k  [0402]  (hidden comment: CRCW04024K70JNED)
TP27  TESTPOINT  [TP_25MIL-SMT]  (value not drawn)  (no BOM)
TP28  TESTPOINT  [TP_25MIL-SMT]  (value not drawn)  (no BOM)
TP29  TESTPOINT  [TP_25MIL-SMT]  (value not drawn)  (no BOM)
TP30  TESTPOINT  [TP_25MIL-SMT]  (value not drawn)  (no BOM)
TP31  TESTPOINT  [TP_25MIL-SMT]  (value not drawn)  (no BOM)
U24  TM4C1294NCPDTT3  [PDT0128A]  (parts A,B,C of 3)
U25  ISO7220CDR  [D0008B_N]
U26  ISO7721DR  [D0008B_HV]
U27  ISO7721DR  [D0008B_HV]
U28  LM4040C25QDBZR  [DBZ0003A_N]  (value not drawn)
Y3  NX3225GA-16.000M-STD-CRG-1  Frequency_Fixed: 16MHz  [NDK_NX3225GA]

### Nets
GND: C136.1 C137.1 C138.1 C234.2 U25.5(GND2) U26.4(GND1) U27.4(GND1)
GND_XDS: C134.1 C135.2 C139.1 C140.1 C141.1 C142.2 C143.2 C144.2 C145.1 C146.1 C147.1 C148.1 C149.1 C150.1 C151.1 C152.2 C153.1 C154.1 C155.1 C156.1 C234.1 D3.1(K) DS3.1(K) R137.1 R145.1 R261.2 R308.2 R309.2 R310.2 U24.10(GNDA) U24.17(GND) U24.48(GND) U24.55(GND) U24.58(GND) U24.64(~{WAKE}) U24.66(XOSC0) U24.80(GND) U24.114(GND) U25.4(GND1) U26.5(GND2) U27.5(GND2) U28.2(ANODE) Y3.2(GND) Y3.4(GND)
VBUS_XDS_5V0: R132.2 R136.2
VDD_XDS3V3: C139.2 C140.2 C141.2 C145.2 C146.2 C147.2 C148.2 C149.2 C150.2 R138.2 R139.2 R140.2 R141.2 R142.2 R143.2 R144.2 R311.2 R312.2 R399.2 R400.2 U24.7(VDD) U24.8(VDDA) U24.16(VDD) U24.26(VDD) U24.28(VDD) U24.39(VDD) U24.47(VDD) U24.51(VDD) U24.52(VDD) U24.69(VDD) U24.79(VDD) U24.90(VDD) U24.101(VDD) U24.113(VDD) U24.122(VDD) U25.1(VCC1) U26.8(VCC2) U27.8(VCC2)
VDDC_XDS_1V0: C153.2 C154.2 C155.2 C156.2 U24.87(VDDC) U24.115(VDDC)
VSYS_3V3: C136.2 C137.2 C138.2 U25.8(VCC2) U26.1(VCC1) U27.1(VCC1)
AM263P_TCK: R324.1 ; off-sheet AM263P_TCK
AM263P_TCK_R: R324.2 U25.7(OUTA)
AM263P_TCK_XDS: R133.1 U25.2(INA)
AM263P_TDI: R326.1 ; off-sheet AM263P_TDI
AM263P_TDI_R: R326.2 U26.2(OUTA)
AM263P_TDI_XDS: R135.1 U26.7(INA)
AM263P_TDO: U26.3(INB) ; off-sheet AM263P_TDO
AM263P_TDO_XDS: U24.37(PA4/I2C7SCL/SSI0XDAT0/T2CCP0/U3RX) U26.6(OUTB)
AM263P_TMS: R325.1 ; off-sheet AM263P_TMS
AM263P_TMS_R: R325.2 U25.6(OUTB)
AM263P_TMS_XDS: R134.1 U25.3(INB)
AM263P_UART0_RXD: R327.1 ; off-sheet AM263P_UART0_RXD
AM263P_UART0_RXD_R: R327.2 U27.2(OUTA)
AM263P_UART0_RXD_XDS: R131.1 U27.7(INA)
AM263P_UART0_TXD: U27.3(INB) ; off-sheet AM263P_UART0_TXD
AM263P_UART0_TXD_XDS: R129.1 U27.6(OUTB)
AM263P_XDS_I2C2_SDA: U24.81(PL0/EPI0S16/I2C2SDA/M0FAULT3/USB0D0) ; off-sheet AM263P_XDS_I2C2_SDA
AM263P_XDS_I2C_SCL: U24.82(PL1/EPI0S17/I2C2SCL/PHA0/USB0D1) ; off-sheet AM263P_XDS_I2C_SCL
BOOTMODE_XDS_I2C_SCL: R399.1 U24.49(PG0/EN0PPS/EPI0S11/I2C1SCL/M0PWM4) ; off-sheet BOOTMODE_XDS_I2C_SCL
BOOTMODE_XDS_I2C_SDA: R400.1 U24.50(PG1/EPI0S10/I2C1SDA/M0PWM5) ; off-sheet BOOTMODE_XDS_I2C_SDA
TA_GPIO1_XDS: U24.74(PM4/T4CCP0/TMPR3/U0CTS) ; off-sheet TA_GPIO1_XDS
TA_GPIO2_XDS: U24.73(PM5/T4CCP1/TMPR2/U0DCD) ; off-sheet TA_GPIO2_XDS
TA_GPIO3_XDS: U24.72(PM6/T5CCP0/TMPR1/U0DSR) ; off-sheet TA_GPIO3_XDS
TA_GPIO4_XDS: U24.71(PM7/T5CCP1/TMPR0/U0RI) ; off-sheet TA_GPIO4_XDS
TA_PORZn_XDS: U24.77(PM1/EPI0S14/T2CCP1) ; off-sheet TA_PORZn_XDS
TA_PWRDNz_XDS: U24.78(PM0/EPI0S15/T2CCP0) ; off-sheet TA_PWRDNz_XDS
TA_RESETz_XDS: U24.76(PM2/EPI0S13/T3CCP0) ; off-sheet TA_RESETz_XDS
TM4C129_TCK: TP27.1 U24.100(PC0/SWCLK/TCK)
TM4C129_TDI: TP29.1 U24.98(PC2/TDI)
TM4C129_TDO: TP30.1 U24.97(PC3/SWO/TDO)
TM4C129_TMS: TP28.1 U24.99(PC1/SWDIO/TMS)
XDS_DEBUG_ID4: R138.1 R310.1 U24.63(PK4/EN0LED0/EPI0S32/I2C3SCL/M0PWM6)
XDS_DEBUG_ID5: R139.1 R309.1 U24.62(PK5/EN0LED2/EPI0S31/I2C3SDA/M0PWM7)
XDS_DEBUG_ID6: R140.1 R308.1 U24.61(PK6/EN0LED1/EPI0S25/I2C4SCL/M0FAULT1)
XDS_DEBUG_ID7: R141.1 R261.1 U24.60(PK7/EPI0S24/I2C4SDA/M0FAULT2/RTCCLK/U0RI)
XDS_EMU0: R311.1 U24.42(PF0/EN0LED0/M0PWM0/SSI3XDAT1/TRD2)
XDS_EMU1: R312.1 U24.43(PF1/EN0LED2/M0PWM1/SSI3XDAT0/TRD1)
XDS_PROGSTAZ1: R259.2 U24.4(PD3/AIN12/I2C8SDA/SSI2CLK/T1CCP1)
XDS_PROGSTAZ2: R260.2 U24.3(PD2/AIN13/C2O/I2C8SCL/SSI2FSS/T1CCP0)
XDS_VBUS_DETECT: C135.1 R136.1 R137.2 U24.1(PD0/AIN15/C0O/I2C7SCL/SSI2XDAT1/T0CCP0)
XDSET_1_D_N: U24.93(PL7/T1CCP1/USB0DM) ; off-sheet XDSET_1_D_N
XDSET_1_D_P: U24.94(PL6/T1CCP0/USB0DP) ; off-sheet XDSET_1_D_P
XDSET_1_ID: R130.1 ; off-sheet XDSET_1_ID
XDSET_1_ID_R: R130.2 U24.95(PB0/CAN1RX/I2C5SCL/T4CCP0/U1RX/USB0ID)
XDSET_NRST: R143.1 U24.70(~{RST})
XDSET_OSC0: C144.1 U24.88(OSC0) Y3.1
XDSET_OSC1: C143.1 U24.89(OSC1) Y3.3
XDSET_RBIAS: R145.2 U24.59(RBIAS)
XDSET_TCK: R133.2 U24.35(PA2/I2C8SCL/SSI0CLK/T1CCP0/U4RX)
XDSET_TDI: R135.2 U24.38(PA5/I2C7SDA/SSI0XDAT1/T2CCP1/U3TX)
XDSET_TMS: R134.2 U24.36(PA3/I2C8SDA/SSI0FSS/T1CCP1/U4TX)
XDSET_UARTA_RX: R129.2 U24.33(PA0/CAN0RX/I2C9SCL/T0CCP0/U0RX)
XDSET_UARTA_TX: R131.2 U24.34(PA1/CAN0TX/I2C9SDA/T0CCP1/U0TX)
XDSET_VBAT: C142.1 R142.1 U24.68(VBAT)
XDSET_VREFA: C151.2 C152.1 R144.1 U24.9(VREFA+) U28.1(CATHODE) U28.3(NC)
XDSUSB0VBUS: C134.2 R132.1 U24.96(PB1/CAN1TX/I2C5SDA/T4CCP1/U1TX/USB0VBUS)
NetD3_2: D3.2(A) R259.1
NetDS3_2: DS3.2(A) R260.1
NetTP31_1: TP31.1 U24.75(PM3/EPI0S12/T3CCP1)

Not connected (* = marked no-connect by the designer): U24 2(PD1/AIN14/C1O/I2C7SDA/SSI2XDAT0/T0CCP1)* 5(PQ0/EPI0S20/SSI3CLK)* 6(PQ1/EPI0S21/SSI3FSS)* 11(PQ2/EPI0S22/SSI3XDAT0)* 12(PE3/AIN0/U1DTR)* 13(PE2/AIN1/U1DCD)* 14(PE1/AIN2/U1DSR)* 15(PE0/AIN3/U1RTS)* 18(PK0/AIN16/EPI0S0/U4RX)* 19(PK1/AIN17/EPI0S1/U4TX)* 20(PK2/AIN18/EPI0S2/U4RTS)* 21(PK3/AIN19/EPI0S3/U4CTS)* 22(PC7/C0-/EPI0S4/U5TX)* 23(PC6/C0+/EPI0S5/U5RX)* 24(PC5/C1+/EPI0S6/RTCCLK/U7TX)* 25(PC4/C1-/EPI0S7/U7RX)* 27(PQ3/EPI0S23/SSI3XDAT1)* 29(PH0/EPI0S0/U0RTS)* 30(PH1/EPI0S1/U0CTS)* 31(PH2/EPI0S2/U0DCD)* 32(PH3/EPI0S3/U0DSR)* 40(PA6/EPI0S8/I2C6SCL/SSI0XDAT2/T3CCP0/U2RX/USB0EPEN)* 41(PA7/EPI0S9/I2C6SDA/SSI0XDAT3/T3CCP1/U2TX/USB0EPEN/USB0PFLT)* 44(PF2/M0PWM2/SSI3FSS/TRD0)* 45(PF3/M0PWM3/SSI3CLK/TRCLK)* 46(PF4/EN0LED1/M0FAULT0/SSI3XDAT2/TRD3)* 53(EN0RXIN)* 54(EN0RXIP)* 56(EN0TXON)* 57(EN0TXOP)* 65(~{HIB})* 67(XOSC1)* 83(PL2/C0O/EPI0S18/PHB0/USB0D2)* 84(PL3/C1O/EPI0S19/IDX0/USB0D3)* 85(PL4/EPI0S26/T0CCP0/USB0D4)* 86(PL5/EPI0S33/T0CCP1/USB0D5)* 91(PB2/EPI0S27/I2C0SCL/T5CCP0/USB0STP)* 92(PB3/EPI0S28/I2C0SDA/T5CCP1/USB0CLK)* 102(PQ4/DIVSCLK/U1RX)* 103(PP2/EPI0S29/U0DTR/USB0NXT)* 104(PP3/EPI0S30/RTCCLK/U0DCD/U1CTS/USB0DIR)* 105(PP4/U0DSR/U3RTS/USB0D7)* 106(PP5/I2C2SCL/U3CTS/USB0D6)* 107(PN0/U1RTS)* 108(PN1/U1CTS)* 109(PN2/EPI0S29/U1DCD/U2RTS)* 110(PN3/EPI0S30/U1DSR/U2CTS)* 111(PN4/EPI0S34/I2C2SDA/U1DTR/U3RTS)* 112(PN5/EPI0S35/I2C2SCL/U1RI/U3CTS)* 116(PJ0/EN0PPS/U3RX)* 117(PJ1/U3TX)* 118(PP0/C2+/SSI3XDAT2/U6RX)* 119(PP1/C2-/SSI3XDAT3/U6TX)* 120(PB5/AIN11/I2C5SDA/SSI1CLK/U0RTS)* 121(PB4/AIN10/I2C5SCL/SSI1FSS/U0CTS)* 123(PE4/AIN9/SSI1XDAT0/U1RI)* 124(PE5/AIN8/SSI1XDAT1)* 125(PD4/AIN7/SSI1XDAT2/T3CCP0/U2RX)* 126(PD5/AIN6/SSI1XDAT3/T3CCP1/U2TX)* 127(PD6/AIN5/SSI2XDAT3/T4CCP0/U2RTS/USB0EPEN)* 128(PD7/AIN4/NMI/SSI2XDAT2/T4CCP1/U2CTS/USB0PFLT)*

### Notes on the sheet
- XDS110 Collateral <https://software-dl.ti.com/ccs/esd/documents/xdsdebugprobes/emu_xds110.html>
- TM4C1294NCPDT Datasheet <http://www.ti.com/lit/ds/symlink/tm4c1294ncpdt.pdf>
- XDS110 JTAG/USB-to-UART Bridge
- Note: C234 shorts GND_XDS and GND. This should be done close to the ISO7721 components, bridging the air-gap between the two portions of the PCB
- XDS110 DECOUPLING CAPS

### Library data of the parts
C134 C136-C142 C145 C147 C150 C151 C154 C155 = CMP-0006659-2: as C223 on sheet PROC171_Breakout_Headers
C135 C149 C152 = CMP-0035343-1: Chip Multilayer Ceramic Capacitors for General Purpose, 0402, 10000pF, C0G, 30ppm/°C, 5%, 25V; Manufacturer: Murata; Value: 10nF; SizeZ_mm: 0.65mm; AEC Qualified: No
C143 C144 = CMP-0035284-1: Multi-Layer Ceramic Capacitor 8pF C0G  ±0.5pF 0402 Paper T/R; Manufacturer: Murata; TempCo: 30ppm/°C; AEC Qualified: No; SizeZ_mm: 0.55mm
C146 C148 C156 = CMP-0035346-1: 1µF ±10% 10V Ceramic Capacitor X7S 0402 (1005 Metric); Manufacturer: Murata; TempCo: 22%; SizeZ_mm: 0.6mm; AEC Qualified: No
C153 = CMP-0006526-2: CAP, CERM, 2.2 uF, 16 V, +/- 10%, X6S, 0402; Manufacturer: MuRata; TaMin_C: -55°C; Polarized: N; SizeAreaWB_mm2: 3; Value1: Unknown; U/M: EA; Value: 2.2uF; TaMax_C: 105°C; SizeZ_mm: 0.6; SizeX_mm: 1; SizeY_mm: 0.5; Value2: 16V; Cap_F: 2.2µF; AEC Category: Q200
C234 = CMP-0009436-2: as C230 on sheet PROC171_XDS110_1
D3 = CMP-0002894-2: as D2 on sheet PROC171_LED
DS3 = CMP-0002947-3: as DS1 on sheet PROC171_LED
R129 R131 = CMP-0026992-3: RES, 0, 5%, 0.1 W, AEC-Q200 Grade 0, 0402; Manufacturer: Panasonic; Power_W: 100mW; TempCo: 600 ppm/C; Value_Code: 0000; Value: 0; EIA_Code: E24; SizeX_mm: 1; SizeY_mm: 0.5; SizeZ_mm: 0.6; Value2: 0.1W; CompType: Resistor; AEC Qualified: Y; VDC_V: 50V; AEC Category: Q200; SizeAreaWB_mm2: 3; INSTALLATION: DNP
R130 = CMP-0026992-3: as R248 on sheet PROC171_Breakout_Headers
R132 = CMP-0026993-2: RES, 100, 5%, 0.1 W, AEC-Q200 Grade 0, 0402; Manufacturer: Panasonic; Power_W: 100mW; TempCo: 200 ppm/C; Value_Code: 100R; U/M: EA; Value: 100; EIA_Code: E24; SizeX_mm: 1; SizeY_mm: 0.5; SizeZ_mm: 0.6; Value2: 0.1W; AEC Qualified: Y; AEC Grade: 0; AEC Category: Q200
R133-R135 R324-R327 = CMP-0026299-2: as R328 on sheet PROC171_Breakout_Headers
R136 R137 = CMP-0078210-2: RES, 330 k, 1%, 0.063 W, AEC-Q200 Grade 0, 0402; Manufacturer: Vishay-Dale; SizeArea_mm2: 0.5; AEC Qualified: Y; AEC Category: Q200; Value: 330k; SizeZ_mm: 0.6; TempCo: 100 ppm/C; AEC Grade: 0; Power_W: 63mW; VDC_V: 50V; Value2: 0.063W; SizeX_mm: 1
R138-R141 R144 R261 R308-R312 = CMP-0026071-3: RES, 1.00 k, 1%, 0.063 W, AEC-Q200 Grade 0, 0402; Manufacturer: Vishay-Dale; Power_W: 63mW; TempCo: 100 ppm/C; Value_Code: 1k00; Value: 1.00k; EIA_Code: E96; Res_ohm: 1k; SizeX_mm: 1; SizeY_mm: 0.5; SizeZ_mm: 0.6; Value2: 0.063W; AEC Qualified: Y; VDC_V: 50V; AEC Category: Q200; AEC Grade: 0
R142 = CMP-0026404-2: RES, 49.9, 1%, 0.063 W, AEC-Q200 Grade 0, 0402; Manufacturer: Vishay-Dale; Power_W: 63mW; TempCo: 100 ppm/C; Value_Code: 49R9; Value: 49.9; EIA_Code: E96; SizeX_mm: 1; SizeY_mm: 0.5; SizeZ_mm: 0.6; Value2: 0.063W; AEC Qualified: Y; VDC_V: 50V; AEC Category: Q200; AEC Grade: 0
R143 = CMP-0025958-3: as R244 on sheet PROC171_Breakout_Headers
R145 = CMP-0026413-2: RES, 4.87 k, 1%, 0.063 W, AEC-Q200 Grade 0, 0402; Manufacturer: Vishay-Dale; Power_W: 63mW; TempCo: 100 ppm/C; Value_Code: 4k87; Value: 4.87k; EIA_Code: E96; SizeX_mm: 1; SizeY_mm: 0.5; SizeZ_mm: 0.6; Value2: 0.063W; AEC Qualified: Y; VDC_V: 50V; AEC Category: Q200; AEC Grade: 0
R259 R260 = CMP-0078194-1: as R265 on sheet PROC171_LED
R399 R400 = CMP-0026938-5: RES, 4.7 k, 5%, 0.063 W, AEC-Q200 Grade 0, 0402; Manufacturer: Vishay-Dale; Power_W: 63mW; TempCo: 200 ppm/C; Value_Code: 4k70; Value: 4.7k; EIA_Code: E24; SizeX_mm: 1; SizeY_mm: 0.5; SizeZ_mm: 0.6; Value2: 0.063W; AEC Qualified: Y; VDC_V: 50V; AEC Category: Q200; AEC Grade: 0
TP27-TP31 = CMP-0078143-3: TEST POINT.  No entry in BOM.
U24 = CMP-0029856-2: Tiva C Series Microcontroller, 1024 KB Flash, 256 KB SRAM, 12 Bit, 20 Channels, -40 to 105 degC, 128-Pin TQFP (PDT), Green (RoHS & no Sb/Br), Tray; Manufacturer: Texas Instruments; ADC Channels: 20; CPU: ARM Cortex-M4; Flash: 1024 KB; ADC Resolution: 12 Bits; Max Speed: 120 MHz; SRAM: 256 KB; SizeAreaWB_mm2: 324.0; SizeArea_mm2: 256.0; SizeX_mm: 16.0; SizeZ_mm: 1.2; CompType: IC
U25 = CMP-0029369-1: 25 Mbps Dual Channels, 2 / 0, Digital Isolator, 3.3 V / 5 V, -40 to +125 degC, 8-pin SOIC (D), Green (RoHS & no Sb/Br); Manufacturer: Texas Instruments; Supply Voltage(s)(V): 3.3, 5; Prop Delay(Max)(ns): 42; Insulation Rating(VRMS): 2500; Datarate(Mbps): 25; TTL/CMOS Input Threshold: TTL; Rating: Catalog; Input Noise Filter: Yes
U26 U27 = CMP-0076059-2: High Speed, Robust EMC Dual-Channel Digital Isolator, D0008B (SOIC-8); Manufacturer: Texas Instruments; SizeY_mm: 4.9; SizeArea_mm2: 29.4; Rating: Catalog; CompType: IC; AEC Category: Q200; AEC Qualified: N; SizeZ_mm: 1.75; SizeAreaWB_mm2: 55.2; SizeX_mm: 6.0
U28 = CMP-0033001-1: Precision Micropower Shunt Voltage Reference, 0.5% accuracy, 2.5 V, 15 ppm / degC, 15 mA, -40 to 125 degC, 3-pin SOT-23 (DBZ), Green (RoHS & no Sb/Br); Manufacturer: Texas Instruments; Initial Accuracy @ 25/deg C(%): 0.5; Temp Coeff(Typ)(ppm/ degree C): 15; Temp Coeff(Max)(ppm/ degree C): 100; Rating: Catalog; Min Iz for Regulation(uA): 75; VO(V): 2.5
Y3 = CMP-0004635-3: Crystal, 16 MHz, 8pF, SMD; Manufacturer: NDK; TaMax_C: 70°C; TaMin_C: -10°C; Frequency Stability: +/-30ppm

## Sheet PROC171_Hardware.SchDoc
size 431 x 279 mm; Date: Not shown in title block; ApprovedBy: Not shown in title block; CheckedBy: Not shown in title block; Author: Not shown in title block; CompanyName: Not shown in title block; Engineer: Not shown in title block; Organization: Not shown in title block; Address1: Not shown in title block; Address2: Not shown in title block; Address3: Not shown in title block; Address4: Not shown in title block; DocumentNumber: 26; Revision: Use project parameter SCH_Rev; SheetNumber: 26; SheetTotal: 26; PageSetup: Record=PageOptions¦CenterHorizontal=True¦CenterVertical=True¦PrintScale=1.00¦XCorrection=1.00¦YCorrection=1.00¦PrintKind=0¦BorderSize=5000000¦LeftOffset=0¦BottomOffset=0¦Orientation=2¦PaperLength=1000¦PaperWidth=1000¦Scale=100¦PaperSource=15¦PrintQuality=600¦MediaType=1¦DitherType=10¦PaperKind=Letter¦PrintScaleMode=1

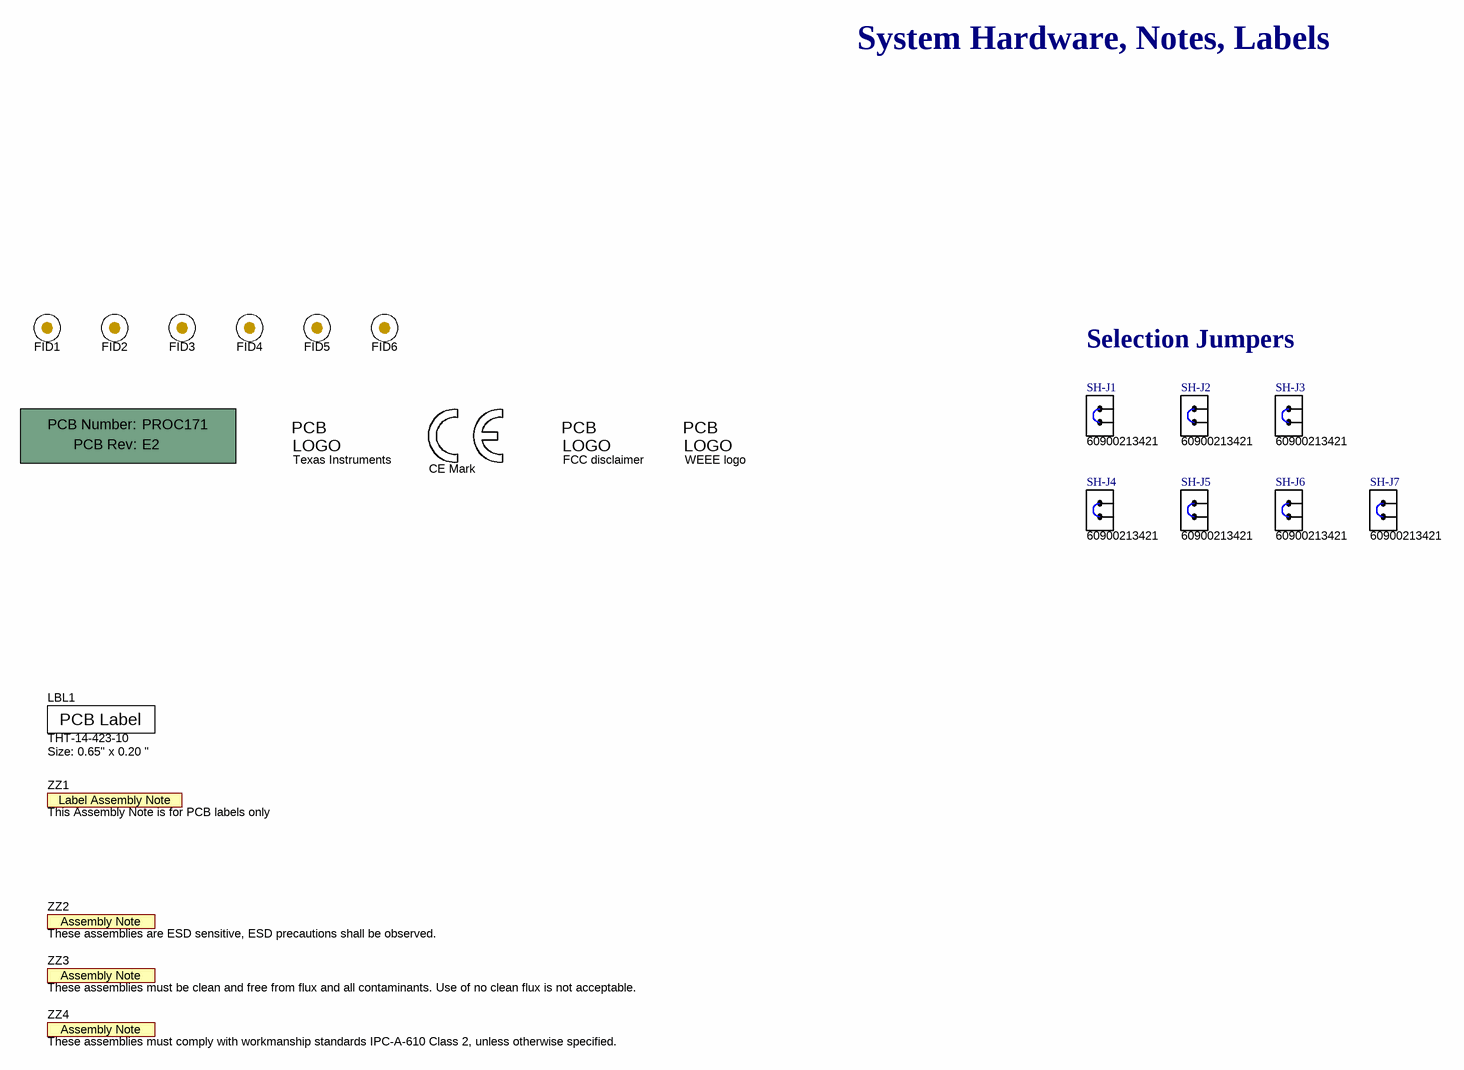
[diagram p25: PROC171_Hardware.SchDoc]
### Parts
!PCB1  Printed Circuit Board  (value not drawn)  (mechanical)
FID1  Fiducial  [Fiducial10-20]  (value not drawn)  (no BOM)
FID2  Fiducial  [Fiducial10-20]  (value not drawn)  (no BOM)
FID3  Fiducial  [Fiducial10-20]  (value not drawn)  (no BOM)
FID4  Fiducial  [Fiducial10-20]  (value not drawn)  (no BOM)
FID5  Fiducial  [Fiducial10-20]  (value not drawn)  (no BOM)
FID6  Fiducial  [Fiducial10-20]  (value not drawn)  (no BOM)
LBL1  THT-14-423-10  Note: Size: 0.65" x 0.20 "  [Label_650x200]
Logo1  CE Mark  [CE_Mark_5mm]  (no BOM)
Logo2  Texas Instruments  [TI_Stacked_Overlay_Small]  (no BOM)
Logo3  FCC disclaimer  [FCC_disclaimer]  (no BOM)
Logo4  WEEE logo  [WEEE_Minimum]  (no BOM)
SH-J1  60900213421  [Wurth_60900213421]
SH-J2  60900213421  [Wurth_60900213421]
SH-J3  60900213421  [Wurth_60900213421]
SH-J4  60900213421  [Wurth_60900213421]
SH-J5  60900213421  [Wurth_60900213421]
SH-J6  60900213421  [Wurth_60900213421]
SH-J7  60900213421  [Wurth_60900213421]
ZZ1  This Assembly Note is for PCB labels only  [AssemblyNoteLabel]  (no BOM)
ZZ2  These assemblies are ESD sensitive, ESD precautions shall be observed.  [AssemblyNote]  (no BOM)
ZZ3  These assemblies must be clean and free from flux and all contaminants. Use of no clean flux is not acceptable.  [AssemblyNote]  (no BOM)
ZZ4  These assemblies must comply with workmanship standards IPC-A-610 Class 2, unless otherwise specified.  [AssemblyNote]  (no BOM)

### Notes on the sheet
- System Hardware, Notes, Labels
- Selection Jumpers

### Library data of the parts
!PCB1 = CMP-0003618-2: Manufacturer: Any; PartNumber: PROC171
FID1-FID6 = CMP-0077181-1: Fiducial mark.  There is nothing to buy or mount.
LBL1 = CMP-0003625-1: Thermal Transfer Printable Labels, 0.650" W x 0.200" H - 10,000 per roll; Manufacturer: Brady; CompType: Label
Logo1 = CMP-0074844-1: SymbolCreator: a0412235
Logo2 = CMP-0074838-1: Texas Instrument Corporate Signature; SymbolCreator: a0412235; Lib Reference: TI_Logo; Library Reference: Logo
Logo3 = CMP-0074847-1: FCC_disclaimer; Library Reference: Logo
Logo4 = CMP-0074769-1
SH-J1-SH-J7 = CMP-0003761-2: Shunt, 2.54mm, Gold, Black; Manufacturer: Wurth Elektronik
ZZ1 = CMP-0003616-3
ZZ2 = CMP-0077236-1
ZZ3 = CMP-0077237-1
ZZ4 = CMP-0077238-1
